VERSION 5.7 ;
BUSBITCHARS "[]" ;
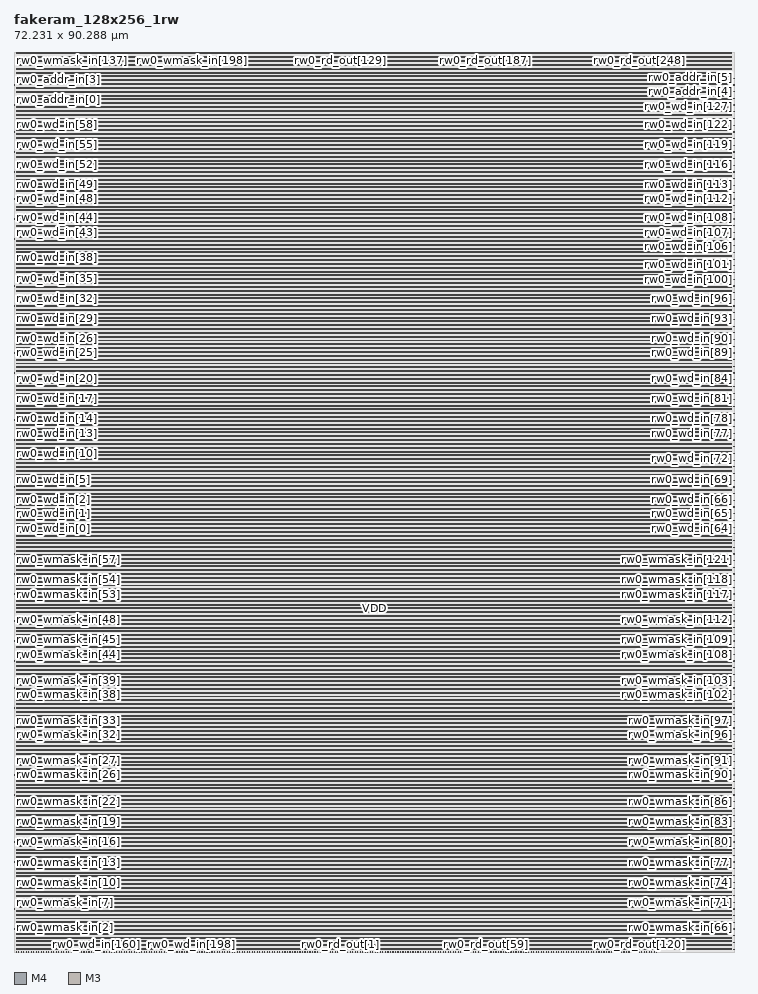
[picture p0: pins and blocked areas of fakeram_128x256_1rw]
MACRO fakeram_128x256_1rw
  FOREIGN fakeram_128x256_1rw 0 0 ;
  SYMMETRY X Y R90 ;
  SIZE 72.231 BY 90.288 ;
  CLASS BLOCK ;
  PIN rw0_wmask_in[0]
    DIRECTION INPUT ;
    USE SIGNAL ;
    SHAPE ABUTMENT ;
    PORT
      LAYER M4 ;
      RECT 0.000 0.276 0.072 0.300 ;
    END
  END rw0_wmask_in[0]
  PIN rw0_wmask_in[1]
    DIRECTION INPUT ;
    USE SIGNAL ;
    SHAPE ABUTMENT ;
    PORT
      LAYER M4 ;
      RECT 0.000 0.948 0.072 0.972 ;
    END
  END rw0_wmask_in[1]
  PIN rw0_wmask_in[2]
    DIRECTION INPUT ;
    USE SIGNAL ;
    SHAPE ABUTMENT ;
    PORT
      LAYER M4 ;
      RECT 0.000 1.620 0.072 1.644 ;
    END
  END rw0_wmask_in[2]
  PIN rw0_wmask_in[3]
    DIRECTION INPUT ;
    USE SIGNAL ;
    SHAPE ABUTMENT ;
    PORT
      LAYER M4 ;
      RECT 0.000 2.292 0.072 2.316 ;
    END
  END rw0_wmask_in[3]
  PIN rw0_wmask_in[4]
    DIRECTION INPUT ;
    USE SIGNAL ;
    SHAPE ABUTMENT ;
    PORT
      LAYER M4 ;
      RECT 0.000 2.964 0.072 2.988 ;
    END
  END rw0_wmask_in[4]
  PIN rw0_wmask_in[5]
    DIRECTION INPUT ;
    USE SIGNAL ;
    SHAPE ABUTMENT ;
    PORT
      LAYER M4 ;
      RECT 0.000 3.636 0.072 3.660 ;
    END
  END rw0_wmask_in[5]
  PIN rw0_wmask_in[6]
    DIRECTION INPUT ;
    USE SIGNAL ;
    SHAPE ABUTMENT ;
    PORT
      LAYER M4 ;
      RECT 0.000 4.308 0.072 4.332 ;
    END
  END rw0_wmask_in[6]
  PIN rw0_wmask_in[7]
    DIRECTION INPUT ;
    USE SIGNAL ;
    SHAPE ABUTMENT ;
    PORT
      LAYER M4 ;
      RECT 0.000 4.980 0.072 5.004 ;
    END
  END rw0_wmask_in[7]
  PIN rw0_wmask_in[8]
    DIRECTION INPUT ;
    USE SIGNAL ;
    SHAPE ABUTMENT ;
    PORT
      LAYER M4 ;
      RECT 0.000 5.652 0.072 5.676 ;
    END
  END rw0_wmask_in[8]
  PIN rw0_wmask_in[9]
    DIRECTION INPUT ;
    USE SIGNAL ;
    SHAPE ABUTMENT ;
    PORT
      LAYER M4 ;
      RECT 0.000 6.324 0.072 6.348 ;
    END
  END rw0_wmask_in[9]
  PIN rw0_wmask_in[10]
    DIRECTION INPUT ;
    USE SIGNAL ;
    SHAPE ABUTMENT ;
    PORT
      LAYER M4 ;
      RECT 0.000 6.996 0.072 7.020 ;
    END
  END rw0_wmask_in[10]
  PIN rw0_wmask_in[11]
    DIRECTION INPUT ;
    USE SIGNAL ;
    SHAPE ABUTMENT ;
    PORT
      LAYER M4 ;
      RECT 0.000 7.668 0.072 7.692 ;
    END
  END rw0_wmask_in[11]
  PIN rw0_wmask_in[12]
    DIRECTION INPUT ;
    USE SIGNAL ;
    SHAPE ABUTMENT ;
    PORT
      LAYER M4 ;
      RECT 0.000 8.340 0.072 8.364 ;
    END
  END rw0_wmask_in[12]
  PIN rw0_wmask_in[13]
    DIRECTION INPUT ;
    USE SIGNAL ;
    SHAPE ABUTMENT ;
    PORT
      LAYER M4 ;
      RECT 0.000 9.012 0.072 9.036 ;
    END
  END rw0_wmask_in[13]
  PIN rw0_wmask_in[14]
    DIRECTION INPUT ;
    USE SIGNAL ;
    SHAPE ABUTMENT ;
    PORT
      LAYER M4 ;
      RECT 0.000 9.684 0.072 9.708 ;
    END
  END rw0_wmask_in[14]
  PIN rw0_wmask_in[15]
    DIRECTION INPUT ;
    USE SIGNAL ;
    SHAPE ABUTMENT ;
    PORT
      LAYER M4 ;
      RECT 0.000 10.356 0.072 10.380 ;
    END
  END rw0_wmask_in[15]
  PIN rw0_wmask_in[16]
    DIRECTION INPUT ;
    USE SIGNAL ;
    SHAPE ABUTMENT ;
    PORT
      LAYER M4 ;
      RECT 0.000 11.028 0.072 11.052 ;
    END
  END rw0_wmask_in[16]
  PIN rw0_wmask_in[17]
    DIRECTION INPUT ;
    USE SIGNAL ;
    SHAPE ABUTMENT ;
    PORT
      LAYER M4 ;
      RECT 0.000 11.700 0.072 11.724 ;
    END
  END rw0_wmask_in[17]
  PIN rw0_wmask_in[18]
    DIRECTION INPUT ;
    USE SIGNAL ;
    SHAPE ABUTMENT ;
    PORT
      LAYER M4 ;
      RECT 0.000 12.372 0.072 12.396 ;
    END
  END rw0_wmask_in[18]
  PIN rw0_wmask_in[19]
    DIRECTION INPUT ;
    USE SIGNAL ;
    SHAPE ABUTMENT ;
    PORT
      LAYER M4 ;
      RECT 0.000 13.044 0.072 13.068 ;
    END
  END rw0_wmask_in[19]
  PIN rw0_wmask_in[20]
    DIRECTION INPUT ;
    USE SIGNAL ;
    SHAPE ABUTMENT ;
    PORT
      LAYER M4 ;
      RECT 0.000 13.716 0.072 13.740 ;
    END
  END rw0_wmask_in[20]
  PIN rw0_wmask_in[21]
    DIRECTION INPUT ;
    USE SIGNAL ;
    SHAPE ABUTMENT ;
    PORT
      LAYER M4 ;
      RECT 0.000 14.388 0.072 14.412 ;
    END
  END rw0_wmask_in[21]
  PIN rw0_wmask_in[22]
    DIRECTION INPUT ;
    USE SIGNAL ;
    SHAPE ABUTMENT ;
    PORT
      LAYER M4 ;
      RECT 0.000 15.060 0.072 15.084 ;
    END
  END rw0_wmask_in[22]
  PIN rw0_wmask_in[23]
    DIRECTION INPUT ;
    USE SIGNAL ;
    SHAPE ABUTMENT ;
    PORT
      LAYER M4 ;
      RECT 0.000 15.732 0.072 15.756 ;
    END
  END rw0_wmask_in[23]
  PIN rw0_wmask_in[24]
    DIRECTION INPUT ;
    USE SIGNAL ;
    SHAPE ABUTMENT ;
    PORT
      LAYER M4 ;
      RECT 0.000 16.404 0.072 16.428 ;
    END
  END rw0_wmask_in[24]
  PIN rw0_wmask_in[25]
    DIRECTION INPUT ;
    USE SIGNAL ;
    SHAPE ABUTMENT ;
    PORT
      LAYER M4 ;
      RECT 0.000 17.076 0.072 17.100 ;
    END
  END rw0_wmask_in[25]
  PIN rw0_wmask_in[26]
    DIRECTION INPUT ;
    USE SIGNAL ;
    SHAPE ABUTMENT ;
    PORT
      LAYER M4 ;
      RECT 0.000 17.748 0.072 17.772 ;
    END
  END rw0_wmask_in[26]
  PIN rw0_wmask_in[27]
    DIRECTION INPUT ;
    USE SIGNAL ;
    SHAPE ABUTMENT ;
    PORT
      LAYER M4 ;
      RECT 0.000 18.420 0.072 18.444 ;
    END
  END rw0_wmask_in[27]
  PIN rw0_wmask_in[28]
    DIRECTION INPUT ;
    USE SIGNAL ;
    SHAPE ABUTMENT ;
    PORT
      LAYER M4 ;
      RECT 0.000 19.092 0.072 19.116 ;
    END
  END rw0_wmask_in[28]
  PIN rw0_wmask_in[29]
    DIRECTION INPUT ;
    USE SIGNAL ;
    SHAPE ABUTMENT ;
    PORT
      LAYER M4 ;
      RECT 0.000 19.764 0.072 19.788 ;
    END
  END rw0_wmask_in[29]
  PIN rw0_wmask_in[30]
    DIRECTION INPUT ;
    USE SIGNAL ;
    SHAPE ABUTMENT ;
    PORT
      LAYER M4 ;
      RECT 0.000 20.436 0.072 20.460 ;
    END
  END rw0_wmask_in[30]
  PIN rw0_wmask_in[31]
    DIRECTION INPUT ;
    USE SIGNAL ;
    SHAPE ABUTMENT ;
    PORT
      LAYER M4 ;
      RECT 0.000 21.108 0.072 21.132 ;
    END
  END rw0_wmask_in[31]
  PIN rw0_wmask_in[32]
    DIRECTION INPUT ;
    USE SIGNAL ;
    SHAPE ABUTMENT ;
    PORT
      LAYER M4 ;
      RECT 0.000 21.780 0.072 21.804 ;
    END
  END rw0_wmask_in[32]
  PIN rw0_wmask_in[33]
    DIRECTION INPUT ;
    USE SIGNAL ;
    SHAPE ABUTMENT ;
    PORT
      LAYER M4 ;
      RECT 0.000 22.452 0.072 22.476 ;
    END
  END rw0_wmask_in[33]
  PIN rw0_wmask_in[34]
    DIRECTION INPUT ;
    USE SIGNAL ;
    SHAPE ABUTMENT ;
    PORT
      LAYER M4 ;
      RECT 0.000 23.124 0.072 23.148 ;
    END
  END rw0_wmask_in[34]
  PIN rw0_wmask_in[35]
    DIRECTION INPUT ;
    USE SIGNAL ;
    SHAPE ABUTMENT ;
    PORT
      LAYER M4 ;
      RECT 0.000 23.796 0.072 23.820 ;
    END
  END rw0_wmask_in[35]
  PIN rw0_wmask_in[36]
    DIRECTION INPUT ;
    USE SIGNAL ;
    SHAPE ABUTMENT ;
    PORT
      LAYER M4 ;
      RECT 0.000 24.468 0.072 24.492 ;
    END
  END rw0_wmask_in[36]
  PIN rw0_wmask_in[37]
    DIRECTION INPUT ;
    USE SIGNAL ;
    SHAPE ABUTMENT ;
    PORT
      LAYER M4 ;
      RECT 0.000 25.140 0.072 25.164 ;
    END
  END rw0_wmask_in[37]
  PIN rw0_wmask_in[38]
    DIRECTION INPUT ;
    USE SIGNAL ;
    SHAPE ABUTMENT ;
    PORT
      LAYER M4 ;
      RECT 0.000 25.812 0.072 25.836 ;
    END
  END rw0_wmask_in[38]
  PIN rw0_wmask_in[39]
    DIRECTION INPUT ;
    USE SIGNAL ;
    SHAPE ABUTMENT ;
    PORT
      LAYER M4 ;
      RECT 0.000 26.484 0.072 26.508 ;
    END
  END rw0_wmask_in[39]
  PIN rw0_wmask_in[40]
    DIRECTION INPUT ;
    USE SIGNAL ;
    SHAPE ABUTMENT ;
    PORT
      LAYER M4 ;
      RECT 0.000 27.156 0.072 27.180 ;
    END
  END rw0_wmask_in[40]
  PIN rw0_wmask_in[41]
    DIRECTION INPUT ;
    USE SIGNAL ;
    SHAPE ABUTMENT ;
    PORT
      LAYER M4 ;
      RECT 0.000 27.828 0.072 27.852 ;
    END
  END rw0_wmask_in[41]
  PIN rw0_wmask_in[42]
    DIRECTION INPUT ;
    USE SIGNAL ;
    SHAPE ABUTMENT ;
    PORT
      LAYER M4 ;
      RECT 0.000 28.500 0.072 28.524 ;
    END
  END rw0_wmask_in[42]
  PIN rw0_wmask_in[43]
    DIRECTION INPUT ;
    USE SIGNAL ;
    SHAPE ABUTMENT ;
    PORT
      LAYER M4 ;
      RECT 0.000 29.172 0.072 29.196 ;
    END
  END rw0_wmask_in[43]
  PIN rw0_wmask_in[44]
    DIRECTION INPUT ;
    USE SIGNAL ;
    SHAPE ABUTMENT ;
    PORT
      LAYER M4 ;
      RECT 0.000 29.844 0.072 29.868 ;
    END
  END rw0_wmask_in[44]
  PIN rw0_wmask_in[45]
    DIRECTION INPUT ;
    USE SIGNAL ;
    SHAPE ABUTMENT ;
    PORT
      LAYER M4 ;
      RECT 0.000 30.516 0.072 30.540 ;
    END
  END rw0_wmask_in[45]
  PIN rw0_wmask_in[46]
    DIRECTION INPUT ;
    USE SIGNAL ;
    SHAPE ABUTMENT ;
    PORT
      LAYER M4 ;
      RECT 0.000 31.188 0.072 31.212 ;
    END
  END rw0_wmask_in[46]
  PIN rw0_wmask_in[47]
    DIRECTION INPUT ;
    USE SIGNAL ;
    SHAPE ABUTMENT ;
    PORT
      LAYER M4 ;
      RECT 0.000 31.860 0.072 31.884 ;
    END
  END rw0_wmask_in[47]
  PIN rw0_wmask_in[48]
    DIRECTION INPUT ;
    USE SIGNAL ;
    SHAPE ABUTMENT ;
    PORT
      LAYER M4 ;
      RECT 0.000 32.532 0.072 32.556 ;
    END
  END rw0_wmask_in[48]
  PIN rw0_wmask_in[49]
    DIRECTION INPUT ;
    USE SIGNAL ;
    SHAPE ABUTMENT ;
    PORT
      LAYER M4 ;
      RECT 0.000 33.204 0.072 33.228 ;
    END
  END rw0_wmask_in[49]
  PIN rw0_wmask_in[50]
    DIRECTION INPUT ;
    USE SIGNAL ;
    SHAPE ABUTMENT ;
    PORT
      LAYER M4 ;
      RECT 0.000 33.876 0.072 33.900 ;
    END
  END rw0_wmask_in[50]
  PIN rw0_wmask_in[51]
    DIRECTION INPUT ;
    USE SIGNAL ;
    SHAPE ABUTMENT ;
    PORT
      LAYER M4 ;
      RECT 0.000 34.548 0.072 34.572 ;
    END
  END rw0_wmask_in[51]
  PIN rw0_wmask_in[52]
    DIRECTION INPUT ;
    USE SIGNAL ;
    SHAPE ABUTMENT ;
    PORT
      LAYER M4 ;
      RECT 0.000 35.220 0.072 35.244 ;
    END
  END rw0_wmask_in[52]
  PIN rw0_wmask_in[53]
    DIRECTION INPUT ;
    USE SIGNAL ;
    SHAPE ABUTMENT ;
    PORT
      LAYER M4 ;
      RECT 0.000 35.892 0.072 35.916 ;
    END
  END rw0_wmask_in[53]
  PIN rw0_wmask_in[54]
    DIRECTION INPUT ;
    USE SIGNAL ;
    SHAPE ABUTMENT ;
    PORT
      LAYER M4 ;
      RECT 0.000 36.564 0.072 36.588 ;
    END
  END rw0_wmask_in[54]
  PIN rw0_wmask_in[55]
    DIRECTION INPUT ;
    USE SIGNAL ;
    SHAPE ABUTMENT ;
    PORT
      LAYER M4 ;
      RECT 0.000 37.236 0.072 37.260 ;
    END
  END rw0_wmask_in[55]
  PIN rw0_wmask_in[56]
    DIRECTION INPUT ;
    USE SIGNAL ;
    SHAPE ABUTMENT ;
    PORT
      LAYER M4 ;
      RECT 0.000 37.908 0.072 37.932 ;
    END
  END rw0_wmask_in[56]
  PIN rw0_wmask_in[57]
    DIRECTION INPUT ;
    USE SIGNAL ;
    SHAPE ABUTMENT ;
    PORT
      LAYER M4 ;
      RECT 0.000 38.580 0.072 38.604 ;
    END
  END rw0_wmask_in[57]
  PIN rw0_wmask_in[58]
    DIRECTION INPUT ;
    USE SIGNAL ;
    SHAPE ABUTMENT ;
    PORT
      LAYER M4 ;
      RECT 0.000 39.252 0.072 39.276 ;
    END
  END rw0_wmask_in[58]
  PIN rw0_wmask_in[59]
    DIRECTION INPUT ;
    USE SIGNAL ;
    SHAPE ABUTMENT ;
    PORT
      LAYER M4 ;
      RECT 0.000 39.924 0.072 39.948 ;
    END
  END rw0_wmask_in[59]
  PIN rw0_wmask_in[60]
    DIRECTION INPUT ;
    USE SIGNAL ;
    SHAPE ABUTMENT ;
    PORT
      LAYER M4 ;
      RECT 0.000 40.596 0.072 40.620 ;
    END
  END rw0_wmask_in[60]
  PIN rw0_wmask_in[61]
    DIRECTION INPUT ;
    USE SIGNAL ;
    SHAPE ABUTMENT ;
    PORT
      LAYER M4 ;
      RECT 0.000 41.268 0.072 41.292 ;
    END
  END rw0_wmask_in[61]
  PIN rw0_wmask_in[62]
    DIRECTION INPUT ;
    USE SIGNAL ;
    SHAPE ABUTMENT ;
    PORT
      LAYER M4 ;
      RECT 0.000 41.940 0.072 41.964 ;
    END
  END rw0_wmask_in[62]
  PIN rw0_wmask_in[63]
    DIRECTION INPUT ;
    USE SIGNAL ;
    SHAPE ABUTMENT ;
    PORT
      LAYER M4 ;
      RECT 0.000 42.612 0.072 42.636 ;
    END
  END rw0_wmask_in[63]
  PIN rw0_wmask_in[64]
    DIRECTION INPUT ;
    USE SIGNAL ;
    SHAPE ABUTMENT ;
    PORT
      LAYER M4 ;
      RECT 72.159 0.276 72.231 0.300 ;
    END
  END rw0_wmask_in[64]
  PIN rw0_wmask_in[65]
    DIRECTION INPUT ;
    USE SIGNAL ;
    SHAPE ABUTMENT ;
    PORT
      LAYER M4 ;
      RECT 72.159 0.948 72.231 0.972 ;
    END
  END rw0_wmask_in[65]
  PIN rw0_wmask_in[66]
    DIRECTION INPUT ;
    USE SIGNAL ;
    SHAPE ABUTMENT ;
    PORT
      LAYER M4 ;
      RECT 72.159 1.620 72.231 1.644 ;
    END
  END rw0_wmask_in[66]
  PIN rw0_wmask_in[67]
    DIRECTION INPUT ;
    USE SIGNAL ;
    SHAPE ABUTMENT ;
    PORT
      LAYER M4 ;
      RECT 72.159 2.292 72.231 2.316 ;
    END
  END rw0_wmask_in[67]
  PIN rw0_wmask_in[68]
    DIRECTION INPUT ;
    USE SIGNAL ;
    SHAPE ABUTMENT ;
    PORT
      LAYER M4 ;
      RECT 72.159 2.964 72.231 2.988 ;
    END
  END rw0_wmask_in[68]
  PIN rw0_wmask_in[69]
    DIRECTION INPUT ;
    USE SIGNAL ;
    SHAPE ABUTMENT ;
    PORT
      LAYER M4 ;
      RECT 72.159 3.636 72.231 3.660 ;
    END
  END rw0_wmask_in[69]
  PIN rw0_wmask_in[70]
    DIRECTION INPUT ;
    USE SIGNAL ;
    SHAPE ABUTMENT ;
    PORT
      LAYER M4 ;
      RECT 72.159 4.308 72.231 4.332 ;
    END
  END rw0_wmask_in[70]
  PIN rw0_wmask_in[71]
    DIRECTION INPUT ;
    USE SIGNAL ;
    SHAPE ABUTMENT ;
    PORT
      LAYER M4 ;
      RECT 72.159 4.980 72.231 5.004 ;
    END
  END rw0_wmask_in[71]
  PIN rw0_wmask_in[72]
    DIRECTION INPUT ;
    USE SIGNAL ;
    SHAPE ABUTMENT ;
    PORT
      LAYER M4 ;
      RECT 72.159 5.652 72.231 5.676 ;
    END
  END rw0_wmask_in[72]
  PIN rw0_wmask_in[73]
    DIRECTION INPUT ;
    USE SIGNAL ;
    SHAPE ABUTMENT ;
    PORT
      LAYER M4 ;
      RECT 72.159 6.324 72.231 6.348 ;
    END
  END rw0_wmask_in[73]
  PIN rw0_wmask_in[74]
    DIRECTION INPUT ;
    USE SIGNAL ;
    SHAPE ABUTMENT ;
    PORT
      LAYER M4 ;
      RECT 72.159 6.996 72.231 7.020 ;
    END
  END rw0_wmask_in[74]
  PIN rw0_wmask_in[75]
    DIRECTION INPUT ;
    USE SIGNAL ;
    SHAPE ABUTMENT ;
    PORT
      LAYER M4 ;
      RECT 72.159 7.668 72.231 7.692 ;
    END
  END rw0_wmask_in[75]
  PIN rw0_wmask_in[76]
    DIRECTION INPUT ;
    USE SIGNAL ;
    SHAPE ABUTMENT ;
    PORT
      LAYER M4 ;
      RECT 72.159 8.340 72.231 8.364 ;
    END
  END rw0_wmask_in[76]
  PIN rw0_wmask_in[77]
    DIRECTION INPUT ;
    USE SIGNAL ;
    SHAPE ABUTMENT ;
    PORT
      LAYER M4 ;
      RECT 72.159 9.012 72.231 9.036 ;
    END
  END rw0_wmask_in[77]
  PIN rw0_wmask_in[78]
    DIRECTION INPUT ;
    USE SIGNAL ;
    SHAPE ABUTMENT ;
    PORT
      LAYER M4 ;
      RECT 72.159 9.684 72.231 9.708 ;
    END
  END rw0_wmask_in[78]
  PIN rw0_wmask_in[79]
    DIRECTION INPUT ;
    USE SIGNAL ;
    SHAPE ABUTMENT ;
    PORT
      LAYER M4 ;
      RECT 72.159 10.356 72.231 10.380 ;
    END
  END rw0_wmask_in[79]
  PIN rw0_wmask_in[80]
    DIRECTION INPUT ;
    USE SIGNAL ;
    SHAPE ABUTMENT ;
    PORT
      LAYER M4 ;
      RECT 72.159 11.028 72.231 11.052 ;
    END
  END rw0_wmask_in[80]
  PIN rw0_wmask_in[81]
    DIRECTION INPUT ;
    USE SIGNAL ;
    SHAPE ABUTMENT ;
    PORT
      LAYER M4 ;
      RECT 72.159 11.700 72.231 11.724 ;
    END
  END rw0_wmask_in[81]
  PIN rw0_wmask_in[82]
    DIRECTION INPUT ;
    USE SIGNAL ;
    SHAPE ABUTMENT ;
    PORT
      LAYER M4 ;
      RECT 72.159 12.372 72.231 12.396 ;
    END
  END rw0_wmask_in[82]
  PIN rw0_wmask_in[83]
    DIRECTION INPUT ;
    USE SIGNAL ;
    SHAPE ABUTMENT ;
    PORT
      LAYER M4 ;
      RECT 72.159 13.044 72.231 13.068 ;
    END
  END rw0_wmask_in[83]
  PIN rw0_wmask_in[84]
    DIRECTION INPUT ;
    USE SIGNAL ;
    SHAPE ABUTMENT ;
    PORT
      LAYER M4 ;
      RECT 72.159 13.716 72.231 13.740 ;
    END
  END rw0_wmask_in[84]
  PIN rw0_wmask_in[85]
    DIRECTION INPUT ;
    USE SIGNAL ;
    SHAPE ABUTMENT ;
    PORT
      LAYER M4 ;
      RECT 72.159 14.388 72.231 14.412 ;
    END
  END rw0_wmask_in[85]
  PIN rw0_wmask_in[86]
    DIRECTION INPUT ;
    USE SIGNAL ;
    SHAPE ABUTMENT ;
    PORT
      LAYER M4 ;
      RECT 72.159 15.060 72.231 15.084 ;
    END
  END rw0_wmask_in[86]
  PIN rw0_wmask_in[87]
    DIRECTION INPUT ;
    USE SIGNAL ;
    SHAPE ABUTMENT ;
    PORT
      LAYER M4 ;
      RECT 72.159 15.732 72.231 15.756 ;
    END
  END rw0_wmask_in[87]
  PIN rw0_wmask_in[88]
    DIRECTION INPUT ;
    USE SIGNAL ;
    SHAPE ABUTMENT ;
    PORT
      LAYER M4 ;
      RECT 72.159 16.404 72.231 16.428 ;
    END
  END rw0_wmask_in[88]
  PIN rw0_wmask_in[89]
    DIRECTION INPUT ;
    USE SIGNAL ;
    SHAPE ABUTMENT ;
    PORT
      LAYER M4 ;
      RECT 72.159 17.076 72.231 17.100 ;
    END
  END rw0_wmask_in[89]
  PIN rw0_wmask_in[90]
    DIRECTION INPUT ;
    USE SIGNAL ;
    SHAPE ABUTMENT ;
    PORT
      LAYER M4 ;
      RECT 72.159 17.748 72.231 17.772 ;
    END
  END rw0_wmask_in[90]
  PIN rw0_wmask_in[91]
    DIRECTION INPUT ;
    USE SIGNAL ;
    SHAPE ABUTMENT ;
    PORT
      LAYER M4 ;
      RECT 72.159 18.420 72.231 18.444 ;
    END
  END rw0_wmask_in[91]
  PIN rw0_wmask_in[92]
    DIRECTION INPUT ;
    USE SIGNAL ;
    SHAPE ABUTMENT ;
    PORT
      LAYER M4 ;
      RECT 72.159 19.092 72.231 19.116 ;
    END
  END rw0_wmask_in[92]
  PIN rw0_wmask_in[93]
    DIRECTION INPUT ;
    USE SIGNAL ;
    SHAPE ABUTMENT ;
    PORT
      LAYER M4 ;
      RECT 72.159 19.764 72.231 19.788 ;
    END
  END rw0_wmask_in[93]
  PIN rw0_wmask_in[94]
    DIRECTION INPUT ;
    USE SIGNAL ;
    SHAPE ABUTMENT ;
    PORT
      LAYER M4 ;
      RECT 72.159 20.436 72.231 20.460 ;
    END
  END rw0_wmask_in[94]
  PIN rw0_wmask_in[95]
    DIRECTION INPUT ;
    USE SIGNAL ;
    SHAPE ABUTMENT ;
    PORT
      LAYER M4 ;
      RECT 72.159 21.108 72.231 21.132 ;
    END
  END rw0_wmask_in[95]
  PIN rw0_wmask_in[96]
    DIRECTION INPUT ;
    USE SIGNAL ;
    SHAPE ABUTMENT ;
    PORT
      LAYER M4 ;
      RECT 72.159 21.780 72.231 21.804 ;
    END
  END rw0_wmask_in[96]
  PIN rw0_wmask_in[97]
    DIRECTION INPUT ;
    USE SIGNAL ;
    SHAPE ABUTMENT ;
    PORT
      LAYER M4 ;
      RECT 72.159 22.452 72.231 22.476 ;
    END
  END rw0_wmask_in[97]
  PIN rw0_wmask_in[98]
    DIRECTION INPUT ;
    USE SIGNAL ;
    SHAPE ABUTMENT ;
    PORT
      LAYER M4 ;
      RECT 72.159 23.124 72.231 23.148 ;
    END
  END rw0_wmask_in[98]
  PIN rw0_wmask_in[99]
    DIRECTION INPUT ;
    USE SIGNAL ;
    SHAPE ABUTMENT ;
    PORT
      LAYER M4 ;
      RECT 72.159 23.796 72.231 23.820 ;
    END
  END rw0_wmask_in[99]
  PIN rw0_wmask_in[100]
    DIRECTION INPUT ;
    USE SIGNAL ;
    SHAPE ABUTMENT ;
    PORT
      LAYER M4 ;
      RECT 72.159 24.468 72.231 24.492 ;
    END
  END rw0_wmask_in[100]
  PIN rw0_wmask_in[101]
    DIRECTION INPUT ;
    USE SIGNAL ;
    SHAPE ABUTMENT ;
    PORT
      LAYER M4 ;
      RECT 72.159 25.140 72.231 25.164 ;
    END
  END rw0_wmask_in[101]
  PIN rw0_wmask_in[102]
    DIRECTION INPUT ;
    USE SIGNAL ;
    SHAPE ABUTMENT ;
    PORT
      LAYER M4 ;
      RECT 72.159 25.812 72.231 25.836 ;
    END
  END rw0_wmask_in[102]
  PIN rw0_wmask_in[103]
    DIRECTION INPUT ;
    USE SIGNAL ;
    SHAPE ABUTMENT ;
    PORT
      LAYER M4 ;
      RECT 72.159 26.484 72.231 26.508 ;
    END
  END rw0_wmask_in[103]
  PIN rw0_wmask_in[104]
    DIRECTION INPUT ;
    USE SIGNAL ;
    SHAPE ABUTMENT ;
    PORT
      LAYER M4 ;
      RECT 72.159 27.156 72.231 27.180 ;
    END
  END rw0_wmask_in[104]
  PIN rw0_wmask_in[105]
    DIRECTION INPUT ;
    USE SIGNAL ;
    SHAPE ABUTMENT ;
    PORT
      LAYER M4 ;
      RECT 72.159 27.828 72.231 27.852 ;
    END
  END rw0_wmask_in[105]
  PIN rw0_wmask_in[106]
    DIRECTION INPUT ;
    USE SIGNAL ;
    SHAPE ABUTMENT ;
    PORT
      LAYER M4 ;
      RECT 72.159 28.500 72.231 28.524 ;
    END
  END rw0_wmask_in[106]
  PIN rw0_wmask_in[107]
    DIRECTION INPUT ;
    USE SIGNAL ;
    SHAPE ABUTMENT ;
    PORT
      LAYER M4 ;
      RECT 72.159 29.172 72.231 29.196 ;
    END
  END rw0_wmask_in[107]
  PIN rw0_wmask_in[108]
    DIRECTION INPUT ;
    USE SIGNAL ;
    SHAPE ABUTMENT ;
    PORT
      LAYER M4 ;
      RECT 72.159 29.844 72.231 29.868 ;
    END
  END rw0_wmask_in[108]
  PIN rw0_wmask_in[109]
    DIRECTION INPUT ;
    USE SIGNAL ;
    SHAPE ABUTMENT ;
    PORT
      LAYER M4 ;
      RECT 72.159 30.516 72.231 30.540 ;
    END
  END rw0_wmask_in[109]
  PIN rw0_wmask_in[110]
    DIRECTION INPUT ;
    USE SIGNAL ;
    SHAPE ABUTMENT ;
    PORT
      LAYER M4 ;
      RECT 72.159 31.188 72.231 31.212 ;
    END
  END rw0_wmask_in[110]
  PIN rw0_wmask_in[111]
    DIRECTION INPUT ;
    USE SIGNAL ;
    SHAPE ABUTMENT ;
    PORT
      LAYER M4 ;
      RECT 72.159 31.860 72.231 31.884 ;
    END
  END rw0_wmask_in[111]
  PIN rw0_wmask_in[112]
    DIRECTION INPUT ;
    USE SIGNAL ;
    SHAPE ABUTMENT ;
    PORT
      LAYER M4 ;
      RECT 72.159 32.532 72.231 32.556 ;
    END
  END rw0_wmask_in[112]
  PIN rw0_wmask_in[113]
    DIRECTION INPUT ;
    USE SIGNAL ;
    SHAPE ABUTMENT ;
    PORT
      LAYER M4 ;
      RECT 72.159 33.204 72.231 33.228 ;
    END
  END rw0_wmask_in[113]
  PIN rw0_wmask_in[114]
    DIRECTION INPUT ;
    USE SIGNAL ;
    SHAPE ABUTMENT ;
    PORT
      LAYER M4 ;
      RECT 72.159 33.876 72.231 33.900 ;
    END
  END rw0_wmask_in[114]
  PIN rw0_wmask_in[115]
    DIRECTION INPUT ;
    USE SIGNAL ;
    SHAPE ABUTMENT ;
    PORT
      LAYER M4 ;
      RECT 72.159 34.548 72.231 34.572 ;
    END
  END rw0_wmask_in[115]
  PIN rw0_wmask_in[116]
    DIRECTION INPUT ;
    USE SIGNAL ;
    SHAPE ABUTMENT ;
    PORT
      LAYER M4 ;
      RECT 72.159 35.220 72.231 35.244 ;
    END
  END rw0_wmask_in[116]
  PIN rw0_wmask_in[117]
    DIRECTION INPUT ;
    USE SIGNAL ;
    SHAPE ABUTMENT ;
    PORT
      LAYER M4 ;
      RECT 72.159 35.892 72.231 35.916 ;
    END
  END rw0_wmask_in[117]
  PIN rw0_wmask_in[118]
    DIRECTION INPUT ;
    USE SIGNAL ;
    SHAPE ABUTMENT ;
    PORT
      LAYER M4 ;
      RECT 72.159 36.564 72.231 36.588 ;
    END
  END rw0_wmask_in[118]
  PIN rw0_wmask_in[119]
    DIRECTION INPUT ;
    USE SIGNAL ;
    SHAPE ABUTMENT ;
    PORT
      LAYER M4 ;
      RECT 72.159 37.236 72.231 37.260 ;
    END
  END rw0_wmask_in[119]
  PIN rw0_wmask_in[120]
    DIRECTION INPUT ;
    USE SIGNAL ;
    SHAPE ABUTMENT ;
    PORT
      LAYER M4 ;
      RECT 72.159 37.908 72.231 37.932 ;
    END
  END rw0_wmask_in[120]
  PIN rw0_wmask_in[121]
    DIRECTION INPUT ;
    USE SIGNAL ;
    SHAPE ABUTMENT ;
    PORT
      LAYER M4 ;
      RECT 72.159 38.580 72.231 38.604 ;
    END
  END rw0_wmask_in[121]
  PIN rw0_wmask_in[122]
    DIRECTION INPUT ;
    USE SIGNAL ;
    SHAPE ABUTMENT ;
    PORT
      LAYER M4 ;
      RECT 72.159 39.252 72.231 39.276 ;
    END
  END rw0_wmask_in[122]
  PIN rw0_wmask_in[123]
    DIRECTION INPUT ;
    USE SIGNAL ;
    SHAPE ABUTMENT ;
    PORT
      LAYER M4 ;
      RECT 72.159 39.924 72.231 39.948 ;
    END
  END rw0_wmask_in[123]
  PIN rw0_wmask_in[124]
    DIRECTION INPUT ;
    USE SIGNAL ;
    SHAPE ABUTMENT ;
    PORT
      LAYER M4 ;
      RECT 72.159 40.596 72.231 40.620 ;
    END
  END rw0_wmask_in[124]
  PIN rw0_wmask_in[125]
    DIRECTION INPUT ;
    USE SIGNAL ;
    SHAPE ABUTMENT ;
    PORT
      LAYER M4 ;
      RECT 72.159 41.268 72.231 41.292 ;
    END
  END rw0_wmask_in[125]
  PIN rw0_wmask_in[126]
    DIRECTION INPUT ;
    USE SIGNAL ;
    SHAPE ABUTMENT ;
    PORT
      LAYER M4 ;
      RECT 72.159 41.940 72.231 41.964 ;
    END
  END rw0_wmask_in[126]
  PIN rw0_wmask_in[127]
    DIRECTION INPUT ;
    USE SIGNAL ;
    SHAPE ABUTMENT ;
    PORT
      LAYER M4 ;
      RECT 72.159 42.612 72.231 42.636 ;
    END
  END rw0_wmask_in[127]
  PIN rw0_wmask_in[128]
    DIRECTION INPUT ;
    USE SIGNAL ;
    SHAPE ABUTMENT ;
    PORT
      LAYER M3 ;
      RECT 0.207 90.234 0.225 90.288 ;
    END
  END rw0_wmask_in[128]
  PIN rw0_wmask_in[129]
    DIRECTION INPUT ;
    USE SIGNAL ;
    SHAPE ABUTMENT ;
    PORT
      LAYER M3 ;
      RECT 0.459 90.234 0.477 90.288 ;
    END
  END rw0_wmask_in[129]
  PIN rw0_wmask_in[130]
    DIRECTION INPUT ;
    USE SIGNAL ;
    SHAPE ABUTMENT ;
    PORT
      LAYER M3 ;
      RECT 0.711 90.234 0.729 90.288 ;
    END
  END rw0_wmask_in[130]
  PIN rw0_wmask_in[131]
    DIRECTION INPUT ;
    USE SIGNAL ;
    SHAPE ABUTMENT ;
    PORT
      LAYER M3 ;
      RECT 0.963 90.234 0.981 90.288 ;
    END
  END rw0_wmask_in[131]
  PIN rw0_wmask_in[132]
    DIRECTION INPUT ;
    USE SIGNAL ;
    SHAPE ABUTMENT ;
    PORT
      LAYER M3 ;
      RECT 1.215 90.234 1.233 90.288 ;
    END
  END rw0_wmask_in[132]
  PIN rw0_wmask_in[133]
    DIRECTION INPUT ;
    USE SIGNAL ;
    SHAPE ABUTMENT ;
    PORT
      LAYER M3 ;
      RECT 1.467 90.234 1.485 90.288 ;
    END
  END rw0_wmask_in[133]
  PIN rw0_wmask_in[134]
    DIRECTION INPUT ;
    USE SIGNAL ;
    SHAPE ABUTMENT ;
    PORT
      LAYER M3 ;
      RECT 1.719 90.234 1.737 90.288 ;
    END
  END rw0_wmask_in[134]
  PIN rw0_wmask_in[135]
    DIRECTION INPUT ;
    USE SIGNAL ;
    SHAPE ABUTMENT ;
    PORT
      LAYER M3 ;
      RECT 1.971 90.234 1.989 90.288 ;
    END
  END rw0_wmask_in[135]
  PIN rw0_wmask_in[136]
    DIRECTION INPUT ;
    USE SIGNAL ;
    SHAPE ABUTMENT ;
    PORT
      LAYER M3 ;
      RECT 2.223 90.234 2.241 90.288 ;
    END
  END rw0_wmask_in[136]
  PIN rw0_wmask_in[137]
    DIRECTION INPUT ;
    USE SIGNAL ;
    SHAPE ABUTMENT ;
    PORT
      LAYER M3 ;
      RECT 2.475 90.234 2.493 90.288 ;
    END
  END rw0_wmask_in[137]
  PIN rw0_wmask_in[138]
    DIRECTION INPUT ;
    USE SIGNAL ;
    SHAPE ABUTMENT ;
    PORT
      LAYER M3 ;
      RECT 2.727 90.234 2.745 90.288 ;
    END
  END rw0_wmask_in[138]
  PIN rw0_wmask_in[139]
    DIRECTION INPUT ;
    USE SIGNAL ;
    SHAPE ABUTMENT ;
    PORT
      LAYER M3 ;
      RECT 2.979 90.234 2.997 90.288 ;
    END
  END rw0_wmask_in[139]
  PIN rw0_wmask_in[140]
    DIRECTION INPUT ;
    USE SIGNAL ;
    SHAPE ABUTMENT ;
    PORT
      LAYER M3 ;
      RECT 3.231 90.234 3.249 90.288 ;
    END
  END rw0_wmask_in[140]
  PIN rw0_wmask_in[141]
    DIRECTION INPUT ;
    USE SIGNAL ;
    SHAPE ABUTMENT ;
    PORT
      LAYER M3 ;
      RECT 3.483 90.234 3.501 90.288 ;
    END
  END rw0_wmask_in[141]
  PIN rw0_wmask_in[142]
    DIRECTION INPUT ;
    USE SIGNAL ;
    SHAPE ABUTMENT ;
    PORT
      LAYER M3 ;
      RECT 3.735 90.234 3.753 90.288 ;
    END
  END rw0_wmask_in[142]
  PIN rw0_wmask_in[143]
    DIRECTION INPUT ;
    USE SIGNAL ;
    SHAPE ABUTMENT ;
    PORT
      LAYER M3 ;
      RECT 3.987 90.234 4.005 90.288 ;
    END
  END rw0_wmask_in[143]
  PIN rw0_wmask_in[144]
    DIRECTION INPUT ;
    USE SIGNAL ;
    SHAPE ABUTMENT ;
    PORT
      LAYER M3 ;
      RECT 4.239 90.234 4.257 90.288 ;
    END
  END rw0_wmask_in[144]
  PIN rw0_wmask_in[145]
    DIRECTION INPUT ;
    USE SIGNAL ;
    SHAPE ABUTMENT ;
    PORT
      LAYER M3 ;
      RECT 4.491 90.234 4.509 90.288 ;
    END
  END rw0_wmask_in[145]
  PIN rw0_wmask_in[146]
    DIRECTION INPUT ;
    USE SIGNAL ;
    SHAPE ABUTMENT ;
    PORT
      LAYER M3 ;
      RECT 4.743 90.234 4.761 90.288 ;
    END
  END rw0_wmask_in[146]
  PIN rw0_wmask_in[147]
    DIRECTION INPUT ;
    USE SIGNAL ;
    SHAPE ABUTMENT ;
    PORT
      LAYER M3 ;
      RECT 4.995 90.234 5.013 90.288 ;
    END
  END rw0_wmask_in[147]
  PIN rw0_wmask_in[148]
    DIRECTION INPUT ;
    USE SIGNAL ;
    SHAPE ABUTMENT ;
    PORT
      LAYER M3 ;
      RECT 5.247 90.234 5.265 90.288 ;
    END
  END rw0_wmask_in[148]
  PIN rw0_wmask_in[149]
    DIRECTION INPUT ;
    USE SIGNAL ;
    SHAPE ABUTMENT ;
    PORT
      LAYER M3 ;
      RECT 5.499 90.234 5.517 90.288 ;
    END
  END rw0_wmask_in[149]
  PIN rw0_wmask_in[150]
    DIRECTION INPUT ;
    USE SIGNAL ;
    SHAPE ABUTMENT ;
    PORT
      LAYER M3 ;
      RECT 5.751 90.234 5.769 90.288 ;
    END
  END rw0_wmask_in[150]
  PIN rw0_wmask_in[151]
    DIRECTION INPUT ;
    USE SIGNAL ;
    SHAPE ABUTMENT ;
    PORT
      LAYER M3 ;
      RECT 6.003 90.234 6.021 90.288 ;
    END
  END rw0_wmask_in[151]
  PIN rw0_wmask_in[152]
    DIRECTION INPUT ;
    USE SIGNAL ;
    SHAPE ABUTMENT ;
    PORT
      LAYER M3 ;
      RECT 6.255 90.234 6.273 90.288 ;
    END
  END rw0_wmask_in[152]
  PIN rw0_wmask_in[153]
    DIRECTION INPUT ;
    USE SIGNAL ;
    SHAPE ABUTMENT ;
    PORT
      LAYER M3 ;
      RECT 6.507 90.234 6.525 90.288 ;
    END
  END rw0_wmask_in[153]
  PIN rw0_wmask_in[154]
    DIRECTION INPUT ;
    USE SIGNAL ;
    SHAPE ABUTMENT ;
    PORT
      LAYER M3 ;
      RECT 6.759 90.234 6.777 90.288 ;
    END
  END rw0_wmask_in[154]
  PIN rw0_wmask_in[155]
    DIRECTION INPUT ;
    USE SIGNAL ;
    SHAPE ABUTMENT ;
    PORT
      LAYER M3 ;
      RECT 7.011 90.234 7.029 90.288 ;
    END
  END rw0_wmask_in[155]
  PIN rw0_wmask_in[156]
    DIRECTION INPUT ;
    USE SIGNAL ;
    SHAPE ABUTMENT ;
    PORT
      LAYER M3 ;
      RECT 7.263 90.234 7.281 90.288 ;
    END
  END rw0_wmask_in[156]
  PIN rw0_wmask_in[157]
    DIRECTION INPUT ;
    USE SIGNAL ;
    SHAPE ABUTMENT ;
    PORT
      LAYER M3 ;
      RECT 7.515 90.234 7.533 90.288 ;
    END
  END rw0_wmask_in[157]
  PIN rw0_wmask_in[158]
    DIRECTION INPUT ;
    USE SIGNAL ;
    SHAPE ABUTMENT ;
    PORT
      LAYER M3 ;
      RECT 7.767 90.234 7.785 90.288 ;
    END
  END rw0_wmask_in[158]
  PIN rw0_wmask_in[159]
    DIRECTION INPUT ;
    USE SIGNAL ;
    SHAPE ABUTMENT ;
    PORT
      LAYER M3 ;
      RECT 8.019 90.234 8.037 90.288 ;
    END
  END rw0_wmask_in[159]
  PIN rw0_wmask_in[160]
    DIRECTION INPUT ;
    USE SIGNAL ;
    SHAPE ABUTMENT ;
    PORT
      LAYER M3 ;
      RECT 8.271 90.234 8.289 90.288 ;
    END
  END rw0_wmask_in[160]
  PIN rw0_wmask_in[161]
    DIRECTION INPUT ;
    USE SIGNAL ;
    SHAPE ABUTMENT ;
    PORT
      LAYER M3 ;
      RECT 8.523 90.234 8.541 90.288 ;
    END
  END rw0_wmask_in[161]
  PIN rw0_wmask_in[162]
    DIRECTION INPUT ;
    USE SIGNAL ;
    SHAPE ABUTMENT ;
    PORT
      LAYER M3 ;
      RECT 8.775 90.234 8.793 90.288 ;
    END
  END rw0_wmask_in[162]
  PIN rw0_wmask_in[163]
    DIRECTION INPUT ;
    USE SIGNAL ;
    SHAPE ABUTMENT ;
    PORT
      LAYER M3 ;
      RECT 9.027 90.234 9.045 90.288 ;
    END
  END rw0_wmask_in[163]
  PIN rw0_wmask_in[164]
    DIRECTION INPUT ;
    USE SIGNAL ;
    SHAPE ABUTMENT ;
    PORT
      LAYER M3 ;
      RECT 9.279 90.234 9.297 90.288 ;
    END
  END rw0_wmask_in[164]
  PIN rw0_wmask_in[165]
    DIRECTION INPUT ;
    USE SIGNAL ;
    SHAPE ABUTMENT ;
    PORT
      LAYER M3 ;
      RECT 9.531 90.234 9.549 90.288 ;
    END
  END rw0_wmask_in[165]
  PIN rw0_wmask_in[166]
    DIRECTION INPUT ;
    USE SIGNAL ;
    SHAPE ABUTMENT ;
    PORT
      LAYER M3 ;
      RECT 9.783 90.234 9.801 90.288 ;
    END
  END rw0_wmask_in[166]
  PIN rw0_wmask_in[167]
    DIRECTION INPUT ;
    USE SIGNAL ;
    SHAPE ABUTMENT ;
    PORT
      LAYER M3 ;
      RECT 10.035 90.234 10.053 90.288 ;
    END
  END rw0_wmask_in[167]
  PIN rw0_wmask_in[168]
    DIRECTION INPUT ;
    USE SIGNAL ;
    SHAPE ABUTMENT ;
    PORT
      LAYER M3 ;
      RECT 10.287 90.234 10.305 90.288 ;
    END
  END rw0_wmask_in[168]
  PIN rw0_wmask_in[169]
    DIRECTION INPUT ;
    USE SIGNAL ;
    SHAPE ABUTMENT ;
    PORT
      LAYER M3 ;
      RECT 10.539 90.234 10.557 90.288 ;
    END
  END rw0_wmask_in[169]
  PIN rw0_wmask_in[170]
    DIRECTION INPUT ;
    USE SIGNAL ;
    SHAPE ABUTMENT ;
    PORT
      LAYER M3 ;
      RECT 10.791 90.234 10.809 90.288 ;
    END
  END rw0_wmask_in[170]
  PIN rw0_wmask_in[171]
    DIRECTION INPUT ;
    USE SIGNAL ;
    SHAPE ABUTMENT ;
    PORT
      LAYER M3 ;
      RECT 11.043 90.234 11.061 90.288 ;
    END
  END rw0_wmask_in[171]
  PIN rw0_wmask_in[172]
    DIRECTION INPUT ;
    USE SIGNAL ;
    SHAPE ABUTMENT ;
    PORT
      LAYER M3 ;
      RECT 11.295 90.234 11.313 90.288 ;
    END
  END rw0_wmask_in[172]
  PIN rw0_wmask_in[173]
    DIRECTION INPUT ;
    USE SIGNAL ;
    SHAPE ABUTMENT ;
    PORT
      LAYER M3 ;
      RECT 11.547 90.234 11.565 90.288 ;
    END
  END rw0_wmask_in[173]
  PIN rw0_wmask_in[174]
    DIRECTION INPUT ;
    USE SIGNAL ;
    SHAPE ABUTMENT ;
    PORT
      LAYER M3 ;
      RECT 11.799 90.234 11.817 90.288 ;
    END
  END rw0_wmask_in[174]
  PIN rw0_wmask_in[175]
    DIRECTION INPUT ;
    USE SIGNAL ;
    SHAPE ABUTMENT ;
    PORT
      LAYER M3 ;
      RECT 12.051 90.234 12.069 90.288 ;
    END
  END rw0_wmask_in[175]
  PIN rw0_wmask_in[176]
    DIRECTION INPUT ;
    USE SIGNAL ;
    SHAPE ABUTMENT ;
    PORT
      LAYER M3 ;
      RECT 12.303 90.234 12.321 90.288 ;
    END
  END rw0_wmask_in[176]
  PIN rw0_wmask_in[177]
    DIRECTION INPUT ;
    USE SIGNAL ;
    SHAPE ABUTMENT ;
    PORT
      LAYER M3 ;
      RECT 12.555 90.234 12.573 90.288 ;
    END
  END rw0_wmask_in[177]
  PIN rw0_wmask_in[178]
    DIRECTION INPUT ;
    USE SIGNAL ;
    SHAPE ABUTMENT ;
    PORT
      LAYER M3 ;
      RECT 12.807 90.234 12.825 90.288 ;
    END
  END rw0_wmask_in[178]
  PIN rw0_wmask_in[179]
    DIRECTION INPUT ;
    USE SIGNAL ;
    SHAPE ABUTMENT ;
    PORT
      LAYER M3 ;
      RECT 13.059 90.234 13.077 90.288 ;
    END
  END rw0_wmask_in[179]
  PIN rw0_wmask_in[180]
    DIRECTION INPUT ;
    USE SIGNAL ;
    SHAPE ABUTMENT ;
    PORT
      LAYER M3 ;
      RECT 13.311 90.234 13.329 90.288 ;
    END
  END rw0_wmask_in[180]
  PIN rw0_wmask_in[181]
    DIRECTION INPUT ;
    USE SIGNAL ;
    SHAPE ABUTMENT ;
    PORT
      LAYER M3 ;
      RECT 13.563 90.234 13.581 90.288 ;
    END
  END rw0_wmask_in[181]
  PIN rw0_wmask_in[182]
    DIRECTION INPUT ;
    USE SIGNAL ;
    SHAPE ABUTMENT ;
    PORT
      LAYER M3 ;
      RECT 13.815 90.234 13.833 90.288 ;
    END
  END rw0_wmask_in[182]
  PIN rw0_wmask_in[183]
    DIRECTION INPUT ;
    USE SIGNAL ;
    SHAPE ABUTMENT ;
    PORT
      LAYER M3 ;
      RECT 14.067 90.234 14.085 90.288 ;
    END
  END rw0_wmask_in[183]
  PIN rw0_wmask_in[184]
    DIRECTION INPUT ;
    USE SIGNAL ;
    SHAPE ABUTMENT ;
    PORT
      LAYER M3 ;
      RECT 14.319 90.234 14.337 90.288 ;
    END
  END rw0_wmask_in[184]
  PIN rw0_wmask_in[185]
    DIRECTION INPUT ;
    USE SIGNAL ;
    SHAPE ABUTMENT ;
    PORT
      LAYER M3 ;
      RECT 14.571 90.234 14.589 90.288 ;
    END
  END rw0_wmask_in[185]
  PIN rw0_wmask_in[186]
    DIRECTION INPUT ;
    USE SIGNAL ;
    SHAPE ABUTMENT ;
    PORT
      LAYER M3 ;
      RECT 14.823 90.234 14.841 90.288 ;
    END
  END rw0_wmask_in[186]
  PIN rw0_wmask_in[187]
    DIRECTION INPUT ;
    USE SIGNAL ;
    SHAPE ABUTMENT ;
    PORT
      LAYER M3 ;
      RECT 15.075 90.234 15.093 90.288 ;
    END
  END rw0_wmask_in[187]
  PIN rw0_wmask_in[188]
    DIRECTION INPUT ;
    USE SIGNAL ;
    SHAPE ABUTMENT ;
    PORT
      LAYER M3 ;
      RECT 15.327 90.234 15.345 90.288 ;
    END
  END rw0_wmask_in[188]
  PIN rw0_wmask_in[189]
    DIRECTION INPUT ;
    USE SIGNAL ;
    SHAPE ABUTMENT ;
    PORT
      LAYER M3 ;
      RECT 15.579 90.234 15.597 90.288 ;
    END
  END rw0_wmask_in[189]
  PIN rw0_wmask_in[190]
    DIRECTION INPUT ;
    USE SIGNAL ;
    SHAPE ABUTMENT ;
    PORT
      LAYER M3 ;
      RECT 15.831 90.234 15.849 90.288 ;
    END
  END rw0_wmask_in[190]
  PIN rw0_wmask_in[191]
    DIRECTION INPUT ;
    USE SIGNAL ;
    SHAPE ABUTMENT ;
    PORT
      LAYER M3 ;
      RECT 16.083 90.234 16.101 90.288 ;
    END
  END rw0_wmask_in[191]
  PIN rw0_wmask_in[192]
    DIRECTION INPUT ;
    USE SIGNAL ;
    SHAPE ABUTMENT ;
    PORT
      LAYER M3 ;
      RECT 16.335 90.234 16.353 90.288 ;
    END
  END rw0_wmask_in[192]
  PIN rw0_wmask_in[193]
    DIRECTION INPUT ;
    USE SIGNAL ;
    SHAPE ABUTMENT ;
    PORT
      LAYER M3 ;
      RECT 16.587 90.234 16.605 90.288 ;
    END
  END rw0_wmask_in[193]
  PIN rw0_wmask_in[194]
    DIRECTION INPUT ;
    USE SIGNAL ;
    SHAPE ABUTMENT ;
    PORT
      LAYER M3 ;
      RECT 16.839 90.234 16.857 90.288 ;
    END
  END rw0_wmask_in[194]
  PIN rw0_wmask_in[195]
    DIRECTION INPUT ;
    USE SIGNAL ;
    SHAPE ABUTMENT ;
    PORT
      LAYER M3 ;
      RECT 17.091 90.234 17.109 90.288 ;
    END
  END rw0_wmask_in[195]
  PIN rw0_wmask_in[196]
    DIRECTION INPUT ;
    USE SIGNAL ;
    SHAPE ABUTMENT ;
    PORT
      LAYER M3 ;
      RECT 17.343 90.234 17.361 90.288 ;
    END
  END rw0_wmask_in[196]
  PIN rw0_wmask_in[197]
    DIRECTION INPUT ;
    USE SIGNAL ;
    SHAPE ABUTMENT ;
    PORT
      LAYER M3 ;
      RECT 17.595 90.234 17.613 90.288 ;
    END
  END rw0_wmask_in[197]
  PIN rw0_wmask_in[198]
    DIRECTION INPUT ;
    USE SIGNAL ;
    SHAPE ABUTMENT ;
    PORT
      LAYER M3 ;
      RECT 17.847 90.234 17.865 90.288 ;
    END
  END rw0_wmask_in[198]
  PIN rw0_wmask_in[199]
    DIRECTION INPUT ;
    USE SIGNAL ;
    SHAPE ABUTMENT ;
    PORT
      LAYER M3 ;
      RECT 18.099 90.234 18.117 90.288 ;
    END
  END rw0_wmask_in[199]
  PIN rw0_wmask_in[200]
    DIRECTION INPUT ;
    USE SIGNAL ;
    SHAPE ABUTMENT ;
    PORT
      LAYER M3 ;
      RECT 18.351 90.234 18.369 90.288 ;
    END
  END rw0_wmask_in[200]
  PIN rw0_wmask_in[201]
    DIRECTION INPUT ;
    USE SIGNAL ;
    SHAPE ABUTMENT ;
    PORT
      LAYER M3 ;
      RECT 18.603 90.234 18.621 90.288 ;
    END
  END rw0_wmask_in[201]
  PIN rw0_wmask_in[202]
    DIRECTION INPUT ;
    USE SIGNAL ;
    SHAPE ABUTMENT ;
    PORT
      LAYER M3 ;
      RECT 18.855 90.234 18.873 90.288 ;
    END
  END rw0_wmask_in[202]
  PIN rw0_wmask_in[203]
    DIRECTION INPUT ;
    USE SIGNAL ;
    SHAPE ABUTMENT ;
    PORT
      LAYER M3 ;
      RECT 19.107 90.234 19.125 90.288 ;
    END
  END rw0_wmask_in[203]
  PIN rw0_wmask_in[204]
    DIRECTION INPUT ;
    USE SIGNAL ;
    SHAPE ABUTMENT ;
    PORT
      LAYER M3 ;
      RECT 19.359 90.234 19.377 90.288 ;
    END
  END rw0_wmask_in[204]
  PIN rw0_wmask_in[205]
    DIRECTION INPUT ;
    USE SIGNAL ;
    SHAPE ABUTMENT ;
    PORT
      LAYER M3 ;
      RECT 19.611 90.234 19.629 90.288 ;
    END
  END rw0_wmask_in[205]
  PIN rw0_wmask_in[206]
    DIRECTION INPUT ;
    USE SIGNAL ;
    SHAPE ABUTMENT ;
    PORT
      LAYER M3 ;
      RECT 19.863 90.234 19.881 90.288 ;
    END
  END rw0_wmask_in[206]
  PIN rw0_wmask_in[207]
    DIRECTION INPUT ;
    USE SIGNAL ;
    SHAPE ABUTMENT ;
    PORT
      LAYER M3 ;
      RECT 20.115 90.234 20.133 90.288 ;
    END
  END rw0_wmask_in[207]
  PIN rw0_wmask_in[208]
    DIRECTION INPUT ;
    USE SIGNAL ;
    SHAPE ABUTMENT ;
    PORT
      LAYER M3 ;
      RECT 20.367 90.234 20.385 90.288 ;
    END
  END rw0_wmask_in[208]
  PIN rw0_wmask_in[209]
    DIRECTION INPUT ;
    USE SIGNAL ;
    SHAPE ABUTMENT ;
    PORT
      LAYER M3 ;
      RECT 20.619 90.234 20.637 90.288 ;
    END
  END rw0_wmask_in[209]
  PIN rw0_wmask_in[210]
    DIRECTION INPUT ;
    USE SIGNAL ;
    SHAPE ABUTMENT ;
    PORT
      LAYER M3 ;
      RECT 20.871 90.234 20.889 90.288 ;
    END
  END rw0_wmask_in[210]
  PIN rw0_wmask_in[211]
    DIRECTION INPUT ;
    USE SIGNAL ;
    SHAPE ABUTMENT ;
    PORT
      LAYER M3 ;
      RECT 21.123 90.234 21.141 90.288 ;
    END
  END rw0_wmask_in[211]
  PIN rw0_wmask_in[212]
    DIRECTION INPUT ;
    USE SIGNAL ;
    SHAPE ABUTMENT ;
    PORT
      LAYER M3 ;
      RECT 21.375 90.234 21.393 90.288 ;
    END
  END rw0_wmask_in[212]
  PIN rw0_wmask_in[213]
    DIRECTION INPUT ;
    USE SIGNAL ;
    SHAPE ABUTMENT ;
    PORT
      LAYER M3 ;
      RECT 21.627 90.234 21.645 90.288 ;
    END
  END rw0_wmask_in[213]
  PIN rw0_wmask_in[214]
    DIRECTION INPUT ;
    USE SIGNAL ;
    SHAPE ABUTMENT ;
    PORT
      LAYER M3 ;
      RECT 21.879 90.234 21.897 90.288 ;
    END
  END rw0_wmask_in[214]
  PIN rw0_wmask_in[215]
    DIRECTION INPUT ;
    USE SIGNAL ;
    SHAPE ABUTMENT ;
    PORT
      LAYER M3 ;
      RECT 22.131 90.234 22.149 90.288 ;
    END
  END rw0_wmask_in[215]
  PIN rw0_wmask_in[216]
    DIRECTION INPUT ;
    USE SIGNAL ;
    SHAPE ABUTMENT ;
    PORT
      LAYER M3 ;
      RECT 22.383 90.234 22.401 90.288 ;
    END
  END rw0_wmask_in[216]
  PIN rw0_wmask_in[217]
    DIRECTION INPUT ;
    USE SIGNAL ;
    SHAPE ABUTMENT ;
    PORT
      LAYER M3 ;
      RECT 22.635 90.234 22.653 90.288 ;
    END
  END rw0_wmask_in[217]
  PIN rw0_wmask_in[218]
    DIRECTION INPUT ;
    USE SIGNAL ;
    SHAPE ABUTMENT ;
    PORT
      LAYER M3 ;
      RECT 22.887 90.234 22.905 90.288 ;
    END
  END rw0_wmask_in[218]
  PIN rw0_wmask_in[219]
    DIRECTION INPUT ;
    USE SIGNAL ;
    SHAPE ABUTMENT ;
    PORT
      LAYER M3 ;
      RECT 23.139 90.234 23.157 90.288 ;
    END
  END rw0_wmask_in[219]
  PIN rw0_wmask_in[220]
    DIRECTION INPUT ;
    USE SIGNAL ;
    SHAPE ABUTMENT ;
    PORT
      LAYER M3 ;
      RECT 23.391 90.234 23.409 90.288 ;
    END
  END rw0_wmask_in[220]
  PIN rw0_wmask_in[221]
    DIRECTION INPUT ;
    USE SIGNAL ;
    SHAPE ABUTMENT ;
    PORT
      LAYER M3 ;
      RECT 23.643 90.234 23.661 90.288 ;
    END
  END rw0_wmask_in[221]
  PIN rw0_wmask_in[222]
    DIRECTION INPUT ;
    USE SIGNAL ;
    SHAPE ABUTMENT ;
    PORT
      LAYER M3 ;
      RECT 23.895 90.234 23.913 90.288 ;
    END
  END rw0_wmask_in[222]
  PIN rw0_wmask_in[223]
    DIRECTION INPUT ;
    USE SIGNAL ;
    SHAPE ABUTMENT ;
    PORT
      LAYER M3 ;
      RECT 24.147 90.234 24.165 90.288 ;
    END
  END rw0_wmask_in[223]
  PIN rw0_wmask_in[224]
    DIRECTION INPUT ;
    USE SIGNAL ;
    SHAPE ABUTMENT ;
    PORT
      LAYER M3 ;
      RECT 24.399 90.234 24.417 90.288 ;
    END
  END rw0_wmask_in[224]
  PIN rw0_wmask_in[225]
    DIRECTION INPUT ;
    USE SIGNAL ;
    SHAPE ABUTMENT ;
    PORT
      LAYER M3 ;
      RECT 24.651 90.234 24.669 90.288 ;
    END
  END rw0_wmask_in[225]
  PIN rw0_wmask_in[226]
    DIRECTION INPUT ;
    USE SIGNAL ;
    SHAPE ABUTMENT ;
    PORT
      LAYER M3 ;
      RECT 24.903 90.234 24.921 90.288 ;
    END
  END rw0_wmask_in[226]
  PIN rw0_wmask_in[227]
    DIRECTION INPUT ;
    USE SIGNAL ;
    SHAPE ABUTMENT ;
    PORT
      LAYER M3 ;
      RECT 25.155 90.234 25.173 90.288 ;
    END
  END rw0_wmask_in[227]
  PIN rw0_wmask_in[228]
    DIRECTION INPUT ;
    USE SIGNAL ;
    SHAPE ABUTMENT ;
    PORT
      LAYER M3 ;
      RECT 25.407 90.234 25.425 90.288 ;
    END
  END rw0_wmask_in[228]
  PIN rw0_wmask_in[229]
    DIRECTION INPUT ;
    USE SIGNAL ;
    SHAPE ABUTMENT ;
    PORT
      LAYER M3 ;
      RECT 25.659 90.234 25.677 90.288 ;
    END
  END rw0_wmask_in[229]
  PIN rw0_wmask_in[230]
    DIRECTION INPUT ;
    USE SIGNAL ;
    SHAPE ABUTMENT ;
    PORT
      LAYER M3 ;
      RECT 25.911 90.234 25.929 90.288 ;
    END
  END rw0_wmask_in[230]
  PIN rw0_wmask_in[231]
    DIRECTION INPUT ;
    USE SIGNAL ;
    SHAPE ABUTMENT ;
    PORT
      LAYER M3 ;
      RECT 26.163 90.234 26.181 90.288 ;
    END
  END rw0_wmask_in[231]
  PIN rw0_wmask_in[232]
    DIRECTION INPUT ;
    USE SIGNAL ;
    SHAPE ABUTMENT ;
    PORT
      LAYER M3 ;
      RECT 26.415 90.234 26.433 90.288 ;
    END
  END rw0_wmask_in[232]
  PIN rw0_wmask_in[233]
    DIRECTION INPUT ;
    USE SIGNAL ;
    SHAPE ABUTMENT ;
    PORT
      LAYER M3 ;
      RECT 26.667 90.234 26.685 90.288 ;
    END
  END rw0_wmask_in[233]
  PIN rw0_wmask_in[234]
    DIRECTION INPUT ;
    USE SIGNAL ;
    SHAPE ABUTMENT ;
    PORT
      LAYER M3 ;
      RECT 26.919 90.234 26.937 90.288 ;
    END
  END rw0_wmask_in[234]
  PIN rw0_wmask_in[235]
    DIRECTION INPUT ;
    USE SIGNAL ;
    SHAPE ABUTMENT ;
    PORT
      LAYER M3 ;
      RECT 27.171 90.234 27.189 90.288 ;
    END
  END rw0_wmask_in[235]
  PIN rw0_wmask_in[236]
    DIRECTION INPUT ;
    USE SIGNAL ;
    SHAPE ABUTMENT ;
    PORT
      LAYER M3 ;
      RECT 27.423 90.234 27.441 90.288 ;
    END
  END rw0_wmask_in[236]
  PIN rw0_wmask_in[237]
    DIRECTION INPUT ;
    USE SIGNAL ;
    SHAPE ABUTMENT ;
    PORT
      LAYER M3 ;
      RECT 27.675 90.234 27.693 90.288 ;
    END
  END rw0_wmask_in[237]
  PIN rw0_wmask_in[238]
    DIRECTION INPUT ;
    USE SIGNAL ;
    SHAPE ABUTMENT ;
    PORT
      LAYER M3 ;
      RECT 27.927 90.234 27.945 90.288 ;
    END
  END rw0_wmask_in[238]
  PIN rw0_wmask_in[239]
    DIRECTION INPUT ;
    USE SIGNAL ;
    SHAPE ABUTMENT ;
    PORT
      LAYER M3 ;
      RECT 28.179 90.234 28.197 90.288 ;
    END
  END rw0_wmask_in[239]
  PIN rw0_wmask_in[240]
    DIRECTION INPUT ;
    USE SIGNAL ;
    SHAPE ABUTMENT ;
    PORT
      LAYER M3 ;
      RECT 28.431 90.234 28.449 90.288 ;
    END
  END rw0_wmask_in[240]
  PIN rw0_wmask_in[241]
    DIRECTION INPUT ;
    USE SIGNAL ;
    SHAPE ABUTMENT ;
    PORT
      LAYER M3 ;
      RECT 28.683 90.234 28.701 90.288 ;
    END
  END rw0_wmask_in[241]
  PIN rw0_wmask_in[242]
    DIRECTION INPUT ;
    USE SIGNAL ;
    SHAPE ABUTMENT ;
    PORT
      LAYER M3 ;
      RECT 28.935 90.234 28.953 90.288 ;
    END
  END rw0_wmask_in[242]
  PIN rw0_wmask_in[243]
    DIRECTION INPUT ;
    USE SIGNAL ;
    SHAPE ABUTMENT ;
    PORT
      LAYER M3 ;
      RECT 29.187 90.234 29.205 90.288 ;
    END
  END rw0_wmask_in[243]
  PIN rw0_wmask_in[244]
    DIRECTION INPUT ;
    USE SIGNAL ;
    SHAPE ABUTMENT ;
    PORT
      LAYER M3 ;
      RECT 29.439 90.234 29.457 90.288 ;
    END
  END rw0_wmask_in[244]
  PIN rw0_wmask_in[245]
    DIRECTION INPUT ;
    USE SIGNAL ;
    SHAPE ABUTMENT ;
    PORT
      LAYER M3 ;
      RECT 29.691 90.234 29.709 90.288 ;
    END
  END rw0_wmask_in[245]
  PIN rw0_wmask_in[246]
    DIRECTION INPUT ;
    USE SIGNAL ;
    SHAPE ABUTMENT ;
    PORT
      LAYER M3 ;
      RECT 29.943 90.234 29.961 90.288 ;
    END
  END rw0_wmask_in[246]
  PIN rw0_wmask_in[247]
    DIRECTION INPUT ;
    USE SIGNAL ;
    SHAPE ABUTMENT ;
    PORT
      LAYER M3 ;
      RECT 30.195 90.234 30.213 90.288 ;
    END
  END rw0_wmask_in[247]
  PIN rw0_wmask_in[248]
    DIRECTION INPUT ;
    USE SIGNAL ;
    SHAPE ABUTMENT ;
    PORT
      LAYER M3 ;
      RECT 30.447 90.234 30.465 90.288 ;
    END
  END rw0_wmask_in[248]
  PIN rw0_wmask_in[249]
    DIRECTION INPUT ;
    USE SIGNAL ;
    SHAPE ABUTMENT ;
    PORT
      LAYER M3 ;
      RECT 30.699 90.234 30.717 90.288 ;
    END
  END rw0_wmask_in[249]
  PIN rw0_wmask_in[250]
    DIRECTION INPUT ;
    USE SIGNAL ;
    SHAPE ABUTMENT ;
    PORT
      LAYER M3 ;
      RECT 30.951 90.234 30.969 90.288 ;
    END
  END rw0_wmask_in[250]
  PIN rw0_wmask_in[251]
    DIRECTION INPUT ;
    USE SIGNAL ;
    SHAPE ABUTMENT ;
    PORT
      LAYER M3 ;
      RECT 31.203 90.234 31.221 90.288 ;
    END
  END rw0_wmask_in[251]
  PIN rw0_wmask_in[252]
    DIRECTION INPUT ;
    USE SIGNAL ;
    SHAPE ABUTMENT ;
    PORT
      LAYER M3 ;
      RECT 31.455 90.234 31.473 90.288 ;
    END
  END rw0_wmask_in[252]
  PIN rw0_wmask_in[253]
    DIRECTION INPUT ;
    USE SIGNAL ;
    SHAPE ABUTMENT ;
    PORT
      LAYER M3 ;
      RECT 31.707 90.234 31.725 90.288 ;
    END
  END rw0_wmask_in[253]
  PIN rw0_wmask_in[254]
    DIRECTION INPUT ;
    USE SIGNAL ;
    SHAPE ABUTMENT ;
    PORT
      LAYER M3 ;
      RECT 31.959 90.234 31.977 90.288 ;
    END
  END rw0_wmask_in[254]
  PIN rw0_wmask_in[255]
    DIRECTION INPUT ;
    USE SIGNAL ;
    SHAPE ABUTMENT ;
    PORT
      LAYER M3 ;
      RECT 32.211 90.234 32.229 90.288 ;
    END
  END rw0_wmask_in[255]
  PIN rw0_wd_in[0]
    DIRECTION INPUT ;
    USE SIGNAL ;
    SHAPE ABUTMENT ;
    PORT
      LAYER M4 ;
      RECT 0.000 43.284 0.072 43.308 ;
    END
  END rw0_wd_in[0]
  PIN rw0_wd_in[1]
    DIRECTION INPUT ;
    USE SIGNAL ;
    SHAPE ABUTMENT ;
    PORT
      LAYER M4 ;
      RECT 0.000 43.956 0.072 43.980 ;
    END
  END rw0_wd_in[1]
  PIN rw0_wd_in[2]
    DIRECTION INPUT ;
    USE SIGNAL ;
    SHAPE ABUTMENT ;
    PORT
      LAYER M4 ;
      RECT 0.000 44.628 0.072 44.652 ;
    END
  END rw0_wd_in[2]
  PIN rw0_wd_in[3]
    DIRECTION INPUT ;
    USE SIGNAL ;
    SHAPE ABUTMENT ;
    PORT
      LAYER M4 ;
      RECT 0.000 45.300 0.072 45.324 ;
    END
  END rw0_wd_in[3]
  PIN rw0_wd_in[4]
    DIRECTION INPUT ;
    USE SIGNAL ;
    SHAPE ABUTMENT ;
    PORT
      LAYER M4 ;
      RECT 0.000 45.972 0.072 45.996 ;
    END
  END rw0_wd_in[4]
  PIN rw0_wd_in[5]
    DIRECTION INPUT ;
    USE SIGNAL ;
    SHAPE ABUTMENT ;
    PORT
      LAYER M4 ;
      RECT 0.000 46.644 0.072 46.668 ;
    END
  END rw0_wd_in[5]
  PIN rw0_wd_in[6]
    DIRECTION INPUT ;
    USE SIGNAL ;
    SHAPE ABUTMENT ;
    PORT
      LAYER M4 ;
      RECT 0.000 47.316 0.072 47.340 ;
    END
  END rw0_wd_in[6]
  PIN rw0_wd_in[7]
    DIRECTION INPUT ;
    USE SIGNAL ;
    SHAPE ABUTMENT ;
    PORT
      LAYER M4 ;
      RECT 0.000 47.988 0.072 48.012 ;
    END
  END rw0_wd_in[7]
  PIN rw0_wd_in[8]
    DIRECTION INPUT ;
    USE SIGNAL ;
    SHAPE ABUTMENT ;
    PORT
      LAYER M4 ;
      RECT 0.000 48.660 0.072 48.684 ;
    END
  END rw0_wd_in[8]
  PIN rw0_wd_in[9]
    DIRECTION INPUT ;
    USE SIGNAL ;
    SHAPE ABUTMENT ;
    PORT
      LAYER M4 ;
      RECT 0.000 49.332 0.072 49.356 ;
    END
  END rw0_wd_in[9]
  PIN rw0_wd_in[10]
    DIRECTION INPUT ;
    USE SIGNAL ;
    SHAPE ABUTMENT ;
    PORT
      LAYER M4 ;
      RECT 0.000 50.004 0.072 50.028 ;
    END
  END rw0_wd_in[10]
  PIN rw0_wd_in[11]
    DIRECTION INPUT ;
    USE SIGNAL ;
    SHAPE ABUTMENT ;
    PORT
      LAYER M4 ;
      RECT 0.000 50.676 0.072 50.700 ;
    END
  END rw0_wd_in[11]
  PIN rw0_wd_in[12]
    DIRECTION INPUT ;
    USE SIGNAL ;
    SHAPE ABUTMENT ;
    PORT
      LAYER M4 ;
      RECT 0.000 51.348 0.072 51.372 ;
    END
  END rw0_wd_in[12]
  PIN rw0_wd_in[13]
    DIRECTION INPUT ;
    USE SIGNAL ;
    SHAPE ABUTMENT ;
    PORT
      LAYER M4 ;
      RECT 0.000 52.020 0.072 52.044 ;
    END
  END rw0_wd_in[13]
  PIN rw0_wd_in[14]
    DIRECTION INPUT ;
    USE SIGNAL ;
    SHAPE ABUTMENT ;
    PORT
      LAYER M4 ;
      RECT 0.000 52.692 0.072 52.716 ;
    END
  END rw0_wd_in[14]
  PIN rw0_wd_in[15]
    DIRECTION INPUT ;
    USE SIGNAL ;
    SHAPE ABUTMENT ;
    PORT
      LAYER M4 ;
      RECT 0.000 53.364 0.072 53.388 ;
    END
  END rw0_wd_in[15]
  PIN rw0_wd_in[16]
    DIRECTION INPUT ;
    USE SIGNAL ;
    SHAPE ABUTMENT ;
    PORT
      LAYER M4 ;
      RECT 0.000 54.036 0.072 54.060 ;
    END
  END rw0_wd_in[16]
  PIN rw0_wd_in[17]
    DIRECTION INPUT ;
    USE SIGNAL ;
    SHAPE ABUTMENT ;
    PORT
      LAYER M4 ;
      RECT 0.000 54.708 0.072 54.732 ;
    END
  END rw0_wd_in[17]
  PIN rw0_wd_in[18]
    DIRECTION INPUT ;
    USE SIGNAL ;
    SHAPE ABUTMENT ;
    PORT
      LAYER M4 ;
      RECT 0.000 55.380 0.072 55.404 ;
    END
  END rw0_wd_in[18]
  PIN rw0_wd_in[19]
    DIRECTION INPUT ;
    USE SIGNAL ;
    SHAPE ABUTMENT ;
    PORT
      LAYER M4 ;
      RECT 0.000 56.052 0.072 56.076 ;
    END
  END rw0_wd_in[19]
  PIN rw0_wd_in[20]
    DIRECTION INPUT ;
    USE SIGNAL ;
    SHAPE ABUTMENT ;
    PORT
      LAYER M4 ;
      RECT 0.000 56.724 0.072 56.748 ;
    END
  END rw0_wd_in[20]
  PIN rw0_wd_in[21]
    DIRECTION INPUT ;
    USE SIGNAL ;
    SHAPE ABUTMENT ;
    PORT
      LAYER M4 ;
      RECT 0.000 57.396 0.072 57.420 ;
    END
  END rw0_wd_in[21]
  PIN rw0_wd_in[22]
    DIRECTION INPUT ;
    USE SIGNAL ;
    SHAPE ABUTMENT ;
    PORT
      LAYER M4 ;
      RECT 0.000 58.068 0.072 58.092 ;
    END
  END rw0_wd_in[22]
  PIN rw0_wd_in[23]
    DIRECTION INPUT ;
    USE SIGNAL ;
    SHAPE ABUTMENT ;
    PORT
      LAYER M4 ;
      RECT 0.000 58.740 0.072 58.764 ;
    END
  END rw0_wd_in[23]
  PIN rw0_wd_in[24]
    DIRECTION INPUT ;
    USE SIGNAL ;
    SHAPE ABUTMENT ;
    PORT
      LAYER M4 ;
      RECT 0.000 59.412 0.072 59.436 ;
    END
  END rw0_wd_in[24]
  PIN rw0_wd_in[25]
    DIRECTION INPUT ;
    USE SIGNAL ;
    SHAPE ABUTMENT ;
    PORT
      LAYER M4 ;
      RECT 0.000 60.084 0.072 60.108 ;
    END
  END rw0_wd_in[25]
  PIN rw0_wd_in[26]
    DIRECTION INPUT ;
    USE SIGNAL ;
    SHAPE ABUTMENT ;
    PORT
      LAYER M4 ;
      RECT 0.000 60.756 0.072 60.780 ;
    END
  END rw0_wd_in[26]
  PIN rw0_wd_in[27]
    DIRECTION INPUT ;
    USE SIGNAL ;
    SHAPE ABUTMENT ;
    PORT
      LAYER M4 ;
      RECT 0.000 61.428 0.072 61.452 ;
    END
  END rw0_wd_in[27]
  PIN rw0_wd_in[28]
    DIRECTION INPUT ;
    USE SIGNAL ;
    SHAPE ABUTMENT ;
    PORT
      LAYER M4 ;
      RECT 0.000 62.100 0.072 62.124 ;
    END
  END rw0_wd_in[28]
  PIN rw0_wd_in[29]
    DIRECTION INPUT ;
    USE SIGNAL ;
    SHAPE ABUTMENT ;
    PORT
      LAYER M4 ;
      RECT 0.000 62.772 0.072 62.796 ;
    END
  END rw0_wd_in[29]
  PIN rw0_wd_in[30]
    DIRECTION INPUT ;
    USE SIGNAL ;
    SHAPE ABUTMENT ;
    PORT
      LAYER M4 ;
      RECT 0.000 63.444 0.072 63.468 ;
    END
  END rw0_wd_in[30]
  PIN rw0_wd_in[31]
    DIRECTION INPUT ;
    USE SIGNAL ;
    SHAPE ABUTMENT ;
    PORT
      LAYER M4 ;
      RECT 0.000 64.116 0.072 64.140 ;
    END
  END rw0_wd_in[31]
  PIN rw0_wd_in[32]
    DIRECTION INPUT ;
    USE SIGNAL ;
    SHAPE ABUTMENT ;
    PORT
      LAYER M4 ;
      RECT 0.000 64.788 0.072 64.812 ;
    END
  END rw0_wd_in[32]
  PIN rw0_wd_in[33]
    DIRECTION INPUT ;
    USE SIGNAL ;
    SHAPE ABUTMENT ;
    PORT
      LAYER M4 ;
      RECT 0.000 65.460 0.072 65.484 ;
    END
  END rw0_wd_in[33]
  PIN rw0_wd_in[34]
    DIRECTION INPUT ;
    USE SIGNAL ;
    SHAPE ABUTMENT ;
    PORT
      LAYER M4 ;
      RECT 0.000 66.132 0.072 66.156 ;
    END
  END rw0_wd_in[34]
  PIN rw0_wd_in[35]
    DIRECTION INPUT ;
    USE SIGNAL ;
    SHAPE ABUTMENT ;
    PORT
      LAYER M4 ;
      RECT 0.000 66.804 0.072 66.828 ;
    END
  END rw0_wd_in[35]
  PIN rw0_wd_in[36]
    DIRECTION INPUT ;
    USE SIGNAL ;
    SHAPE ABUTMENT ;
    PORT
      LAYER M4 ;
      RECT 0.000 67.476 0.072 67.500 ;
    END
  END rw0_wd_in[36]
  PIN rw0_wd_in[37]
    DIRECTION INPUT ;
    USE SIGNAL ;
    SHAPE ABUTMENT ;
    PORT
      LAYER M4 ;
      RECT 0.000 68.148 0.072 68.172 ;
    END
  END rw0_wd_in[37]
  PIN rw0_wd_in[38]
    DIRECTION INPUT ;
    USE SIGNAL ;
    SHAPE ABUTMENT ;
    PORT
      LAYER M4 ;
      RECT 0.000 68.820 0.072 68.844 ;
    END
  END rw0_wd_in[38]
  PIN rw0_wd_in[39]
    DIRECTION INPUT ;
    USE SIGNAL ;
    SHAPE ABUTMENT ;
    PORT
      LAYER M4 ;
      RECT 0.000 69.492 0.072 69.516 ;
    END
  END rw0_wd_in[39]
  PIN rw0_wd_in[40]
    DIRECTION INPUT ;
    USE SIGNAL ;
    SHAPE ABUTMENT ;
    PORT
      LAYER M4 ;
      RECT 0.000 70.164 0.072 70.188 ;
    END
  END rw0_wd_in[40]
  PIN rw0_wd_in[41]
    DIRECTION INPUT ;
    USE SIGNAL ;
    SHAPE ABUTMENT ;
    PORT
      LAYER M4 ;
      RECT 0.000 70.836 0.072 70.860 ;
    END
  END rw0_wd_in[41]
  PIN rw0_wd_in[42]
    DIRECTION INPUT ;
    USE SIGNAL ;
    SHAPE ABUTMENT ;
    PORT
      LAYER M4 ;
      RECT 0.000 71.508 0.072 71.532 ;
    END
  END rw0_wd_in[42]
  PIN rw0_wd_in[43]
    DIRECTION INPUT ;
    USE SIGNAL ;
    SHAPE ABUTMENT ;
    PORT
      LAYER M4 ;
      RECT 0.000 72.180 0.072 72.204 ;
    END
  END rw0_wd_in[43]
  PIN rw0_wd_in[44]
    DIRECTION INPUT ;
    USE SIGNAL ;
    SHAPE ABUTMENT ;
    PORT
      LAYER M4 ;
      RECT 0.000 72.852 0.072 72.876 ;
    END
  END rw0_wd_in[44]
  PIN rw0_wd_in[45]
    DIRECTION INPUT ;
    USE SIGNAL ;
    SHAPE ABUTMENT ;
    PORT
      LAYER M4 ;
      RECT 0.000 73.524 0.072 73.548 ;
    END
  END rw0_wd_in[45]
  PIN rw0_wd_in[46]
    DIRECTION INPUT ;
    USE SIGNAL ;
    SHAPE ABUTMENT ;
    PORT
      LAYER M4 ;
      RECT 0.000 74.196 0.072 74.220 ;
    END
  END rw0_wd_in[46]
  PIN rw0_wd_in[47]
    DIRECTION INPUT ;
    USE SIGNAL ;
    SHAPE ABUTMENT ;
    PORT
      LAYER M4 ;
      RECT 0.000 74.868 0.072 74.892 ;
    END
  END rw0_wd_in[47]
  PIN rw0_wd_in[48]
    DIRECTION INPUT ;
    USE SIGNAL ;
    SHAPE ABUTMENT ;
    PORT
      LAYER M4 ;
      RECT 0.000 75.540 0.072 75.564 ;
    END
  END rw0_wd_in[48]
  PIN rw0_wd_in[49]
    DIRECTION INPUT ;
    USE SIGNAL ;
    SHAPE ABUTMENT ;
    PORT
      LAYER M4 ;
      RECT 0.000 76.212 0.072 76.236 ;
    END
  END rw0_wd_in[49]
  PIN rw0_wd_in[50]
    DIRECTION INPUT ;
    USE SIGNAL ;
    SHAPE ABUTMENT ;
    PORT
      LAYER M4 ;
      RECT 0.000 76.884 0.072 76.908 ;
    END
  END rw0_wd_in[50]
  PIN rw0_wd_in[51]
    DIRECTION INPUT ;
    USE SIGNAL ;
    SHAPE ABUTMENT ;
    PORT
      LAYER M4 ;
      RECT 0.000 77.556 0.072 77.580 ;
    END
  END rw0_wd_in[51]
  PIN rw0_wd_in[52]
    DIRECTION INPUT ;
    USE SIGNAL ;
    SHAPE ABUTMENT ;
    PORT
      LAYER M4 ;
      RECT 0.000 78.228 0.072 78.252 ;
    END
  END rw0_wd_in[52]
  PIN rw0_wd_in[53]
    DIRECTION INPUT ;
    USE SIGNAL ;
    SHAPE ABUTMENT ;
    PORT
      LAYER M4 ;
      RECT 0.000 78.900 0.072 78.924 ;
    END
  END rw0_wd_in[53]
  PIN rw0_wd_in[54]
    DIRECTION INPUT ;
    USE SIGNAL ;
    SHAPE ABUTMENT ;
    PORT
      LAYER M4 ;
      RECT 0.000 79.572 0.072 79.596 ;
    END
  END rw0_wd_in[54]
  PIN rw0_wd_in[55]
    DIRECTION INPUT ;
    USE SIGNAL ;
    SHAPE ABUTMENT ;
    PORT
      LAYER M4 ;
      RECT 0.000 80.244 0.072 80.268 ;
    END
  END rw0_wd_in[55]
  PIN rw0_wd_in[56]
    DIRECTION INPUT ;
    USE SIGNAL ;
    SHAPE ABUTMENT ;
    PORT
      LAYER M4 ;
      RECT 0.000 80.916 0.072 80.940 ;
    END
  END rw0_wd_in[56]
  PIN rw0_wd_in[57]
    DIRECTION INPUT ;
    USE SIGNAL ;
    SHAPE ABUTMENT ;
    PORT
      LAYER M4 ;
      RECT 0.000 81.588 0.072 81.612 ;
    END
  END rw0_wd_in[57]
  PIN rw0_wd_in[58]
    DIRECTION INPUT ;
    USE SIGNAL ;
    SHAPE ABUTMENT ;
    PORT
      LAYER M4 ;
      RECT 0.000 82.260 0.072 82.284 ;
    END
  END rw0_wd_in[58]
  PIN rw0_wd_in[59]
    DIRECTION INPUT ;
    USE SIGNAL ;
    SHAPE ABUTMENT ;
    PORT
      LAYER M4 ;
      RECT 0.000 82.932 0.072 82.956 ;
    END
  END rw0_wd_in[59]
  PIN rw0_wd_in[60]
    DIRECTION INPUT ;
    USE SIGNAL ;
    SHAPE ABUTMENT ;
    PORT
      LAYER M4 ;
      RECT 0.000 83.604 0.072 83.628 ;
    END
  END rw0_wd_in[60]
  PIN rw0_wd_in[61]
    DIRECTION INPUT ;
    USE SIGNAL ;
    SHAPE ABUTMENT ;
    PORT
      LAYER M4 ;
      RECT 0.000 84.276 0.072 84.300 ;
    END
  END rw0_wd_in[61]
  PIN rw0_wd_in[62]
    DIRECTION INPUT ;
    USE SIGNAL ;
    SHAPE ABUTMENT ;
    PORT
      LAYER M4 ;
      RECT 0.000 84.948 0.072 84.972 ;
    END
  END rw0_wd_in[62]
  PIN rw0_wd_in[63]
    DIRECTION INPUT ;
    USE SIGNAL ;
    SHAPE ABUTMENT ;
    PORT
      LAYER M4 ;
      RECT 0.000 85.620 0.072 85.644 ;
    END
  END rw0_wd_in[63]
  PIN rw0_wd_in[64]
    DIRECTION INPUT ;
    USE SIGNAL ;
    SHAPE ABUTMENT ;
    PORT
      LAYER M4 ;
      RECT 72.159 43.284 72.231 43.308 ;
    END
  END rw0_wd_in[64]
  PIN rw0_wd_in[65]
    DIRECTION INPUT ;
    USE SIGNAL ;
    SHAPE ABUTMENT ;
    PORT
      LAYER M4 ;
      RECT 72.159 43.956 72.231 43.980 ;
    END
  END rw0_wd_in[65]
  PIN rw0_wd_in[66]
    DIRECTION INPUT ;
    USE SIGNAL ;
    SHAPE ABUTMENT ;
    PORT
      LAYER M4 ;
      RECT 72.159 44.628 72.231 44.652 ;
    END
  END rw0_wd_in[66]
  PIN rw0_wd_in[67]
    DIRECTION INPUT ;
    USE SIGNAL ;
    SHAPE ABUTMENT ;
    PORT
      LAYER M4 ;
      RECT 72.159 45.300 72.231 45.324 ;
    END
  END rw0_wd_in[67]
  PIN rw0_wd_in[68]
    DIRECTION INPUT ;
    USE SIGNAL ;
    SHAPE ABUTMENT ;
    PORT
      LAYER M4 ;
      RECT 72.159 45.972 72.231 45.996 ;
    END
  END rw0_wd_in[68]
  PIN rw0_wd_in[69]
    DIRECTION INPUT ;
    USE SIGNAL ;
    SHAPE ABUTMENT ;
    PORT
      LAYER M4 ;
      RECT 72.159 46.644 72.231 46.668 ;
    END
  END rw0_wd_in[69]
  PIN rw0_wd_in[70]
    DIRECTION INPUT ;
    USE SIGNAL ;
    SHAPE ABUTMENT ;
    PORT
      LAYER M4 ;
      RECT 72.159 47.316 72.231 47.340 ;
    END
  END rw0_wd_in[70]
  PIN rw0_wd_in[71]
    DIRECTION INPUT ;
    USE SIGNAL ;
    SHAPE ABUTMENT ;
    PORT
      LAYER M4 ;
      RECT 72.159 47.988 72.231 48.012 ;
    END
  END rw0_wd_in[71]
  PIN rw0_wd_in[72]
    DIRECTION INPUT ;
    USE SIGNAL ;
    SHAPE ABUTMENT ;
    PORT
      LAYER M4 ;
      RECT 72.159 48.660 72.231 48.684 ;
    END
  END rw0_wd_in[72]
  PIN rw0_wd_in[73]
    DIRECTION INPUT ;
    USE SIGNAL ;
    SHAPE ABUTMENT ;
    PORT
      LAYER M4 ;
      RECT 72.159 49.332 72.231 49.356 ;
    END
  END rw0_wd_in[73]
  PIN rw0_wd_in[74]
    DIRECTION INPUT ;
    USE SIGNAL ;
    SHAPE ABUTMENT ;
    PORT
      LAYER M4 ;
      RECT 72.159 50.004 72.231 50.028 ;
    END
  END rw0_wd_in[74]
  PIN rw0_wd_in[75]
    DIRECTION INPUT ;
    USE SIGNAL ;
    SHAPE ABUTMENT ;
    PORT
      LAYER M4 ;
      RECT 72.159 50.676 72.231 50.700 ;
    END
  END rw0_wd_in[75]
  PIN rw0_wd_in[76]
    DIRECTION INPUT ;
    USE SIGNAL ;
    SHAPE ABUTMENT ;
    PORT
      LAYER M4 ;
      RECT 72.159 51.348 72.231 51.372 ;
    END
  END rw0_wd_in[76]
  PIN rw0_wd_in[77]
    DIRECTION INPUT ;
    USE SIGNAL ;
    SHAPE ABUTMENT ;
    PORT
      LAYER M4 ;
      RECT 72.159 52.020 72.231 52.044 ;
    END
  END rw0_wd_in[77]
  PIN rw0_wd_in[78]
    DIRECTION INPUT ;
    USE SIGNAL ;
    SHAPE ABUTMENT ;
    PORT
      LAYER M4 ;
      RECT 72.159 52.692 72.231 52.716 ;
    END
  END rw0_wd_in[78]
  PIN rw0_wd_in[79]
    DIRECTION INPUT ;
    USE SIGNAL ;
    SHAPE ABUTMENT ;
    PORT
      LAYER M4 ;
      RECT 72.159 53.364 72.231 53.388 ;
    END
  END rw0_wd_in[79]
  PIN rw0_wd_in[80]
    DIRECTION INPUT ;
    USE SIGNAL ;
    SHAPE ABUTMENT ;
    PORT
      LAYER M4 ;
      RECT 72.159 54.036 72.231 54.060 ;
    END
  END rw0_wd_in[80]
  PIN rw0_wd_in[81]
    DIRECTION INPUT ;
    USE SIGNAL ;
    SHAPE ABUTMENT ;
    PORT
      LAYER M4 ;
      RECT 72.159 54.708 72.231 54.732 ;
    END
  END rw0_wd_in[81]
  PIN rw0_wd_in[82]
    DIRECTION INPUT ;
    USE SIGNAL ;
    SHAPE ABUTMENT ;
    PORT
      LAYER M4 ;
      RECT 72.159 55.380 72.231 55.404 ;
    END
  END rw0_wd_in[82]
  PIN rw0_wd_in[83]
    DIRECTION INPUT ;
    USE SIGNAL ;
    SHAPE ABUTMENT ;
    PORT
      LAYER M4 ;
      RECT 72.159 56.052 72.231 56.076 ;
    END
  END rw0_wd_in[83]
  PIN rw0_wd_in[84]
    DIRECTION INPUT ;
    USE SIGNAL ;
    SHAPE ABUTMENT ;
    PORT
      LAYER M4 ;
      RECT 72.159 56.724 72.231 56.748 ;
    END
  END rw0_wd_in[84]
  PIN rw0_wd_in[85]
    DIRECTION INPUT ;
    USE SIGNAL ;
    SHAPE ABUTMENT ;
    PORT
      LAYER M4 ;
      RECT 72.159 57.396 72.231 57.420 ;
    END
  END rw0_wd_in[85]
  PIN rw0_wd_in[86]
    DIRECTION INPUT ;
    USE SIGNAL ;
    SHAPE ABUTMENT ;
    PORT
      LAYER M4 ;
      RECT 72.159 58.068 72.231 58.092 ;
    END
  END rw0_wd_in[86]
  PIN rw0_wd_in[87]
    DIRECTION INPUT ;
    USE SIGNAL ;
    SHAPE ABUTMENT ;
    PORT
      LAYER M4 ;
      RECT 72.159 58.740 72.231 58.764 ;
    END
  END rw0_wd_in[87]
  PIN rw0_wd_in[88]
    DIRECTION INPUT ;
    USE SIGNAL ;
    SHAPE ABUTMENT ;
    PORT
      LAYER M4 ;
      RECT 72.159 59.412 72.231 59.436 ;
    END
  END rw0_wd_in[88]
  PIN rw0_wd_in[89]
    DIRECTION INPUT ;
    USE SIGNAL ;
    SHAPE ABUTMENT ;
    PORT
      LAYER M4 ;
      RECT 72.159 60.084 72.231 60.108 ;
    END
  END rw0_wd_in[89]
  PIN rw0_wd_in[90]
    DIRECTION INPUT ;
    USE SIGNAL ;
    SHAPE ABUTMENT ;
    PORT
      LAYER M4 ;
      RECT 72.159 60.756 72.231 60.780 ;
    END
  END rw0_wd_in[90]
  PIN rw0_wd_in[91]
    DIRECTION INPUT ;
    USE SIGNAL ;
    SHAPE ABUTMENT ;
    PORT
      LAYER M4 ;
      RECT 72.159 61.428 72.231 61.452 ;
    END
  END rw0_wd_in[91]
  PIN rw0_wd_in[92]
    DIRECTION INPUT ;
    USE SIGNAL ;
    SHAPE ABUTMENT ;
    PORT
      LAYER M4 ;
      RECT 72.159 62.100 72.231 62.124 ;
    END
  END rw0_wd_in[92]
  PIN rw0_wd_in[93]
    DIRECTION INPUT ;
    USE SIGNAL ;
    SHAPE ABUTMENT ;
    PORT
      LAYER M4 ;
      RECT 72.159 62.772 72.231 62.796 ;
    END
  END rw0_wd_in[93]
  PIN rw0_wd_in[94]
    DIRECTION INPUT ;
    USE SIGNAL ;
    SHAPE ABUTMENT ;
    PORT
      LAYER M4 ;
      RECT 72.159 63.444 72.231 63.468 ;
    END
  END rw0_wd_in[94]
  PIN rw0_wd_in[95]
    DIRECTION INPUT ;
    USE SIGNAL ;
    SHAPE ABUTMENT ;
    PORT
      LAYER M4 ;
      RECT 72.159 64.116 72.231 64.140 ;
    END
  END rw0_wd_in[95]
  PIN rw0_wd_in[96]
    DIRECTION INPUT ;
    USE SIGNAL ;
    SHAPE ABUTMENT ;
    PORT
      LAYER M4 ;
      RECT 72.159 64.788 72.231 64.812 ;
    END
  END rw0_wd_in[96]
  PIN rw0_wd_in[97]
    DIRECTION INPUT ;
    USE SIGNAL ;
    SHAPE ABUTMENT ;
    PORT
      LAYER M4 ;
      RECT 72.159 65.460 72.231 65.484 ;
    END
  END rw0_wd_in[97]
  PIN rw0_wd_in[98]
    DIRECTION INPUT ;
    USE SIGNAL ;
    SHAPE ABUTMENT ;
    PORT
      LAYER M4 ;
      RECT 72.159 66.132 72.231 66.156 ;
    END
  END rw0_wd_in[98]
  PIN rw0_wd_in[99]
    DIRECTION INPUT ;
    USE SIGNAL ;
    SHAPE ABUTMENT ;
    PORT
      LAYER M4 ;
      RECT 72.159 66.804 72.231 66.828 ;
    END
  END rw0_wd_in[99]
  PIN rw0_wd_in[100]
    DIRECTION INPUT ;
    USE SIGNAL ;
    SHAPE ABUTMENT ;
    PORT
      LAYER M4 ;
      RECT 72.159 67.476 72.231 67.500 ;
    END
  END rw0_wd_in[100]
  PIN rw0_wd_in[101]
    DIRECTION INPUT ;
    USE SIGNAL ;
    SHAPE ABUTMENT ;
    PORT
      LAYER M4 ;
      RECT 72.159 68.148 72.231 68.172 ;
    END
  END rw0_wd_in[101]
  PIN rw0_wd_in[102]
    DIRECTION INPUT ;
    USE SIGNAL ;
    SHAPE ABUTMENT ;
    PORT
      LAYER M4 ;
      RECT 72.159 68.820 72.231 68.844 ;
    END
  END rw0_wd_in[102]
  PIN rw0_wd_in[103]
    DIRECTION INPUT ;
    USE SIGNAL ;
    SHAPE ABUTMENT ;
    PORT
      LAYER M4 ;
      RECT 72.159 69.492 72.231 69.516 ;
    END
  END rw0_wd_in[103]
  PIN rw0_wd_in[104]
    DIRECTION INPUT ;
    USE SIGNAL ;
    SHAPE ABUTMENT ;
    PORT
      LAYER M4 ;
      RECT 72.159 70.164 72.231 70.188 ;
    END
  END rw0_wd_in[104]
  PIN rw0_wd_in[105]
    DIRECTION INPUT ;
    USE SIGNAL ;
    SHAPE ABUTMENT ;
    PORT
      LAYER M4 ;
      RECT 72.159 70.836 72.231 70.860 ;
    END
  END rw0_wd_in[105]
  PIN rw0_wd_in[106]
    DIRECTION INPUT ;
    USE SIGNAL ;
    SHAPE ABUTMENT ;
    PORT
      LAYER M4 ;
      RECT 72.159 71.508 72.231 71.532 ;
    END
  END rw0_wd_in[106]
  PIN rw0_wd_in[107]
    DIRECTION INPUT ;
    USE SIGNAL ;
    SHAPE ABUTMENT ;
    PORT
      LAYER M4 ;
      RECT 72.159 72.180 72.231 72.204 ;
    END
  END rw0_wd_in[107]
  PIN rw0_wd_in[108]
    DIRECTION INPUT ;
    USE SIGNAL ;
    SHAPE ABUTMENT ;
    PORT
      LAYER M4 ;
      RECT 72.159 72.852 72.231 72.876 ;
    END
  END rw0_wd_in[108]
  PIN rw0_wd_in[109]
    DIRECTION INPUT ;
    USE SIGNAL ;
    SHAPE ABUTMENT ;
    PORT
      LAYER M4 ;
      RECT 72.159 73.524 72.231 73.548 ;
    END
  END rw0_wd_in[109]
  PIN rw0_wd_in[110]
    DIRECTION INPUT ;
    USE SIGNAL ;
    SHAPE ABUTMENT ;
    PORT
      LAYER M4 ;
      RECT 72.159 74.196 72.231 74.220 ;
    END
  END rw0_wd_in[110]
  PIN rw0_wd_in[111]
    DIRECTION INPUT ;
    USE SIGNAL ;
    SHAPE ABUTMENT ;
    PORT
      LAYER M4 ;
      RECT 72.159 74.868 72.231 74.892 ;
    END
  END rw0_wd_in[111]
  PIN rw0_wd_in[112]
    DIRECTION INPUT ;
    USE SIGNAL ;
    SHAPE ABUTMENT ;
    PORT
      LAYER M4 ;
      RECT 72.159 75.540 72.231 75.564 ;
    END
  END rw0_wd_in[112]
  PIN rw0_wd_in[113]
    DIRECTION INPUT ;
    USE SIGNAL ;
    SHAPE ABUTMENT ;
    PORT
      LAYER M4 ;
      RECT 72.159 76.212 72.231 76.236 ;
    END
  END rw0_wd_in[113]
  PIN rw0_wd_in[114]
    DIRECTION INPUT ;
    USE SIGNAL ;
    SHAPE ABUTMENT ;
    PORT
      LAYER M4 ;
      RECT 72.159 76.884 72.231 76.908 ;
    END
  END rw0_wd_in[114]
  PIN rw0_wd_in[115]
    DIRECTION INPUT ;
    USE SIGNAL ;
    SHAPE ABUTMENT ;
    PORT
      LAYER M4 ;
      RECT 72.159 77.556 72.231 77.580 ;
    END
  END rw0_wd_in[115]
  PIN rw0_wd_in[116]
    DIRECTION INPUT ;
    USE SIGNAL ;
    SHAPE ABUTMENT ;
    PORT
      LAYER M4 ;
      RECT 72.159 78.228 72.231 78.252 ;
    END
  END rw0_wd_in[116]
  PIN rw0_wd_in[117]
    DIRECTION INPUT ;
    USE SIGNAL ;
    SHAPE ABUTMENT ;
    PORT
      LAYER M4 ;
      RECT 72.159 78.900 72.231 78.924 ;
    END
  END rw0_wd_in[117]
  PIN rw0_wd_in[118]
    DIRECTION INPUT ;
    USE SIGNAL ;
    SHAPE ABUTMENT ;
    PORT
      LAYER M4 ;
      RECT 72.159 79.572 72.231 79.596 ;
    END
  END rw0_wd_in[118]
  PIN rw0_wd_in[119]
    DIRECTION INPUT ;
    USE SIGNAL ;
    SHAPE ABUTMENT ;
    PORT
      LAYER M4 ;
      RECT 72.159 80.244 72.231 80.268 ;
    END
  END rw0_wd_in[119]
  PIN rw0_wd_in[120]
    DIRECTION INPUT ;
    USE SIGNAL ;
    SHAPE ABUTMENT ;
    PORT
      LAYER M4 ;
      RECT 72.159 80.916 72.231 80.940 ;
    END
  END rw0_wd_in[120]
  PIN rw0_wd_in[121]
    DIRECTION INPUT ;
    USE SIGNAL ;
    SHAPE ABUTMENT ;
    PORT
      LAYER M4 ;
      RECT 72.159 81.588 72.231 81.612 ;
    END
  END rw0_wd_in[121]
  PIN rw0_wd_in[122]
    DIRECTION INPUT ;
    USE SIGNAL ;
    SHAPE ABUTMENT ;
    PORT
      LAYER M4 ;
      RECT 72.159 82.260 72.231 82.284 ;
    END
  END rw0_wd_in[122]
  PIN rw0_wd_in[123]
    DIRECTION INPUT ;
    USE SIGNAL ;
    SHAPE ABUTMENT ;
    PORT
      LAYER M4 ;
      RECT 72.159 82.932 72.231 82.956 ;
    END
  END rw0_wd_in[123]
  PIN rw0_wd_in[124]
    DIRECTION INPUT ;
    USE SIGNAL ;
    SHAPE ABUTMENT ;
    PORT
      LAYER M4 ;
      RECT 72.159 83.604 72.231 83.628 ;
    END
  END rw0_wd_in[124]
  PIN rw0_wd_in[125]
    DIRECTION INPUT ;
    USE SIGNAL ;
    SHAPE ABUTMENT ;
    PORT
      LAYER M4 ;
      RECT 72.159 84.276 72.231 84.300 ;
    END
  END rw0_wd_in[125]
  PIN rw0_wd_in[126]
    DIRECTION INPUT ;
    USE SIGNAL ;
    SHAPE ABUTMENT ;
    PORT
      LAYER M4 ;
      RECT 72.159 84.948 72.231 84.972 ;
    END
  END rw0_wd_in[126]
  PIN rw0_wd_in[127]
    DIRECTION INPUT ;
    USE SIGNAL ;
    SHAPE ABUTMENT ;
    PORT
      LAYER M4 ;
      RECT 72.159 85.620 72.231 85.644 ;
    END
  END rw0_wd_in[127]
  PIN rw0_wd_in[128]
    DIRECTION INPUT ;
    USE SIGNAL ;
    SHAPE ABUTMENT ;
    PORT
      LAYER M3 ;
      RECT 0.207 0.000 0.225 0.054 ;
    END
  END rw0_wd_in[128]
  PIN rw0_wd_in[129]
    DIRECTION INPUT ;
    USE SIGNAL ;
    SHAPE ABUTMENT ;
    PORT
      LAYER M3 ;
      RECT 0.459 0.000 0.477 0.054 ;
    END
  END rw0_wd_in[129]
  PIN rw0_wd_in[130]
    DIRECTION INPUT ;
    USE SIGNAL ;
    SHAPE ABUTMENT ;
    PORT
      LAYER M3 ;
      RECT 0.711 0.000 0.729 0.054 ;
    END
  END rw0_wd_in[130]
  PIN rw0_wd_in[131]
    DIRECTION INPUT ;
    USE SIGNAL ;
    SHAPE ABUTMENT ;
    PORT
      LAYER M3 ;
      RECT 0.963 0.000 0.981 0.054 ;
    END
  END rw0_wd_in[131]
  PIN rw0_wd_in[132]
    DIRECTION INPUT ;
    USE SIGNAL ;
    SHAPE ABUTMENT ;
    PORT
      LAYER M3 ;
      RECT 1.215 0.000 1.233 0.054 ;
    END
  END rw0_wd_in[132]
  PIN rw0_wd_in[133]
    DIRECTION INPUT ;
    USE SIGNAL ;
    SHAPE ABUTMENT ;
    PORT
      LAYER M3 ;
      RECT 1.467 0.000 1.485 0.054 ;
    END
  END rw0_wd_in[133]
  PIN rw0_wd_in[134]
    DIRECTION INPUT ;
    USE SIGNAL ;
    SHAPE ABUTMENT ;
    PORT
      LAYER M3 ;
      RECT 1.719 0.000 1.737 0.054 ;
    END
  END rw0_wd_in[134]
  PIN rw0_wd_in[135]
    DIRECTION INPUT ;
    USE SIGNAL ;
    SHAPE ABUTMENT ;
    PORT
      LAYER M3 ;
      RECT 1.971 0.000 1.989 0.054 ;
    END
  END rw0_wd_in[135]
  PIN rw0_wd_in[136]
    DIRECTION INPUT ;
    USE SIGNAL ;
    SHAPE ABUTMENT ;
    PORT
      LAYER M3 ;
      RECT 2.223 0.000 2.241 0.054 ;
    END
  END rw0_wd_in[136]
  PIN rw0_wd_in[137]
    DIRECTION INPUT ;
    USE SIGNAL ;
    SHAPE ABUTMENT ;
    PORT
      LAYER M3 ;
      RECT 2.475 0.000 2.493 0.054 ;
    END
  END rw0_wd_in[137]
  PIN rw0_wd_in[138]
    DIRECTION INPUT ;
    USE SIGNAL ;
    SHAPE ABUTMENT ;
    PORT
      LAYER M3 ;
      RECT 2.727 0.000 2.745 0.054 ;
    END
  END rw0_wd_in[138]
  PIN rw0_wd_in[139]
    DIRECTION INPUT ;
    USE SIGNAL ;
    SHAPE ABUTMENT ;
    PORT
      LAYER M3 ;
      RECT 2.979 0.000 2.997 0.054 ;
    END
  END rw0_wd_in[139]
  PIN rw0_wd_in[140]
    DIRECTION INPUT ;
    USE SIGNAL ;
    SHAPE ABUTMENT ;
    PORT
      LAYER M3 ;
      RECT 3.231 0.000 3.249 0.054 ;
    END
  END rw0_wd_in[140]
  PIN rw0_wd_in[141]
    DIRECTION INPUT ;
    USE SIGNAL ;
    SHAPE ABUTMENT ;
    PORT
      LAYER M3 ;
      RECT 3.483 0.000 3.501 0.054 ;
    END
  END rw0_wd_in[141]
  PIN rw0_wd_in[142]
    DIRECTION INPUT ;
    USE SIGNAL ;
    SHAPE ABUTMENT ;
    PORT
      LAYER M3 ;
      RECT 3.735 0.000 3.753 0.054 ;
    END
  END rw0_wd_in[142]
  PIN rw0_wd_in[143]
    DIRECTION INPUT ;
    USE SIGNAL ;
    SHAPE ABUTMENT ;
    PORT
      LAYER M3 ;
      RECT 3.987 0.000 4.005 0.054 ;
    END
  END rw0_wd_in[143]
  PIN rw0_wd_in[144]
    DIRECTION INPUT ;
    USE SIGNAL ;
    SHAPE ABUTMENT ;
    PORT
      LAYER M3 ;
      RECT 4.239 0.000 4.257 0.054 ;
    END
  END rw0_wd_in[144]
  PIN rw0_wd_in[145]
    DIRECTION INPUT ;
    USE SIGNAL ;
    SHAPE ABUTMENT ;
    PORT
      LAYER M3 ;
      RECT 4.491 0.000 4.509 0.054 ;
    END
  END rw0_wd_in[145]
  PIN rw0_wd_in[146]
    DIRECTION INPUT ;
    USE SIGNAL ;
    SHAPE ABUTMENT ;
    PORT
      LAYER M3 ;
      RECT 4.743 0.000 4.761 0.054 ;
    END
  END rw0_wd_in[146]
  PIN rw0_wd_in[147]
    DIRECTION INPUT ;
    USE SIGNAL ;
    SHAPE ABUTMENT ;
    PORT
      LAYER M3 ;
      RECT 4.995 0.000 5.013 0.054 ;
    END
  END rw0_wd_in[147]
  PIN rw0_wd_in[148]
    DIRECTION INPUT ;
    USE SIGNAL ;
    SHAPE ABUTMENT ;
    PORT
      LAYER M3 ;
      RECT 5.247 0.000 5.265 0.054 ;
    END
  END rw0_wd_in[148]
  PIN rw0_wd_in[149]
    DIRECTION INPUT ;
    USE SIGNAL ;
    SHAPE ABUTMENT ;
    PORT
      LAYER M3 ;
      RECT 5.499 0.000 5.517 0.054 ;
    END
  END rw0_wd_in[149]
  PIN rw0_wd_in[150]
    DIRECTION INPUT ;
    USE SIGNAL ;
    SHAPE ABUTMENT ;
    PORT
      LAYER M3 ;
      RECT 5.751 0.000 5.769 0.054 ;
    END
  END rw0_wd_in[150]
  PIN rw0_wd_in[151]
    DIRECTION INPUT ;
    USE SIGNAL ;
    SHAPE ABUTMENT ;
    PORT
      LAYER M3 ;
      RECT 6.003 0.000 6.021 0.054 ;
    END
  END rw0_wd_in[151]
  PIN rw0_wd_in[152]
    DIRECTION INPUT ;
    USE SIGNAL ;
    SHAPE ABUTMENT ;
    PORT
      LAYER M3 ;
      RECT 6.255 0.000 6.273 0.054 ;
    END
  END rw0_wd_in[152]
  PIN rw0_wd_in[153]
    DIRECTION INPUT ;
    USE SIGNAL ;
    SHAPE ABUTMENT ;
    PORT
      LAYER M3 ;
      RECT 6.507 0.000 6.525 0.054 ;
    END
  END rw0_wd_in[153]
  PIN rw0_wd_in[154]
    DIRECTION INPUT ;
    USE SIGNAL ;
    SHAPE ABUTMENT ;
    PORT
      LAYER M3 ;
      RECT 6.759 0.000 6.777 0.054 ;
    END
  END rw0_wd_in[154]
  PIN rw0_wd_in[155]
    DIRECTION INPUT ;
    USE SIGNAL ;
    SHAPE ABUTMENT ;
    PORT
      LAYER M3 ;
      RECT 7.011 0.000 7.029 0.054 ;
    END
  END rw0_wd_in[155]
  PIN rw0_wd_in[156]
    DIRECTION INPUT ;
    USE SIGNAL ;
    SHAPE ABUTMENT ;
    PORT
      LAYER M3 ;
      RECT 7.263 0.000 7.281 0.054 ;
    END
  END rw0_wd_in[156]
  PIN rw0_wd_in[157]
    DIRECTION INPUT ;
    USE SIGNAL ;
    SHAPE ABUTMENT ;
    PORT
      LAYER M3 ;
      RECT 7.515 0.000 7.533 0.054 ;
    END
  END rw0_wd_in[157]
  PIN rw0_wd_in[158]
    DIRECTION INPUT ;
    USE SIGNAL ;
    SHAPE ABUTMENT ;
    PORT
      LAYER M3 ;
      RECT 7.767 0.000 7.785 0.054 ;
    END
  END rw0_wd_in[158]
  PIN rw0_wd_in[159]
    DIRECTION INPUT ;
    USE SIGNAL ;
    SHAPE ABUTMENT ;
    PORT
      LAYER M3 ;
      RECT 8.019 0.000 8.037 0.054 ;
    END
  END rw0_wd_in[159]
  PIN rw0_wd_in[160]
    DIRECTION INPUT ;
    USE SIGNAL ;
    SHAPE ABUTMENT ;
    PORT
      LAYER M3 ;
      RECT 8.271 0.000 8.289 0.054 ;
    END
  END rw0_wd_in[160]
  PIN rw0_wd_in[161]
    DIRECTION INPUT ;
    USE SIGNAL ;
    SHAPE ABUTMENT ;
    PORT
      LAYER M3 ;
      RECT 8.523 0.000 8.541 0.054 ;
    END
  END rw0_wd_in[161]
  PIN rw0_wd_in[162]
    DIRECTION INPUT ;
    USE SIGNAL ;
    SHAPE ABUTMENT ;
    PORT
      LAYER M3 ;
      RECT 8.775 0.000 8.793 0.054 ;
    END
  END rw0_wd_in[162]
  PIN rw0_wd_in[163]
    DIRECTION INPUT ;
    USE SIGNAL ;
    SHAPE ABUTMENT ;
    PORT
      LAYER M3 ;
      RECT 9.027 0.000 9.045 0.054 ;
    END
  END rw0_wd_in[163]
  PIN rw0_wd_in[164]
    DIRECTION INPUT ;
    USE SIGNAL ;
    SHAPE ABUTMENT ;
    PORT
      LAYER M3 ;
      RECT 9.279 0.000 9.297 0.054 ;
    END
  END rw0_wd_in[164]
  PIN rw0_wd_in[165]
    DIRECTION INPUT ;
    USE SIGNAL ;
    SHAPE ABUTMENT ;
    PORT
      LAYER M3 ;
      RECT 9.531 0.000 9.549 0.054 ;
    END
  END rw0_wd_in[165]
  PIN rw0_wd_in[166]
    DIRECTION INPUT ;
    USE SIGNAL ;
    SHAPE ABUTMENT ;
    PORT
      LAYER M3 ;
      RECT 9.783 0.000 9.801 0.054 ;
    END
  END rw0_wd_in[166]
  PIN rw0_wd_in[167]
    DIRECTION INPUT ;
    USE SIGNAL ;
    SHAPE ABUTMENT ;
    PORT
      LAYER M3 ;
      RECT 10.035 0.000 10.053 0.054 ;
    END
  END rw0_wd_in[167]
  PIN rw0_wd_in[168]
    DIRECTION INPUT ;
    USE SIGNAL ;
    SHAPE ABUTMENT ;
    PORT
      LAYER M3 ;
      RECT 10.287 0.000 10.305 0.054 ;
    END
  END rw0_wd_in[168]
  PIN rw0_wd_in[169]
    DIRECTION INPUT ;
    USE SIGNAL ;
    SHAPE ABUTMENT ;
    PORT
      LAYER M3 ;
      RECT 10.539 0.000 10.557 0.054 ;
    END
  END rw0_wd_in[169]
  PIN rw0_wd_in[170]
    DIRECTION INPUT ;
    USE SIGNAL ;
    SHAPE ABUTMENT ;
    PORT
      LAYER M3 ;
      RECT 10.791 0.000 10.809 0.054 ;
    END
  END rw0_wd_in[170]
  PIN rw0_wd_in[171]
    DIRECTION INPUT ;
    USE SIGNAL ;
    SHAPE ABUTMENT ;
    PORT
      LAYER M3 ;
      RECT 11.043 0.000 11.061 0.054 ;
    END
  END rw0_wd_in[171]
  PIN rw0_wd_in[172]
    DIRECTION INPUT ;
    USE SIGNAL ;
    SHAPE ABUTMENT ;
    PORT
      LAYER M3 ;
      RECT 11.295 0.000 11.313 0.054 ;
    END
  END rw0_wd_in[172]
  PIN rw0_wd_in[173]
    DIRECTION INPUT ;
    USE SIGNAL ;
    SHAPE ABUTMENT ;
    PORT
      LAYER M3 ;
      RECT 11.547 0.000 11.565 0.054 ;
    END
  END rw0_wd_in[173]
  PIN rw0_wd_in[174]
    DIRECTION INPUT ;
    USE SIGNAL ;
    SHAPE ABUTMENT ;
    PORT
      LAYER M3 ;
      RECT 11.799 0.000 11.817 0.054 ;
    END
  END rw0_wd_in[174]
  PIN rw0_wd_in[175]
    DIRECTION INPUT ;
    USE SIGNAL ;
    SHAPE ABUTMENT ;
    PORT
      LAYER M3 ;
      RECT 12.051 0.000 12.069 0.054 ;
    END
  END rw0_wd_in[175]
  PIN rw0_wd_in[176]
    DIRECTION INPUT ;
    USE SIGNAL ;
    SHAPE ABUTMENT ;
    PORT
      LAYER M3 ;
      RECT 12.303 0.000 12.321 0.054 ;
    END
  END rw0_wd_in[176]
  PIN rw0_wd_in[177]
    DIRECTION INPUT ;
    USE SIGNAL ;
    SHAPE ABUTMENT ;
    PORT
      LAYER M3 ;
      RECT 12.555 0.000 12.573 0.054 ;
    END
  END rw0_wd_in[177]
  PIN rw0_wd_in[178]
    DIRECTION INPUT ;
    USE SIGNAL ;
    SHAPE ABUTMENT ;
    PORT
      LAYER M3 ;
      RECT 12.807 0.000 12.825 0.054 ;
    END
  END rw0_wd_in[178]
  PIN rw0_wd_in[179]
    DIRECTION INPUT ;
    USE SIGNAL ;
    SHAPE ABUTMENT ;
    PORT
      LAYER M3 ;
      RECT 13.059 0.000 13.077 0.054 ;
    END
  END rw0_wd_in[179]
  PIN rw0_wd_in[180]
    DIRECTION INPUT ;
    USE SIGNAL ;
    SHAPE ABUTMENT ;
    PORT
      LAYER M3 ;
      RECT 13.311 0.000 13.329 0.054 ;
    END
  END rw0_wd_in[180]
  PIN rw0_wd_in[181]
    DIRECTION INPUT ;
    USE SIGNAL ;
    SHAPE ABUTMENT ;
    PORT
      LAYER M3 ;
      RECT 13.563 0.000 13.581 0.054 ;
    END
  END rw0_wd_in[181]
  PIN rw0_wd_in[182]
    DIRECTION INPUT ;
    USE SIGNAL ;
    SHAPE ABUTMENT ;
    PORT
      LAYER M3 ;
      RECT 13.815 0.000 13.833 0.054 ;
    END
  END rw0_wd_in[182]
  PIN rw0_wd_in[183]
    DIRECTION INPUT ;
    USE SIGNAL ;
    SHAPE ABUTMENT ;
    PORT
      LAYER M3 ;
      RECT 14.067 0.000 14.085 0.054 ;
    END
  END rw0_wd_in[183]
  PIN rw0_wd_in[184]
    DIRECTION INPUT ;
    USE SIGNAL ;
    SHAPE ABUTMENT ;
    PORT
      LAYER M3 ;
      RECT 14.319 0.000 14.337 0.054 ;
    END
  END rw0_wd_in[184]
  PIN rw0_wd_in[185]
    DIRECTION INPUT ;
    USE SIGNAL ;
    SHAPE ABUTMENT ;
    PORT
      LAYER M3 ;
      RECT 14.571 0.000 14.589 0.054 ;
    END
  END rw0_wd_in[185]
  PIN rw0_wd_in[186]
    DIRECTION INPUT ;
    USE SIGNAL ;
    SHAPE ABUTMENT ;
    PORT
      LAYER M3 ;
      RECT 14.823 0.000 14.841 0.054 ;
    END
  END rw0_wd_in[186]
  PIN rw0_wd_in[187]
    DIRECTION INPUT ;
    USE SIGNAL ;
    SHAPE ABUTMENT ;
    PORT
      LAYER M3 ;
      RECT 15.075 0.000 15.093 0.054 ;
    END
  END rw0_wd_in[187]
  PIN rw0_wd_in[188]
    DIRECTION INPUT ;
    USE SIGNAL ;
    SHAPE ABUTMENT ;
    PORT
      LAYER M3 ;
      RECT 15.327 0.000 15.345 0.054 ;
    END
  END rw0_wd_in[188]
  PIN rw0_wd_in[189]
    DIRECTION INPUT ;
    USE SIGNAL ;
    SHAPE ABUTMENT ;
    PORT
      LAYER M3 ;
      RECT 15.579 0.000 15.597 0.054 ;
    END
  END rw0_wd_in[189]
  PIN rw0_wd_in[190]
    DIRECTION INPUT ;
    USE SIGNAL ;
    SHAPE ABUTMENT ;
    PORT
      LAYER M3 ;
      RECT 15.831 0.000 15.849 0.054 ;
    END
  END rw0_wd_in[190]
  PIN rw0_wd_in[191]
    DIRECTION INPUT ;
    USE SIGNAL ;
    SHAPE ABUTMENT ;
    PORT
      LAYER M3 ;
      RECT 16.083 0.000 16.101 0.054 ;
    END
  END rw0_wd_in[191]
  PIN rw0_wd_in[192]
    DIRECTION INPUT ;
    USE SIGNAL ;
    SHAPE ABUTMENT ;
    PORT
      LAYER M3 ;
      RECT 16.335 0.000 16.353 0.054 ;
    END
  END rw0_wd_in[192]
  PIN rw0_wd_in[193]
    DIRECTION INPUT ;
    USE SIGNAL ;
    SHAPE ABUTMENT ;
    PORT
      LAYER M3 ;
      RECT 16.587 0.000 16.605 0.054 ;
    END
  END rw0_wd_in[193]
  PIN rw0_wd_in[194]
    DIRECTION INPUT ;
    USE SIGNAL ;
    SHAPE ABUTMENT ;
    PORT
      LAYER M3 ;
      RECT 16.839 0.000 16.857 0.054 ;
    END
  END rw0_wd_in[194]
  PIN rw0_wd_in[195]
    DIRECTION INPUT ;
    USE SIGNAL ;
    SHAPE ABUTMENT ;
    PORT
      LAYER M3 ;
      RECT 17.091 0.000 17.109 0.054 ;
    END
  END rw0_wd_in[195]
  PIN rw0_wd_in[196]
    DIRECTION INPUT ;
    USE SIGNAL ;
    SHAPE ABUTMENT ;
    PORT
      LAYER M3 ;
      RECT 17.343 0.000 17.361 0.054 ;
    END
  END rw0_wd_in[196]
  PIN rw0_wd_in[197]
    DIRECTION INPUT ;
    USE SIGNAL ;
    SHAPE ABUTMENT ;
    PORT
      LAYER M3 ;
      RECT 17.595 0.000 17.613 0.054 ;
    END
  END rw0_wd_in[197]
  PIN rw0_wd_in[198]
    DIRECTION INPUT ;
    USE SIGNAL ;
    SHAPE ABUTMENT ;
    PORT
      LAYER M3 ;
      RECT 17.847 0.000 17.865 0.054 ;
    END
  END rw0_wd_in[198]
  PIN rw0_wd_in[199]
    DIRECTION INPUT ;
    USE SIGNAL ;
    SHAPE ABUTMENT ;
    PORT
      LAYER M3 ;
      RECT 18.099 0.000 18.117 0.054 ;
    END
  END rw0_wd_in[199]
  PIN rw0_wd_in[200]
    DIRECTION INPUT ;
    USE SIGNAL ;
    SHAPE ABUTMENT ;
    PORT
      LAYER M3 ;
      RECT 18.351 0.000 18.369 0.054 ;
    END
  END rw0_wd_in[200]
  PIN rw0_wd_in[201]
    DIRECTION INPUT ;
    USE SIGNAL ;
    SHAPE ABUTMENT ;
    PORT
      LAYER M3 ;
      RECT 18.603 0.000 18.621 0.054 ;
    END
  END rw0_wd_in[201]
  PIN rw0_wd_in[202]
    DIRECTION INPUT ;
    USE SIGNAL ;
    SHAPE ABUTMENT ;
    PORT
      LAYER M3 ;
      RECT 18.855 0.000 18.873 0.054 ;
    END
  END rw0_wd_in[202]
  PIN rw0_wd_in[203]
    DIRECTION INPUT ;
    USE SIGNAL ;
    SHAPE ABUTMENT ;
    PORT
      LAYER M3 ;
      RECT 19.107 0.000 19.125 0.054 ;
    END
  END rw0_wd_in[203]
  PIN rw0_wd_in[204]
    DIRECTION INPUT ;
    USE SIGNAL ;
    SHAPE ABUTMENT ;
    PORT
      LAYER M3 ;
      RECT 19.359 0.000 19.377 0.054 ;
    END
  END rw0_wd_in[204]
  PIN rw0_wd_in[205]
    DIRECTION INPUT ;
    USE SIGNAL ;
    SHAPE ABUTMENT ;
    PORT
      LAYER M3 ;
      RECT 19.611 0.000 19.629 0.054 ;
    END
  END rw0_wd_in[205]
  PIN rw0_wd_in[206]
    DIRECTION INPUT ;
    USE SIGNAL ;
    SHAPE ABUTMENT ;
    PORT
      LAYER M3 ;
      RECT 19.863 0.000 19.881 0.054 ;
    END
  END rw0_wd_in[206]
  PIN rw0_wd_in[207]
    DIRECTION INPUT ;
    USE SIGNAL ;
    SHAPE ABUTMENT ;
    PORT
      LAYER M3 ;
      RECT 20.115 0.000 20.133 0.054 ;
    END
  END rw0_wd_in[207]
  PIN rw0_wd_in[208]
    DIRECTION INPUT ;
    USE SIGNAL ;
    SHAPE ABUTMENT ;
    PORT
      LAYER M3 ;
      RECT 20.367 0.000 20.385 0.054 ;
    END
  END rw0_wd_in[208]
  PIN rw0_wd_in[209]
    DIRECTION INPUT ;
    USE SIGNAL ;
    SHAPE ABUTMENT ;
    PORT
      LAYER M3 ;
      RECT 20.619 0.000 20.637 0.054 ;
    END
  END rw0_wd_in[209]
  PIN rw0_wd_in[210]
    DIRECTION INPUT ;
    USE SIGNAL ;
    SHAPE ABUTMENT ;
    PORT
      LAYER M3 ;
      RECT 20.871 0.000 20.889 0.054 ;
    END
  END rw0_wd_in[210]
  PIN rw0_wd_in[211]
    DIRECTION INPUT ;
    USE SIGNAL ;
    SHAPE ABUTMENT ;
    PORT
      LAYER M3 ;
      RECT 21.123 0.000 21.141 0.054 ;
    END
  END rw0_wd_in[211]
  PIN rw0_wd_in[212]
    DIRECTION INPUT ;
    USE SIGNAL ;
    SHAPE ABUTMENT ;
    PORT
      LAYER M3 ;
      RECT 21.375 0.000 21.393 0.054 ;
    END
  END rw0_wd_in[212]
  PIN rw0_wd_in[213]
    DIRECTION INPUT ;
    USE SIGNAL ;
    SHAPE ABUTMENT ;
    PORT
      LAYER M3 ;
      RECT 21.627 0.000 21.645 0.054 ;
    END
  END rw0_wd_in[213]
  PIN rw0_wd_in[214]
    DIRECTION INPUT ;
    USE SIGNAL ;
    SHAPE ABUTMENT ;
    PORT
      LAYER M3 ;
      RECT 21.879 0.000 21.897 0.054 ;
    END
  END rw0_wd_in[214]
  PIN rw0_wd_in[215]
    DIRECTION INPUT ;
    USE SIGNAL ;
    SHAPE ABUTMENT ;
    PORT
      LAYER M3 ;
      RECT 22.131 0.000 22.149 0.054 ;
    END
  END rw0_wd_in[215]
  PIN rw0_wd_in[216]
    DIRECTION INPUT ;
    USE SIGNAL ;
    SHAPE ABUTMENT ;
    PORT
      LAYER M3 ;
      RECT 22.383 0.000 22.401 0.054 ;
    END
  END rw0_wd_in[216]
  PIN rw0_wd_in[217]
    DIRECTION INPUT ;
    USE SIGNAL ;
    SHAPE ABUTMENT ;
    PORT
      LAYER M3 ;
      RECT 22.635 0.000 22.653 0.054 ;
    END
  END rw0_wd_in[217]
  PIN rw0_wd_in[218]
    DIRECTION INPUT ;
    USE SIGNAL ;
    SHAPE ABUTMENT ;
    PORT
      LAYER M3 ;
      RECT 22.887 0.000 22.905 0.054 ;
    END
  END rw0_wd_in[218]
  PIN rw0_wd_in[219]
    DIRECTION INPUT ;
    USE SIGNAL ;
    SHAPE ABUTMENT ;
    PORT
      LAYER M3 ;
      RECT 23.139 0.000 23.157 0.054 ;
    END
  END rw0_wd_in[219]
  PIN rw0_wd_in[220]
    DIRECTION INPUT ;
    USE SIGNAL ;
    SHAPE ABUTMENT ;
    PORT
      LAYER M3 ;
      RECT 23.391 0.000 23.409 0.054 ;
    END
  END rw0_wd_in[220]
  PIN rw0_wd_in[221]
    DIRECTION INPUT ;
    USE SIGNAL ;
    SHAPE ABUTMENT ;
    PORT
      LAYER M3 ;
      RECT 23.643 0.000 23.661 0.054 ;
    END
  END rw0_wd_in[221]
  PIN rw0_wd_in[222]
    DIRECTION INPUT ;
    USE SIGNAL ;
    SHAPE ABUTMENT ;
    PORT
      LAYER M3 ;
      RECT 23.895 0.000 23.913 0.054 ;
    END
  END rw0_wd_in[222]
  PIN rw0_wd_in[223]
    DIRECTION INPUT ;
    USE SIGNAL ;
    SHAPE ABUTMENT ;
    PORT
      LAYER M3 ;
      RECT 24.147 0.000 24.165 0.054 ;
    END
  END rw0_wd_in[223]
  PIN rw0_wd_in[224]
    DIRECTION INPUT ;
    USE SIGNAL ;
    SHAPE ABUTMENT ;
    PORT
      LAYER M3 ;
      RECT 24.399 0.000 24.417 0.054 ;
    END
  END rw0_wd_in[224]
  PIN rw0_wd_in[225]
    DIRECTION INPUT ;
    USE SIGNAL ;
    SHAPE ABUTMENT ;
    PORT
      LAYER M3 ;
      RECT 24.651 0.000 24.669 0.054 ;
    END
  END rw0_wd_in[225]
  PIN rw0_wd_in[226]
    DIRECTION INPUT ;
    USE SIGNAL ;
    SHAPE ABUTMENT ;
    PORT
      LAYER M3 ;
      RECT 24.903 0.000 24.921 0.054 ;
    END
  END rw0_wd_in[226]
  PIN rw0_wd_in[227]
    DIRECTION INPUT ;
    USE SIGNAL ;
    SHAPE ABUTMENT ;
    PORT
      LAYER M3 ;
      RECT 25.155 0.000 25.173 0.054 ;
    END
  END rw0_wd_in[227]
  PIN rw0_wd_in[228]
    DIRECTION INPUT ;
    USE SIGNAL ;
    SHAPE ABUTMENT ;
    PORT
      LAYER M3 ;
      RECT 25.407 0.000 25.425 0.054 ;
    END
  END rw0_wd_in[228]
  PIN rw0_wd_in[229]
    DIRECTION INPUT ;
    USE SIGNAL ;
    SHAPE ABUTMENT ;
    PORT
      LAYER M3 ;
      RECT 25.659 0.000 25.677 0.054 ;
    END
  END rw0_wd_in[229]
  PIN rw0_wd_in[230]
    DIRECTION INPUT ;
    USE SIGNAL ;
    SHAPE ABUTMENT ;
    PORT
      LAYER M3 ;
      RECT 25.911 0.000 25.929 0.054 ;
    END
  END rw0_wd_in[230]
  PIN rw0_wd_in[231]
    DIRECTION INPUT ;
    USE SIGNAL ;
    SHAPE ABUTMENT ;
    PORT
      LAYER M3 ;
      RECT 26.163 0.000 26.181 0.054 ;
    END
  END rw0_wd_in[231]
  PIN rw0_wd_in[232]
    DIRECTION INPUT ;
    USE SIGNAL ;
    SHAPE ABUTMENT ;
    PORT
      LAYER M3 ;
      RECT 26.415 0.000 26.433 0.054 ;
    END
  END rw0_wd_in[232]
  PIN rw0_wd_in[233]
    DIRECTION INPUT ;
    USE SIGNAL ;
    SHAPE ABUTMENT ;
    PORT
      LAYER M3 ;
      RECT 26.667 0.000 26.685 0.054 ;
    END
  END rw0_wd_in[233]
  PIN rw0_wd_in[234]
    DIRECTION INPUT ;
    USE SIGNAL ;
    SHAPE ABUTMENT ;
    PORT
      LAYER M3 ;
      RECT 26.919 0.000 26.937 0.054 ;
    END
  END rw0_wd_in[234]
  PIN rw0_wd_in[235]
    DIRECTION INPUT ;
    USE SIGNAL ;
    SHAPE ABUTMENT ;
    PORT
      LAYER M3 ;
      RECT 27.171 0.000 27.189 0.054 ;
    END
  END rw0_wd_in[235]
  PIN rw0_wd_in[236]
    DIRECTION INPUT ;
    USE SIGNAL ;
    SHAPE ABUTMENT ;
    PORT
      LAYER M3 ;
      RECT 27.423 0.000 27.441 0.054 ;
    END
  END rw0_wd_in[236]
  PIN rw0_wd_in[237]
    DIRECTION INPUT ;
    USE SIGNAL ;
    SHAPE ABUTMENT ;
    PORT
      LAYER M3 ;
      RECT 27.675 0.000 27.693 0.054 ;
    END
  END rw0_wd_in[237]
  PIN rw0_wd_in[238]
    DIRECTION INPUT ;
    USE SIGNAL ;
    SHAPE ABUTMENT ;
    PORT
      LAYER M3 ;
      RECT 27.927 0.000 27.945 0.054 ;
    END
  END rw0_wd_in[238]
  PIN rw0_wd_in[239]
    DIRECTION INPUT ;
    USE SIGNAL ;
    SHAPE ABUTMENT ;
    PORT
      LAYER M3 ;
      RECT 28.179 0.000 28.197 0.054 ;
    END
  END rw0_wd_in[239]
  PIN rw0_wd_in[240]
    DIRECTION INPUT ;
    USE SIGNAL ;
    SHAPE ABUTMENT ;
    PORT
      LAYER M3 ;
      RECT 28.431 0.000 28.449 0.054 ;
    END
  END rw0_wd_in[240]
  PIN rw0_wd_in[241]
    DIRECTION INPUT ;
    USE SIGNAL ;
    SHAPE ABUTMENT ;
    PORT
      LAYER M3 ;
      RECT 28.683 0.000 28.701 0.054 ;
    END
  END rw0_wd_in[241]
  PIN rw0_wd_in[242]
    DIRECTION INPUT ;
    USE SIGNAL ;
    SHAPE ABUTMENT ;
    PORT
      LAYER M3 ;
      RECT 28.935 0.000 28.953 0.054 ;
    END
  END rw0_wd_in[242]
  PIN rw0_wd_in[243]
    DIRECTION INPUT ;
    USE SIGNAL ;
    SHAPE ABUTMENT ;
    PORT
      LAYER M3 ;
      RECT 29.187 0.000 29.205 0.054 ;
    END
  END rw0_wd_in[243]
  PIN rw0_wd_in[244]
    DIRECTION INPUT ;
    USE SIGNAL ;
    SHAPE ABUTMENT ;
    PORT
      LAYER M3 ;
      RECT 29.439 0.000 29.457 0.054 ;
    END
  END rw0_wd_in[244]
  PIN rw0_wd_in[245]
    DIRECTION INPUT ;
    USE SIGNAL ;
    SHAPE ABUTMENT ;
    PORT
      LAYER M3 ;
      RECT 29.691 0.000 29.709 0.054 ;
    END
  END rw0_wd_in[245]
  PIN rw0_wd_in[246]
    DIRECTION INPUT ;
    USE SIGNAL ;
    SHAPE ABUTMENT ;
    PORT
      LAYER M3 ;
      RECT 29.943 0.000 29.961 0.054 ;
    END
  END rw0_wd_in[246]
  PIN rw0_wd_in[247]
    DIRECTION INPUT ;
    USE SIGNAL ;
    SHAPE ABUTMENT ;
    PORT
      LAYER M3 ;
      RECT 30.195 0.000 30.213 0.054 ;
    END
  END rw0_wd_in[247]
  PIN rw0_wd_in[248]
    DIRECTION INPUT ;
    USE SIGNAL ;
    SHAPE ABUTMENT ;
    PORT
      LAYER M3 ;
      RECT 30.447 0.000 30.465 0.054 ;
    END
  END rw0_wd_in[248]
  PIN rw0_wd_in[249]
    DIRECTION INPUT ;
    USE SIGNAL ;
    SHAPE ABUTMENT ;
    PORT
      LAYER M3 ;
      RECT 30.699 0.000 30.717 0.054 ;
    END
  END rw0_wd_in[249]
  PIN rw0_wd_in[250]
    DIRECTION INPUT ;
    USE SIGNAL ;
    SHAPE ABUTMENT ;
    PORT
      LAYER M3 ;
      RECT 30.951 0.000 30.969 0.054 ;
    END
  END rw0_wd_in[250]
  PIN rw0_wd_in[251]
    DIRECTION INPUT ;
    USE SIGNAL ;
    SHAPE ABUTMENT ;
    PORT
      LAYER M3 ;
      RECT 31.203 0.000 31.221 0.054 ;
    END
  END rw0_wd_in[251]
  PIN rw0_wd_in[252]
    DIRECTION INPUT ;
    USE SIGNAL ;
    SHAPE ABUTMENT ;
    PORT
      LAYER M3 ;
      RECT 31.455 0.000 31.473 0.054 ;
    END
  END rw0_wd_in[252]
  PIN rw0_wd_in[253]
    DIRECTION INPUT ;
    USE SIGNAL ;
    SHAPE ABUTMENT ;
    PORT
      LAYER M3 ;
      RECT 31.707 0.000 31.725 0.054 ;
    END
  END rw0_wd_in[253]
  PIN rw0_wd_in[254]
    DIRECTION INPUT ;
    USE SIGNAL ;
    SHAPE ABUTMENT ;
    PORT
      LAYER M3 ;
      RECT 31.959 0.000 31.977 0.054 ;
    END
  END rw0_wd_in[254]
  PIN rw0_wd_in[255]
    DIRECTION INPUT ;
    USE SIGNAL ;
    SHAPE ABUTMENT ;
    PORT
      LAYER M3 ;
      RECT 32.211 0.000 32.229 0.054 ;
    END
  END rw0_wd_in[255]
  PIN rw0_rd_out[0]
    DIRECTION OUTPUT ;
    USE SIGNAL ;
    SHAPE ABUTMENT ;
    PORT
      LAYER M3 ;
      RECT 32.463 0.000 32.481 0.054 ;
    END
  END rw0_rd_out[0]
  PIN rw0_rd_out[1]
    DIRECTION OUTPUT ;
    USE SIGNAL ;
    SHAPE ABUTMENT ;
    PORT
      LAYER M3 ;
      RECT 32.715 0.000 32.733 0.054 ;
    END
  END rw0_rd_out[1]
  PIN rw0_rd_out[2]
    DIRECTION OUTPUT ;
    USE SIGNAL ;
    SHAPE ABUTMENT ;
    PORT
      LAYER M3 ;
      RECT 32.967 0.000 32.985 0.054 ;
    END
  END rw0_rd_out[2]
  PIN rw0_rd_out[3]
    DIRECTION OUTPUT ;
    USE SIGNAL ;
    SHAPE ABUTMENT ;
    PORT
      LAYER M3 ;
      RECT 33.219 0.000 33.237 0.054 ;
    END
  END rw0_rd_out[3]
  PIN rw0_rd_out[4]
    DIRECTION OUTPUT ;
    USE SIGNAL ;
    SHAPE ABUTMENT ;
    PORT
      LAYER M3 ;
      RECT 33.471 0.000 33.489 0.054 ;
    END
  END rw0_rd_out[4]
  PIN rw0_rd_out[5]
    DIRECTION OUTPUT ;
    USE SIGNAL ;
    SHAPE ABUTMENT ;
    PORT
      LAYER M3 ;
      RECT 33.723 0.000 33.741 0.054 ;
    END
  END rw0_rd_out[5]
  PIN rw0_rd_out[6]
    DIRECTION OUTPUT ;
    USE SIGNAL ;
    SHAPE ABUTMENT ;
    PORT
      LAYER M3 ;
      RECT 33.975 0.000 33.993 0.054 ;
    END
  END rw0_rd_out[6]
  PIN rw0_rd_out[7]
    DIRECTION OUTPUT ;
    USE SIGNAL ;
    SHAPE ABUTMENT ;
    PORT
      LAYER M3 ;
      RECT 34.227 0.000 34.245 0.054 ;
    END
  END rw0_rd_out[7]
  PIN rw0_rd_out[8]
    DIRECTION OUTPUT ;
    USE SIGNAL ;
    SHAPE ABUTMENT ;
    PORT
      LAYER M3 ;
      RECT 34.479 0.000 34.497 0.054 ;
    END
  END rw0_rd_out[8]
  PIN rw0_rd_out[9]
    DIRECTION OUTPUT ;
    USE SIGNAL ;
    SHAPE ABUTMENT ;
    PORT
      LAYER M3 ;
      RECT 34.731 0.000 34.749 0.054 ;
    END
  END rw0_rd_out[9]
  PIN rw0_rd_out[10]
    DIRECTION OUTPUT ;
    USE SIGNAL ;
    SHAPE ABUTMENT ;
    PORT
      LAYER M3 ;
      RECT 34.983 0.000 35.001 0.054 ;
    END
  END rw0_rd_out[10]
  PIN rw0_rd_out[11]
    DIRECTION OUTPUT ;
    USE SIGNAL ;
    SHAPE ABUTMENT ;
    PORT
      LAYER M3 ;
      RECT 35.235 0.000 35.253 0.054 ;
    END
  END rw0_rd_out[11]
  PIN rw0_rd_out[12]
    DIRECTION OUTPUT ;
    USE SIGNAL ;
    SHAPE ABUTMENT ;
    PORT
      LAYER M3 ;
      RECT 35.487 0.000 35.505 0.054 ;
    END
  END rw0_rd_out[12]
  PIN rw0_rd_out[13]
    DIRECTION OUTPUT ;
    USE SIGNAL ;
    SHAPE ABUTMENT ;
    PORT
      LAYER M3 ;
      RECT 35.739 0.000 35.757 0.054 ;
    END
  END rw0_rd_out[13]
  PIN rw0_rd_out[14]
    DIRECTION OUTPUT ;
    USE SIGNAL ;
    SHAPE ABUTMENT ;
    PORT
      LAYER M3 ;
      RECT 35.991 0.000 36.009 0.054 ;
    END
  END rw0_rd_out[14]
  PIN rw0_rd_out[15]
    DIRECTION OUTPUT ;
    USE SIGNAL ;
    SHAPE ABUTMENT ;
    PORT
      LAYER M3 ;
      RECT 36.243 0.000 36.261 0.054 ;
    END
  END rw0_rd_out[15]
  PIN rw0_rd_out[16]
    DIRECTION OUTPUT ;
    USE SIGNAL ;
    SHAPE ABUTMENT ;
    PORT
      LAYER M3 ;
      RECT 36.495 0.000 36.513 0.054 ;
    END
  END rw0_rd_out[16]
  PIN rw0_rd_out[17]
    DIRECTION OUTPUT ;
    USE SIGNAL ;
    SHAPE ABUTMENT ;
    PORT
      LAYER M3 ;
      RECT 36.747 0.000 36.765 0.054 ;
    END
  END rw0_rd_out[17]
  PIN rw0_rd_out[18]
    DIRECTION OUTPUT ;
    USE SIGNAL ;
    SHAPE ABUTMENT ;
    PORT
      LAYER M3 ;
      RECT 36.999 0.000 37.017 0.054 ;
    END
  END rw0_rd_out[18]
  PIN rw0_rd_out[19]
    DIRECTION OUTPUT ;
    USE SIGNAL ;
    SHAPE ABUTMENT ;
    PORT
      LAYER M3 ;
      RECT 37.251 0.000 37.269 0.054 ;
    END
  END rw0_rd_out[19]
  PIN rw0_rd_out[20]
    DIRECTION OUTPUT ;
    USE SIGNAL ;
    SHAPE ABUTMENT ;
    PORT
      LAYER M3 ;
      RECT 37.503 0.000 37.521 0.054 ;
    END
  END rw0_rd_out[20]
  PIN rw0_rd_out[21]
    DIRECTION OUTPUT ;
    USE SIGNAL ;
    SHAPE ABUTMENT ;
    PORT
      LAYER M3 ;
      RECT 37.755 0.000 37.773 0.054 ;
    END
  END rw0_rd_out[21]
  PIN rw0_rd_out[22]
    DIRECTION OUTPUT ;
    USE SIGNAL ;
    SHAPE ABUTMENT ;
    PORT
      LAYER M3 ;
      RECT 38.007 0.000 38.025 0.054 ;
    END
  END rw0_rd_out[22]
  PIN rw0_rd_out[23]
    DIRECTION OUTPUT ;
    USE SIGNAL ;
    SHAPE ABUTMENT ;
    PORT
      LAYER M3 ;
      RECT 38.259 0.000 38.277 0.054 ;
    END
  END rw0_rd_out[23]
  PIN rw0_rd_out[24]
    DIRECTION OUTPUT ;
    USE SIGNAL ;
    SHAPE ABUTMENT ;
    PORT
      LAYER M3 ;
      RECT 38.511 0.000 38.529 0.054 ;
    END
  END rw0_rd_out[24]
  PIN rw0_rd_out[25]
    DIRECTION OUTPUT ;
    USE SIGNAL ;
    SHAPE ABUTMENT ;
    PORT
      LAYER M3 ;
      RECT 38.763 0.000 38.781 0.054 ;
    END
  END rw0_rd_out[25]
  PIN rw0_rd_out[26]
    DIRECTION OUTPUT ;
    USE SIGNAL ;
    SHAPE ABUTMENT ;
    PORT
      LAYER M3 ;
      RECT 39.015 0.000 39.033 0.054 ;
    END
  END rw0_rd_out[26]
  PIN rw0_rd_out[27]
    DIRECTION OUTPUT ;
    USE SIGNAL ;
    SHAPE ABUTMENT ;
    PORT
      LAYER M3 ;
      RECT 39.267 0.000 39.285 0.054 ;
    END
  END rw0_rd_out[27]
  PIN rw0_rd_out[28]
    DIRECTION OUTPUT ;
    USE SIGNAL ;
    SHAPE ABUTMENT ;
    PORT
      LAYER M3 ;
      RECT 39.519 0.000 39.537 0.054 ;
    END
  END rw0_rd_out[28]
  PIN rw0_rd_out[29]
    DIRECTION OUTPUT ;
    USE SIGNAL ;
    SHAPE ABUTMENT ;
    PORT
      LAYER M3 ;
      RECT 39.771 0.000 39.789 0.054 ;
    END
  END rw0_rd_out[29]
  PIN rw0_rd_out[30]
    DIRECTION OUTPUT ;
    USE SIGNAL ;
    SHAPE ABUTMENT ;
    PORT
      LAYER M3 ;
      RECT 40.023 0.000 40.041 0.054 ;
    END
  END rw0_rd_out[30]
  PIN rw0_rd_out[31]
    DIRECTION OUTPUT ;
    USE SIGNAL ;
    SHAPE ABUTMENT ;
    PORT
      LAYER M3 ;
      RECT 40.275 0.000 40.293 0.054 ;
    END
  END rw0_rd_out[31]
  PIN rw0_rd_out[32]
    DIRECTION OUTPUT ;
    USE SIGNAL ;
    SHAPE ABUTMENT ;
    PORT
      LAYER M3 ;
      RECT 40.527 0.000 40.545 0.054 ;
    END
  END rw0_rd_out[32]
  PIN rw0_rd_out[33]
    DIRECTION OUTPUT ;
    USE SIGNAL ;
    SHAPE ABUTMENT ;
    PORT
      LAYER M3 ;
      RECT 40.779 0.000 40.797 0.054 ;
    END
  END rw0_rd_out[33]
  PIN rw0_rd_out[34]
    DIRECTION OUTPUT ;
    USE SIGNAL ;
    SHAPE ABUTMENT ;
    PORT
      LAYER M3 ;
      RECT 41.031 0.000 41.049 0.054 ;
    END
  END rw0_rd_out[34]
  PIN rw0_rd_out[35]
    DIRECTION OUTPUT ;
    USE SIGNAL ;
    SHAPE ABUTMENT ;
    PORT
      LAYER M3 ;
      RECT 41.283 0.000 41.301 0.054 ;
    END
  END rw0_rd_out[35]
  PIN rw0_rd_out[36]
    DIRECTION OUTPUT ;
    USE SIGNAL ;
    SHAPE ABUTMENT ;
    PORT
      LAYER M3 ;
      RECT 41.535 0.000 41.553 0.054 ;
    END
  END rw0_rd_out[36]
  PIN rw0_rd_out[37]
    DIRECTION OUTPUT ;
    USE SIGNAL ;
    SHAPE ABUTMENT ;
    PORT
      LAYER M3 ;
      RECT 41.787 0.000 41.805 0.054 ;
    END
  END rw0_rd_out[37]
  PIN rw0_rd_out[38]
    DIRECTION OUTPUT ;
    USE SIGNAL ;
    SHAPE ABUTMENT ;
    PORT
      LAYER M3 ;
      RECT 42.039 0.000 42.057 0.054 ;
    END
  END rw0_rd_out[38]
  PIN rw0_rd_out[39]
    DIRECTION OUTPUT ;
    USE SIGNAL ;
    SHAPE ABUTMENT ;
    PORT
      LAYER M3 ;
      RECT 42.291 0.000 42.309 0.054 ;
    END
  END rw0_rd_out[39]
  PIN rw0_rd_out[40]
    DIRECTION OUTPUT ;
    USE SIGNAL ;
    SHAPE ABUTMENT ;
    PORT
      LAYER M3 ;
      RECT 42.543 0.000 42.561 0.054 ;
    END
  END rw0_rd_out[40]
  PIN rw0_rd_out[41]
    DIRECTION OUTPUT ;
    USE SIGNAL ;
    SHAPE ABUTMENT ;
    PORT
      LAYER M3 ;
      RECT 42.795 0.000 42.813 0.054 ;
    END
  END rw0_rd_out[41]
  PIN rw0_rd_out[42]
    DIRECTION OUTPUT ;
    USE SIGNAL ;
    SHAPE ABUTMENT ;
    PORT
      LAYER M3 ;
      RECT 43.047 0.000 43.065 0.054 ;
    END
  END rw0_rd_out[42]
  PIN rw0_rd_out[43]
    DIRECTION OUTPUT ;
    USE SIGNAL ;
    SHAPE ABUTMENT ;
    PORT
      LAYER M3 ;
      RECT 43.299 0.000 43.317 0.054 ;
    END
  END rw0_rd_out[43]
  PIN rw0_rd_out[44]
    DIRECTION OUTPUT ;
    USE SIGNAL ;
    SHAPE ABUTMENT ;
    PORT
      LAYER M3 ;
      RECT 43.551 0.000 43.569 0.054 ;
    END
  END rw0_rd_out[44]
  PIN rw0_rd_out[45]
    DIRECTION OUTPUT ;
    USE SIGNAL ;
    SHAPE ABUTMENT ;
    PORT
      LAYER M3 ;
      RECT 43.803 0.000 43.821 0.054 ;
    END
  END rw0_rd_out[45]
  PIN rw0_rd_out[46]
    DIRECTION OUTPUT ;
    USE SIGNAL ;
    SHAPE ABUTMENT ;
    PORT
      LAYER M3 ;
      RECT 44.055 0.000 44.073 0.054 ;
    END
  END rw0_rd_out[46]
  PIN rw0_rd_out[47]
    DIRECTION OUTPUT ;
    USE SIGNAL ;
    SHAPE ABUTMENT ;
    PORT
      LAYER M3 ;
      RECT 44.307 0.000 44.325 0.054 ;
    END
  END rw0_rd_out[47]
  PIN rw0_rd_out[48]
    DIRECTION OUTPUT ;
    USE SIGNAL ;
    SHAPE ABUTMENT ;
    PORT
      LAYER M3 ;
      RECT 44.559 0.000 44.577 0.054 ;
    END
  END rw0_rd_out[48]
  PIN rw0_rd_out[49]
    DIRECTION OUTPUT ;
    USE SIGNAL ;
    SHAPE ABUTMENT ;
    PORT
      LAYER M3 ;
      RECT 44.811 0.000 44.829 0.054 ;
    END
  END rw0_rd_out[49]
  PIN rw0_rd_out[50]
    DIRECTION OUTPUT ;
    USE SIGNAL ;
    SHAPE ABUTMENT ;
    PORT
      LAYER M3 ;
      RECT 45.063 0.000 45.081 0.054 ;
    END
  END rw0_rd_out[50]
  PIN rw0_rd_out[51]
    DIRECTION OUTPUT ;
    USE SIGNAL ;
    SHAPE ABUTMENT ;
    PORT
      LAYER M3 ;
      RECT 45.315 0.000 45.333 0.054 ;
    END
  END rw0_rd_out[51]
  PIN rw0_rd_out[52]
    DIRECTION OUTPUT ;
    USE SIGNAL ;
    SHAPE ABUTMENT ;
    PORT
      LAYER M3 ;
      RECT 45.567 0.000 45.585 0.054 ;
    END
  END rw0_rd_out[52]
  PIN rw0_rd_out[53]
    DIRECTION OUTPUT ;
    USE SIGNAL ;
    SHAPE ABUTMENT ;
    PORT
      LAYER M3 ;
      RECT 45.819 0.000 45.837 0.054 ;
    END
  END rw0_rd_out[53]
  PIN rw0_rd_out[54]
    DIRECTION OUTPUT ;
    USE SIGNAL ;
    SHAPE ABUTMENT ;
    PORT
      LAYER M3 ;
      RECT 46.071 0.000 46.089 0.054 ;
    END
  END rw0_rd_out[54]
  PIN rw0_rd_out[55]
    DIRECTION OUTPUT ;
    USE SIGNAL ;
    SHAPE ABUTMENT ;
    PORT
      LAYER M3 ;
      RECT 46.323 0.000 46.341 0.054 ;
    END
  END rw0_rd_out[55]
  PIN rw0_rd_out[56]
    DIRECTION OUTPUT ;
    USE SIGNAL ;
    SHAPE ABUTMENT ;
    PORT
      LAYER M3 ;
      RECT 46.575 0.000 46.593 0.054 ;
    END
  END rw0_rd_out[56]
  PIN rw0_rd_out[57]
    DIRECTION OUTPUT ;
    USE SIGNAL ;
    SHAPE ABUTMENT ;
    PORT
      LAYER M3 ;
      RECT 46.827 0.000 46.845 0.054 ;
    END
  END rw0_rd_out[57]
  PIN rw0_rd_out[58]
    DIRECTION OUTPUT ;
    USE SIGNAL ;
    SHAPE ABUTMENT ;
    PORT
      LAYER M3 ;
      RECT 47.079 0.000 47.097 0.054 ;
    END
  END rw0_rd_out[58]
  PIN rw0_rd_out[59]
    DIRECTION OUTPUT ;
    USE SIGNAL ;
    SHAPE ABUTMENT ;
    PORT
      LAYER M3 ;
      RECT 47.331 0.000 47.349 0.054 ;
    END
  END rw0_rd_out[59]
  PIN rw0_rd_out[60]
    DIRECTION OUTPUT ;
    USE SIGNAL ;
    SHAPE ABUTMENT ;
    PORT
      LAYER M3 ;
      RECT 47.583 0.000 47.601 0.054 ;
    END
  END rw0_rd_out[60]
  PIN rw0_rd_out[61]
    DIRECTION OUTPUT ;
    USE SIGNAL ;
    SHAPE ABUTMENT ;
    PORT
      LAYER M3 ;
      RECT 47.835 0.000 47.853 0.054 ;
    END
  END rw0_rd_out[61]
  PIN rw0_rd_out[62]
    DIRECTION OUTPUT ;
    USE SIGNAL ;
    SHAPE ABUTMENT ;
    PORT
      LAYER M3 ;
      RECT 48.087 0.000 48.105 0.054 ;
    END
  END rw0_rd_out[62]
  PIN rw0_rd_out[63]
    DIRECTION OUTPUT ;
    USE SIGNAL ;
    SHAPE ABUTMENT ;
    PORT
      LAYER M3 ;
      RECT 48.339 0.000 48.357 0.054 ;
    END
  END rw0_rd_out[63]
  PIN rw0_rd_out[64]
    DIRECTION OUTPUT ;
    USE SIGNAL ;
    SHAPE ABUTMENT ;
    PORT
      LAYER M3 ;
      RECT 48.591 0.000 48.609 0.054 ;
    END
  END rw0_rd_out[64]
  PIN rw0_rd_out[65]
    DIRECTION OUTPUT ;
    USE SIGNAL ;
    SHAPE ABUTMENT ;
    PORT
      LAYER M3 ;
      RECT 48.843 0.000 48.861 0.054 ;
    END
  END rw0_rd_out[65]
  PIN rw0_rd_out[66]
    DIRECTION OUTPUT ;
    USE SIGNAL ;
    SHAPE ABUTMENT ;
    PORT
      LAYER M3 ;
      RECT 49.095 0.000 49.113 0.054 ;
    END
  END rw0_rd_out[66]
  PIN rw0_rd_out[67]
    DIRECTION OUTPUT ;
    USE SIGNAL ;
    SHAPE ABUTMENT ;
    PORT
      LAYER M3 ;
      RECT 49.347 0.000 49.365 0.054 ;
    END
  END rw0_rd_out[67]
  PIN rw0_rd_out[68]
    DIRECTION OUTPUT ;
    USE SIGNAL ;
    SHAPE ABUTMENT ;
    PORT
      LAYER M3 ;
      RECT 49.599 0.000 49.617 0.054 ;
    END
  END rw0_rd_out[68]
  PIN rw0_rd_out[69]
    DIRECTION OUTPUT ;
    USE SIGNAL ;
    SHAPE ABUTMENT ;
    PORT
      LAYER M3 ;
      RECT 49.851 0.000 49.869 0.054 ;
    END
  END rw0_rd_out[69]
  PIN rw0_rd_out[70]
    DIRECTION OUTPUT ;
    USE SIGNAL ;
    SHAPE ABUTMENT ;
    PORT
      LAYER M3 ;
      RECT 50.103 0.000 50.121 0.054 ;
    END
  END rw0_rd_out[70]
  PIN rw0_rd_out[71]
    DIRECTION OUTPUT ;
    USE SIGNAL ;
    SHAPE ABUTMENT ;
    PORT
      LAYER M3 ;
      RECT 50.355 0.000 50.373 0.054 ;
    END
  END rw0_rd_out[71]
  PIN rw0_rd_out[72]
    DIRECTION OUTPUT ;
    USE SIGNAL ;
    SHAPE ABUTMENT ;
    PORT
      LAYER M3 ;
      RECT 50.607 0.000 50.625 0.054 ;
    END
  END rw0_rd_out[72]
  PIN rw0_rd_out[73]
    DIRECTION OUTPUT ;
    USE SIGNAL ;
    SHAPE ABUTMENT ;
    PORT
      LAYER M3 ;
      RECT 50.859 0.000 50.877 0.054 ;
    END
  END rw0_rd_out[73]
  PIN rw0_rd_out[74]
    DIRECTION OUTPUT ;
    USE SIGNAL ;
    SHAPE ABUTMENT ;
    PORT
      LAYER M3 ;
      RECT 51.111 0.000 51.129 0.054 ;
    END
  END rw0_rd_out[74]
  PIN rw0_rd_out[75]
    DIRECTION OUTPUT ;
    USE SIGNAL ;
    SHAPE ABUTMENT ;
    PORT
      LAYER M3 ;
      RECT 51.363 0.000 51.381 0.054 ;
    END
  END rw0_rd_out[75]
  PIN rw0_rd_out[76]
    DIRECTION OUTPUT ;
    USE SIGNAL ;
    SHAPE ABUTMENT ;
    PORT
      LAYER M3 ;
      RECT 51.615 0.000 51.633 0.054 ;
    END
  END rw0_rd_out[76]
  PIN rw0_rd_out[77]
    DIRECTION OUTPUT ;
    USE SIGNAL ;
    SHAPE ABUTMENT ;
    PORT
      LAYER M3 ;
      RECT 51.867 0.000 51.885 0.054 ;
    END
  END rw0_rd_out[77]
  PIN rw0_rd_out[78]
    DIRECTION OUTPUT ;
    USE SIGNAL ;
    SHAPE ABUTMENT ;
    PORT
      LAYER M3 ;
      RECT 52.119 0.000 52.137 0.054 ;
    END
  END rw0_rd_out[78]
  PIN rw0_rd_out[79]
    DIRECTION OUTPUT ;
    USE SIGNAL ;
    SHAPE ABUTMENT ;
    PORT
      LAYER M3 ;
      RECT 52.371 0.000 52.389 0.054 ;
    END
  END rw0_rd_out[79]
  PIN rw0_rd_out[80]
    DIRECTION OUTPUT ;
    USE SIGNAL ;
    SHAPE ABUTMENT ;
    PORT
      LAYER M3 ;
      RECT 52.623 0.000 52.641 0.054 ;
    END
  END rw0_rd_out[80]
  PIN rw0_rd_out[81]
    DIRECTION OUTPUT ;
    USE SIGNAL ;
    SHAPE ABUTMENT ;
    PORT
      LAYER M3 ;
      RECT 52.875 0.000 52.893 0.054 ;
    END
  END rw0_rd_out[81]
  PIN rw0_rd_out[82]
    DIRECTION OUTPUT ;
    USE SIGNAL ;
    SHAPE ABUTMENT ;
    PORT
      LAYER M3 ;
      RECT 53.127 0.000 53.145 0.054 ;
    END
  END rw0_rd_out[82]
  PIN rw0_rd_out[83]
    DIRECTION OUTPUT ;
    USE SIGNAL ;
    SHAPE ABUTMENT ;
    PORT
      LAYER M3 ;
      RECT 53.379 0.000 53.397 0.054 ;
    END
  END rw0_rd_out[83]
  PIN rw0_rd_out[84]
    DIRECTION OUTPUT ;
    USE SIGNAL ;
    SHAPE ABUTMENT ;
    PORT
      LAYER M3 ;
      RECT 53.631 0.000 53.649 0.054 ;
    END
  END rw0_rd_out[84]
  PIN rw0_rd_out[85]
    DIRECTION OUTPUT ;
    USE SIGNAL ;
    SHAPE ABUTMENT ;
    PORT
      LAYER M3 ;
      RECT 53.883 0.000 53.901 0.054 ;
    END
  END rw0_rd_out[85]
  PIN rw0_rd_out[86]
    DIRECTION OUTPUT ;
    USE SIGNAL ;
    SHAPE ABUTMENT ;
    PORT
      LAYER M3 ;
      RECT 54.135 0.000 54.153 0.054 ;
    END
  END rw0_rd_out[86]
  PIN rw0_rd_out[87]
    DIRECTION OUTPUT ;
    USE SIGNAL ;
    SHAPE ABUTMENT ;
    PORT
      LAYER M3 ;
      RECT 54.387 0.000 54.405 0.054 ;
    END
  END rw0_rd_out[87]
  PIN rw0_rd_out[88]
    DIRECTION OUTPUT ;
    USE SIGNAL ;
    SHAPE ABUTMENT ;
    PORT
      LAYER M3 ;
      RECT 54.639 0.000 54.657 0.054 ;
    END
  END rw0_rd_out[88]
  PIN rw0_rd_out[89]
    DIRECTION OUTPUT ;
    USE SIGNAL ;
    SHAPE ABUTMENT ;
    PORT
      LAYER M3 ;
      RECT 54.891 0.000 54.909 0.054 ;
    END
  END rw0_rd_out[89]
  PIN rw0_rd_out[90]
    DIRECTION OUTPUT ;
    USE SIGNAL ;
    SHAPE ABUTMENT ;
    PORT
      LAYER M3 ;
      RECT 55.143 0.000 55.161 0.054 ;
    END
  END rw0_rd_out[90]
  PIN rw0_rd_out[91]
    DIRECTION OUTPUT ;
    USE SIGNAL ;
    SHAPE ABUTMENT ;
    PORT
      LAYER M3 ;
      RECT 55.395 0.000 55.413 0.054 ;
    END
  END rw0_rd_out[91]
  PIN rw0_rd_out[92]
    DIRECTION OUTPUT ;
    USE SIGNAL ;
    SHAPE ABUTMENT ;
    PORT
      LAYER M3 ;
      RECT 55.647 0.000 55.665 0.054 ;
    END
  END rw0_rd_out[92]
  PIN rw0_rd_out[93]
    DIRECTION OUTPUT ;
    USE SIGNAL ;
    SHAPE ABUTMENT ;
    PORT
      LAYER M3 ;
      RECT 55.899 0.000 55.917 0.054 ;
    END
  END rw0_rd_out[93]
  PIN rw0_rd_out[94]
    DIRECTION OUTPUT ;
    USE SIGNAL ;
    SHAPE ABUTMENT ;
    PORT
      LAYER M3 ;
      RECT 56.151 0.000 56.169 0.054 ;
    END
  END rw0_rd_out[94]
  PIN rw0_rd_out[95]
    DIRECTION OUTPUT ;
    USE SIGNAL ;
    SHAPE ABUTMENT ;
    PORT
      LAYER M3 ;
      RECT 56.403 0.000 56.421 0.054 ;
    END
  END rw0_rd_out[95]
  PIN rw0_rd_out[96]
    DIRECTION OUTPUT ;
    USE SIGNAL ;
    SHAPE ABUTMENT ;
    PORT
      LAYER M3 ;
      RECT 56.655 0.000 56.673 0.054 ;
    END
  END rw0_rd_out[96]
  PIN rw0_rd_out[97]
    DIRECTION OUTPUT ;
    USE SIGNAL ;
    SHAPE ABUTMENT ;
    PORT
      LAYER M3 ;
      RECT 56.907 0.000 56.925 0.054 ;
    END
  END rw0_rd_out[97]
  PIN rw0_rd_out[98]
    DIRECTION OUTPUT ;
    USE SIGNAL ;
    SHAPE ABUTMENT ;
    PORT
      LAYER M3 ;
      RECT 57.159 0.000 57.177 0.054 ;
    END
  END rw0_rd_out[98]
  PIN rw0_rd_out[99]
    DIRECTION OUTPUT ;
    USE SIGNAL ;
    SHAPE ABUTMENT ;
    PORT
      LAYER M3 ;
      RECT 57.411 0.000 57.429 0.054 ;
    END
  END rw0_rd_out[99]
  PIN rw0_rd_out[100]
    DIRECTION OUTPUT ;
    USE SIGNAL ;
    SHAPE ABUTMENT ;
    PORT
      LAYER M3 ;
      RECT 57.663 0.000 57.681 0.054 ;
    END
  END rw0_rd_out[100]
  PIN rw0_rd_out[101]
    DIRECTION OUTPUT ;
    USE SIGNAL ;
    SHAPE ABUTMENT ;
    PORT
      LAYER M3 ;
      RECT 57.915 0.000 57.933 0.054 ;
    END
  END rw0_rd_out[101]
  PIN rw0_rd_out[102]
    DIRECTION OUTPUT ;
    USE SIGNAL ;
    SHAPE ABUTMENT ;
    PORT
      LAYER M3 ;
      RECT 58.167 0.000 58.185 0.054 ;
    END
  END rw0_rd_out[102]
  PIN rw0_rd_out[103]
    DIRECTION OUTPUT ;
    USE SIGNAL ;
    SHAPE ABUTMENT ;
    PORT
      LAYER M3 ;
      RECT 58.419 0.000 58.437 0.054 ;
    END
  END rw0_rd_out[103]
  PIN rw0_rd_out[104]
    DIRECTION OUTPUT ;
    USE SIGNAL ;
    SHAPE ABUTMENT ;
    PORT
      LAYER M3 ;
      RECT 58.671 0.000 58.689 0.054 ;
    END
  END rw0_rd_out[104]
  PIN rw0_rd_out[105]
    DIRECTION OUTPUT ;
    USE SIGNAL ;
    SHAPE ABUTMENT ;
    PORT
      LAYER M3 ;
      RECT 58.923 0.000 58.941 0.054 ;
    END
  END rw0_rd_out[105]
  PIN rw0_rd_out[106]
    DIRECTION OUTPUT ;
    USE SIGNAL ;
    SHAPE ABUTMENT ;
    PORT
      LAYER M3 ;
      RECT 59.175 0.000 59.193 0.054 ;
    END
  END rw0_rd_out[106]
  PIN rw0_rd_out[107]
    DIRECTION OUTPUT ;
    USE SIGNAL ;
    SHAPE ABUTMENT ;
    PORT
      LAYER M3 ;
      RECT 59.427 0.000 59.445 0.054 ;
    END
  END rw0_rd_out[107]
  PIN rw0_rd_out[108]
    DIRECTION OUTPUT ;
    USE SIGNAL ;
    SHAPE ABUTMENT ;
    PORT
      LAYER M3 ;
      RECT 59.679 0.000 59.697 0.054 ;
    END
  END rw0_rd_out[108]
  PIN rw0_rd_out[109]
    DIRECTION OUTPUT ;
    USE SIGNAL ;
    SHAPE ABUTMENT ;
    PORT
      LAYER M3 ;
      RECT 59.931 0.000 59.949 0.054 ;
    END
  END rw0_rd_out[109]
  PIN rw0_rd_out[110]
    DIRECTION OUTPUT ;
    USE SIGNAL ;
    SHAPE ABUTMENT ;
    PORT
      LAYER M3 ;
      RECT 60.183 0.000 60.201 0.054 ;
    END
  END rw0_rd_out[110]
  PIN rw0_rd_out[111]
    DIRECTION OUTPUT ;
    USE SIGNAL ;
    SHAPE ABUTMENT ;
    PORT
      LAYER M3 ;
      RECT 60.435 0.000 60.453 0.054 ;
    END
  END rw0_rd_out[111]
  PIN rw0_rd_out[112]
    DIRECTION OUTPUT ;
    USE SIGNAL ;
    SHAPE ABUTMENT ;
    PORT
      LAYER M3 ;
      RECT 60.687 0.000 60.705 0.054 ;
    END
  END rw0_rd_out[112]
  PIN rw0_rd_out[113]
    DIRECTION OUTPUT ;
    USE SIGNAL ;
    SHAPE ABUTMENT ;
    PORT
      LAYER M3 ;
      RECT 60.939 0.000 60.957 0.054 ;
    END
  END rw0_rd_out[113]
  PIN rw0_rd_out[114]
    DIRECTION OUTPUT ;
    USE SIGNAL ;
    SHAPE ABUTMENT ;
    PORT
      LAYER M3 ;
      RECT 61.191 0.000 61.209 0.054 ;
    END
  END rw0_rd_out[114]
  PIN rw0_rd_out[115]
    DIRECTION OUTPUT ;
    USE SIGNAL ;
    SHAPE ABUTMENT ;
    PORT
      LAYER M3 ;
      RECT 61.443 0.000 61.461 0.054 ;
    END
  END rw0_rd_out[115]
  PIN rw0_rd_out[116]
    DIRECTION OUTPUT ;
    USE SIGNAL ;
    SHAPE ABUTMENT ;
    PORT
      LAYER M3 ;
      RECT 61.695 0.000 61.713 0.054 ;
    END
  END rw0_rd_out[116]
  PIN rw0_rd_out[117]
    DIRECTION OUTPUT ;
    USE SIGNAL ;
    SHAPE ABUTMENT ;
    PORT
      LAYER M3 ;
      RECT 61.947 0.000 61.965 0.054 ;
    END
  END rw0_rd_out[117]
  PIN rw0_rd_out[118]
    DIRECTION OUTPUT ;
    USE SIGNAL ;
    SHAPE ABUTMENT ;
    PORT
      LAYER M3 ;
      RECT 62.199 0.000 62.217 0.054 ;
    END
  END rw0_rd_out[118]
  PIN rw0_rd_out[119]
    DIRECTION OUTPUT ;
    USE SIGNAL ;
    SHAPE ABUTMENT ;
    PORT
      LAYER M3 ;
      RECT 62.451 0.000 62.469 0.054 ;
    END
  END rw0_rd_out[119]
  PIN rw0_rd_out[120]
    DIRECTION OUTPUT ;
    USE SIGNAL ;
    SHAPE ABUTMENT ;
    PORT
      LAYER M3 ;
      RECT 62.703 0.000 62.721 0.054 ;
    END
  END rw0_rd_out[120]
  PIN rw0_rd_out[121]
    DIRECTION OUTPUT ;
    USE SIGNAL ;
    SHAPE ABUTMENT ;
    PORT
      LAYER M3 ;
      RECT 62.955 0.000 62.973 0.054 ;
    END
  END rw0_rd_out[121]
  PIN rw0_rd_out[122]
    DIRECTION OUTPUT ;
    USE SIGNAL ;
    SHAPE ABUTMENT ;
    PORT
      LAYER M3 ;
      RECT 63.207 0.000 63.225 0.054 ;
    END
  END rw0_rd_out[122]
  PIN rw0_rd_out[123]
    DIRECTION OUTPUT ;
    USE SIGNAL ;
    SHAPE ABUTMENT ;
    PORT
      LAYER M3 ;
      RECT 63.459 0.000 63.477 0.054 ;
    END
  END rw0_rd_out[123]
  PIN rw0_rd_out[124]
    DIRECTION OUTPUT ;
    USE SIGNAL ;
    SHAPE ABUTMENT ;
    PORT
      LAYER M3 ;
      RECT 63.711 0.000 63.729 0.054 ;
    END
  END rw0_rd_out[124]
  PIN rw0_rd_out[125]
    DIRECTION OUTPUT ;
    USE SIGNAL ;
    SHAPE ABUTMENT ;
    PORT
      LAYER M3 ;
      RECT 63.963 0.000 63.981 0.054 ;
    END
  END rw0_rd_out[125]
  PIN rw0_rd_out[126]
    DIRECTION OUTPUT ;
    USE SIGNAL ;
    SHAPE ABUTMENT ;
    PORT
      LAYER M3 ;
      RECT 64.215 0.000 64.233 0.054 ;
    END
  END rw0_rd_out[126]
  PIN rw0_rd_out[127]
    DIRECTION OUTPUT ;
    USE SIGNAL ;
    SHAPE ABUTMENT ;
    PORT
      LAYER M3 ;
      RECT 64.467 0.000 64.485 0.054 ;
    END
  END rw0_rd_out[127]
  PIN rw0_rd_out[128]
    DIRECTION OUTPUT ;
    USE SIGNAL ;
    SHAPE ABUTMENT ;
    PORT
      LAYER M3 ;
      RECT 32.463 90.234 32.481 90.288 ;
    END
  END rw0_rd_out[128]
  PIN rw0_rd_out[129]
    DIRECTION OUTPUT ;
    USE SIGNAL ;
    SHAPE ABUTMENT ;
    PORT
      LAYER M3 ;
      RECT 32.715 90.234 32.733 90.288 ;
    END
  END rw0_rd_out[129]
  PIN rw0_rd_out[130]
    DIRECTION OUTPUT ;
    USE SIGNAL ;
    SHAPE ABUTMENT ;
    PORT
      LAYER M3 ;
      RECT 32.967 90.234 32.985 90.288 ;
    END
  END rw0_rd_out[130]
  PIN rw0_rd_out[131]
    DIRECTION OUTPUT ;
    USE SIGNAL ;
    SHAPE ABUTMENT ;
    PORT
      LAYER M3 ;
      RECT 33.219 90.234 33.237 90.288 ;
    END
  END rw0_rd_out[131]
  PIN rw0_rd_out[132]
    DIRECTION OUTPUT ;
    USE SIGNAL ;
    SHAPE ABUTMENT ;
    PORT
      LAYER M3 ;
      RECT 33.471 90.234 33.489 90.288 ;
    END
  END rw0_rd_out[132]
  PIN rw0_rd_out[133]
    DIRECTION OUTPUT ;
    USE SIGNAL ;
    SHAPE ABUTMENT ;
    PORT
      LAYER M3 ;
      RECT 33.723 90.234 33.741 90.288 ;
    END
  END rw0_rd_out[133]
  PIN rw0_rd_out[134]
    DIRECTION OUTPUT ;
    USE SIGNAL ;
    SHAPE ABUTMENT ;
    PORT
      LAYER M3 ;
      RECT 33.975 90.234 33.993 90.288 ;
    END
  END rw0_rd_out[134]
  PIN rw0_rd_out[135]
    DIRECTION OUTPUT ;
    USE SIGNAL ;
    SHAPE ABUTMENT ;
    PORT
      LAYER M3 ;
      RECT 34.227 90.234 34.245 90.288 ;
    END
  END rw0_rd_out[135]
  PIN rw0_rd_out[136]
    DIRECTION OUTPUT ;
    USE SIGNAL ;
    SHAPE ABUTMENT ;
    PORT
      LAYER M3 ;
      RECT 34.479 90.234 34.497 90.288 ;
    END
  END rw0_rd_out[136]
  PIN rw0_rd_out[137]
    DIRECTION OUTPUT ;
    USE SIGNAL ;
    SHAPE ABUTMENT ;
    PORT
      LAYER M3 ;
      RECT 34.731 90.234 34.749 90.288 ;
    END
  END rw0_rd_out[137]
  PIN rw0_rd_out[138]
    DIRECTION OUTPUT ;
    USE SIGNAL ;
    SHAPE ABUTMENT ;
    PORT
      LAYER M3 ;
      RECT 34.983 90.234 35.001 90.288 ;
    END
  END rw0_rd_out[138]
  PIN rw0_rd_out[139]
    DIRECTION OUTPUT ;
    USE SIGNAL ;
    SHAPE ABUTMENT ;
    PORT
      LAYER M3 ;
      RECT 35.235 90.234 35.253 90.288 ;
    END
  END rw0_rd_out[139]
  PIN rw0_rd_out[140]
    DIRECTION OUTPUT ;
    USE SIGNAL ;
    SHAPE ABUTMENT ;
    PORT
      LAYER M3 ;
      RECT 35.487 90.234 35.505 90.288 ;
    END
  END rw0_rd_out[140]
  PIN rw0_rd_out[141]
    DIRECTION OUTPUT ;
    USE SIGNAL ;
    SHAPE ABUTMENT ;
    PORT
      LAYER M3 ;
      RECT 35.739 90.234 35.757 90.288 ;
    END
  END rw0_rd_out[141]
  PIN rw0_rd_out[142]
    DIRECTION OUTPUT ;
    USE SIGNAL ;
    SHAPE ABUTMENT ;
    PORT
      LAYER M3 ;
      RECT 35.991 90.234 36.009 90.288 ;
    END
  END rw0_rd_out[142]
  PIN rw0_rd_out[143]
    DIRECTION OUTPUT ;
    USE SIGNAL ;
    SHAPE ABUTMENT ;
    PORT
      LAYER M3 ;
      RECT 36.243 90.234 36.261 90.288 ;
    END
  END rw0_rd_out[143]
  PIN rw0_rd_out[144]
    DIRECTION OUTPUT ;
    USE SIGNAL ;
    SHAPE ABUTMENT ;
    PORT
      LAYER M3 ;
      RECT 36.495 90.234 36.513 90.288 ;
    END
  END rw0_rd_out[144]
  PIN rw0_rd_out[145]
    DIRECTION OUTPUT ;
    USE SIGNAL ;
    SHAPE ABUTMENT ;
    PORT
      LAYER M3 ;
      RECT 36.747 90.234 36.765 90.288 ;
    END
  END rw0_rd_out[145]
  PIN rw0_rd_out[146]
    DIRECTION OUTPUT ;
    USE SIGNAL ;
    SHAPE ABUTMENT ;
    PORT
      LAYER M3 ;
      RECT 36.999 90.234 37.017 90.288 ;
    END
  END rw0_rd_out[146]
  PIN rw0_rd_out[147]
    DIRECTION OUTPUT ;
    USE SIGNAL ;
    SHAPE ABUTMENT ;
    PORT
      LAYER M3 ;
      RECT 37.251 90.234 37.269 90.288 ;
    END
  END rw0_rd_out[147]
  PIN rw0_rd_out[148]
    DIRECTION OUTPUT ;
    USE SIGNAL ;
    SHAPE ABUTMENT ;
    PORT
      LAYER M3 ;
      RECT 37.503 90.234 37.521 90.288 ;
    END
  END rw0_rd_out[148]
  PIN rw0_rd_out[149]
    DIRECTION OUTPUT ;
    USE SIGNAL ;
    SHAPE ABUTMENT ;
    PORT
      LAYER M3 ;
      RECT 37.755 90.234 37.773 90.288 ;
    END
  END rw0_rd_out[149]
  PIN rw0_rd_out[150]
    DIRECTION OUTPUT ;
    USE SIGNAL ;
    SHAPE ABUTMENT ;
    PORT
      LAYER M3 ;
      RECT 38.007 90.234 38.025 90.288 ;
    END
  END rw0_rd_out[150]
  PIN rw0_rd_out[151]
    DIRECTION OUTPUT ;
    USE SIGNAL ;
    SHAPE ABUTMENT ;
    PORT
      LAYER M3 ;
      RECT 38.259 90.234 38.277 90.288 ;
    END
  END rw0_rd_out[151]
  PIN rw0_rd_out[152]
    DIRECTION OUTPUT ;
    USE SIGNAL ;
    SHAPE ABUTMENT ;
    PORT
      LAYER M3 ;
      RECT 38.511 90.234 38.529 90.288 ;
    END
  END rw0_rd_out[152]
  PIN rw0_rd_out[153]
    DIRECTION OUTPUT ;
    USE SIGNAL ;
    SHAPE ABUTMENT ;
    PORT
      LAYER M3 ;
      RECT 38.763 90.234 38.781 90.288 ;
    END
  END rw0_rd_out[153]
  PIN rw0_rd_out[154]
    DIRECTION OUTPUT ;
    USE SIGNAL ;
    SHAPE ABUTMENT ;
    PORT
      LAYER M3 ;
      RECT 39.015 90.234 39.033 90.288 ;
    END
  END rw0_rd_out[154]
  PIN rw0_rd_out[155]
    DIRECTION OUTPUT ;
    USE SIGNAL ;
    SHAPE ABUTMENT ;
    PORT
      LAYER M3 ;
      RECT 39.267 90.234 39.285 90.288 ;
    END
  END rw0_rd_out[155]
  PIN rw0_rd_out[156]
    DIRECTION OUTPUT ;
    USE SIGNAL ;
    SHAPE ABUTMENT ;
    PORT
      LAYER M3 ;
      RECT 39.519 90.234 39.537 90.288 ;
    END
  END rw0_rd_out[156]
  PIN rw0_rd_out[157]
    DIRECTION OUTPUT ;
    USE SIGNAL ;
    SHAPE ABUTMENT ;
    PORT
      LAYER M3 ;
      RECT 39.771 90.234 39.789 90.288 ;
    END
  END rw0_rd_out[157]
  PIN rw0_rd_out[158]
    DIRECTION OUTPUT ;
    USE SIGNAL ;
    SHAPE ABUTMENT ;
    PORT
      LAYER M3 ;
      RECT 40.023 90.234 40.041 90.288 ;
    END
  END rw0_rd_out[158]
  PIN rw0_rd_out[159]
    DIRECTION OUTPUT ;
    USE SIGNAL ;
    SHAPE ABUTMENT ;
    PORT
      LAYER M3 ;
      RECT 40.275 90.234 40.293 90.288 ;
    END
  END rw0_rd_out[159]
  PIN rw0_rd_out[160]
    DIRECTION OUTPUT ;
    USE SIGNAL ;
    SHAPE ABUTMENT ;
    PORT
      LAYER M3 ;
      RECT 40.527 90.234 40.545 90.288 ;
    END
  END rw0_rd_out[160]
  PIN rw0_rd_out[161]
    DIRECTION OUTPUT ;
    USE SIGNAL ;
    SHAPE ABUTMENT ;
    PORT
      LAYER M3 ;
      RECT 40.779 90.234 40.797 90.288 ;
    END
  END rw0_rd_out[161]
  PIN rw0_rd_out[162]
    DIRECTION OUTPUT ;
    USE SIGNAL ;
    SHAPE ABUTMENT ;
    PORT
      LAYER M3 ;
      RECT 41.031 90.234 41.049 90.288 ;
    END
  END rw0_rd_out[162]
  PIN rw0_rd_out[163]
    DIRECTION OUTPUT ;
    USE SIGNAL ;
    SHAPE ABUTMENT ;
    PORT
      LAYER M3 ;
      RECT 41.283 90.234 41.301 90.288 ;
    END
  END rw0_rd_out[163]
  PIN rw0_rd_out[164]
    DIRECTION OUTPUT ;
    USE SIGNAL ;
    SHAPE ABUTMENT ;
    PORT
      LAYER M3 ;
      RECT 41.535 90.234 41.553 90.288 ;
    END
  END rw0_rd_out[164]
  PIN rw0_rd_out[165]
    DIRECTION OUTPUT ;
    USE SIGNAL ;
    SHAPE ABUTMENT ;
    PORT
      LAYER M3 ;
      RECT 41.787 90.234 41.805 90.288 ;
    END
  END rw0_rd_out[165]
  PIN rw0_rd_out[166]
    DIRECTION OUTPUT ;
    USE SIGNAL ;
    SHAPE ABUTMENT ;
    PORT
      LAYER M3 ;
      RECT 42.039 90.234 42.057 90.288 ;
    END
  END rw0_rd_out[166]
  PIN rw0_rd_out[167]
    DIRECTION OUTPUT ;
    USE SIGNAL ;
    SHAPE ABUTMENT ;
    PORT
      LAYER M3 ;
      RECT 42.291 90.234 42.309 90.288 ;
    END
  END rw0_rd_out[167]
  PIN rw0_rd_out[168]
    DIRECTION OUTPUT ;
    USE SIGNAL ;
    SHAPE ABUTMENT ;
    PORT
      LAYER M3 ;
      RECT 42.543 90.234 42.561 90.288 ;
    END
  END rw0_rd_out[168]
  PIN rw0_rd_out[169]
    DIRECTION OUTPUT ;
    USE SIGNAL ;
    SHAPE ABUTMENT ;
    PORT
      LAYER M3 ;
      RECT 42.795 90.234 42.813 90.288 ;
    END
  END rw0_rd_out[169]
  PIN rw0_rd_out[170]
    DIRECTION OUTPUT ;
    USE SIGNAL ;
    SHAPE ABUTMENT ;
    PORT
      LAYER M3 ;
      RECT 43.047 90.234 43.065 90.288 ;
    END
  END rw0_rd_out[170]
  PIN rw0_rd_out[171]
    DIRECTION OUTPUT ;
    USE SIGNAL ;
    SHAPE ABUTMENT ;
    PORT
      LAYER M3 ;
      RECT 43.299 90.234 43.317 90.288 ;
    END
  END rw0_rd_out[171]
  PIN rw0_rd_out[172]
    DIRECTION OUTPUT ;
    USE SIGNAL ;
    SHAPE ABUTMENT ;
    PORT
      LAYER M3 ;
      RECT 43.551 90.234 43.569 90.288 ;
    END
  END rw0_rd_out[172]
  PIN rw0_rd_out[173]
    DIRECTION OUTPUT ;
    USE SIGNAL ;
    SHAPE ABUTMENT ;
    PORT
      LAYER M3 ;
      RECT 43.803 90.234 43.821 90.288 ;
    END
  END rw0_rd_out[173]
  PIN rw0_rd_out[174]
    DIRECTION OUTPUT ;
    USE SIGNAL ;
    SHAPE ABUTMENT ;
    PORT
      LAYER M3 ;
      RECT 44.055 90.234 44.073 90.288 ;
    END
  END rw0_rd_out[174]
  PIN rw0_rd_out[175]
    DIRECTION OUTPUT ;
    USE SIGNAL ;
    SHAPE ABUTMENT ;
    PORT
      LAYER M3 ;
      RECT 44.307 90.234 44.325 90.288 ;
    END
  END rw0_rd_out[175]
  PIN rw0_rd_out[176]
    DIRECTION OUTPUT ;
    USE SIGNAL ;
    SHAPE ABUTMENT ;
    PORT
      LAYER M3 ;
      RECT 44.559 90.234 44.577 90.288 ;
    END
  END rw0_rd_out[176]
  PIN rw0_rd_out[177]
    DIRECTION OUTPUT ;
    USE SIGNAL ;
    SHAPE ABUTMENT ;
    PORT
      LAYER M3 ;
      RECT 44.811 90.234 44.829 90.288 ;
    END
  END rw0_rd_out[177]
  PIN rw0_rd_out[178]
    DIRECTION OUTPUT ;
    USE SIGNAL ;
    SHAPE ABUTMENT ;
    PORT
      LAYER M3 ;
      RECT 45.063 90.234 45.081 90.288 ;
    END
  END rw0_rd_out[178]
  PIN rw0_rd_out[179]
    DIRECTION OUTPUT ;
    USE SIGNAL ;
    SHAPE ABUTMENT ;
    PORT
      LAYER M3 ;
      RECT 45.315 90.234 45.333 90.288 ;
    END
  END rw0_rd_out[179]
  PIN rw0_rd_out[180]
    DIRECTION OUTPUT ;
    USE SIGNAL ;
    SHAPE ABUTMENT ;
    PORT
      LAYER M3 ;
      RECT 45.567 90.234 45.585 90.288 ;
    END
  END rw0_rd_out[180]
  PIN rw0_rd_out[181]
    DIRECTION OUTPUT ;
    USE SIGNAL ;
    SHAPE ABUTMENT ;
    PORT
      LAYER M3 ;
      RECT 45.819 90.234 45.837 90.288 ;
    END
  END rw0_rd_out[181]
  PIN rw0_rd_out[182]
    DIRECTION OUTPUT ;
    USE SIGNAL ;
    SHAPE ABUTMENT ;
    PORT
      LAYER M3 ;
      RECT 46.071 90.234 46.089 90.288 ;
    END
  END rw0_rd_out[182]
  PIN rw0_rd_out[183]
    DIRECTION OUTPUT ;
    USE SIGNAL ;
    SHAPE ABUTMENT ;
    PORT
      LAYER M3 ;
      RECT 46.323 90.234 46.341 90.288 ;
    END
  END rw0_rd_out[183]
  PIN rw0_rd_out[184]
    DIRECTION OUTPUT ;
    USE SIGNAL ;
    SHAPE ABUTMENT ;
    PORT
      LAYER M3 ;
      RECT 46.575 90.234 46.593 90.288 ;
    END
  END rw0_rd_out[184]
  PIN rw0_rd_out[185]
    DIRECTION OUTPUT ;
    USE SIGNAL ;
    SHAPE ABUTMENT ;
    PORT
      LAYER M3 ;
      RECT 46.827 90.234 46.845 90.288 ;
    END
  END rw0_rd_out[185]
  PIN rw0_rd_out[186]
    DIRECTION OUTPUT ;
    USE SIGNAL ;
    SHAPE ABUTMENT ;
    PORT
      LAYER M3 ;
      RECT 47.079 90.234 47.097 90.288 ;
    END
  END rw0_rd_out[186]
  PIN rw0_rd_out[187]
    DIRECTION OUTPUT ;
    USE SIGNAL ;
    SHAPE ABUTMENT ;
    PORT
      LAYER M3 ;
      RECT 47.331 90.234 47.349 90.288 ;
    END
  END rw0_rd_out[187]
  PIN rw0_rd_out[188]
    DIRECTION OUTPUT ;
    USE SIGNAL ;
    SHAPE ABUTMENT ;
    PORT
      LAYER M3 ;
      RECT 47.583 90.234 47.601 90.288 ;
    END
  END rw0_rd_out[188]
  PIN rw0_rd_out[189]
    DIRECTION OUTPUT ;
    USE SIGNAL ;
    SHAPE ABUTMENT ;
    PORT
      LAYER M3 ;
      RECT 47.835 90.234 47.853 90.288 ;
    END
  END rw0_rd_out[189]
  PIN rw0_rd_out[190]
    DIRECTION OUTPUT ;
    USE SIGNAL ;
    SHAPE ABUTMENT ;
    PORT
      LAYER M3 ;
      RECT 48.087 90.234 48.105 90.288 ;
    END
  END rw0_rd_out[190]
  PIN rw0_rd_out[191]
    DIRECTION OUTPUT ;
    USE SIGNAL ;
    SHAPE ABUTMENT ;
    PORT
      LAYER M3 ;
      RECT 48.339 90.234 48.357 90.288 ;
    END
  END rw0_rd_out[191]
  PIN rw0_rd_out[192]
    DIRECTION OUTPUT ;
    USE SIGNAL ;
    SHAPE ABUTMENT ;
    PORT
      LAYER M3 ;
      RECT 48.591 90.234 48.609 90.288 ;
    END
  END rw0_rd_out[192]
  PIN rw0_rd_out[193]
    DIRECTION OUTPUT ;
    USE SIGNAL ;
    SHAPE ABUTMENT ;
    PORT
      LAYER M3 ;
      RECT 48.843 90.234 48.861 90.288 ;
    END
  END rw0_rd_out[193]
  PIN rw0_rd_out[194]
    DIRECTION OUTPUT ;
    USE SIGNAL ;
    SHAPE ABUTMENT ;
    PORT
      LAYER M3 ;
      RECT 49.095 90.234 49.113 90.288 ;
    END
  END rw0_rd_out[194]
  PIN rw0_rd_out[195]
    DIRECTION OUTPUT ;
    USE SIGNAL ;
    SHAPE ABUTMENT ;
    PORT
      LAYER M3 ;
      RECT 49.347 90.234 49.365 90.288 ;
    END
  END rw0_rd_out[195]
  PIN rw0_rd_out[196]
    DIRECTION OUTPUT ;
    USE SIGNAL ;
    SHAPE ABUTMENT ;
    PORT
      LAYER M3 ;
      RECT 49.599 90.234 49.617 90.288 ;
    END
  END rw0_rd_out[196]
  PIN rw0_rd_out[197]
    DIRECTION OUTPUT ;
    USE SIGNAL ;
    SHAPE ABUTMENT ;
    PORT
      LAYER M3 ;
      RECT 49.851 90.234 49.869 90.288 ;
    END
  END rw0_rd_out[197]
  PIN rw0_rd_out[198]
    DIRECTION OUTPUT ;
    USE SIGNAL ;
    SHAPE ABUTMENT ;
    PORT
      LAYER M3 ;
      RECT 50.103 90.234 50.121 90.288 ;
    END
  END rw0_rd_out[198]
  PIN rw0_rd_out[199]
    DIRECTION OUTPUT ;
    USE SIGNAL ;
    SHAPE ABUTMENT ;
    PORT
      LAYER M3 ;
      RECT 50.355 90.234 50.373 90.288 ;
    END
  END rw0_rd_out[199]
  PIN rw0_rd_out[200]
    DIRECTION OUTPUT ;
    USE SIGNAL ;
    SHAPE ABUTMENT ;
    PORT
      LAYER M3 ;
      RECT 50.607 90.234 50.625 90.288 ;
    END
  END rw0_rd_out[200]
  PIN rw0_rd_out[201]
    DIRECTION OUTPUT ;
    USE SIGNAL ;
    SHAPE ABUTMENT ;
    PORT
      LAYER M3 ;
      RECT 50.859 90.234 50.877 90.288 ;
    END
  END rw0_rd_out[201]
  PIN rw0_rd_out[202]
    DIRECTION OUTPUT ;
    USE SIGNAL ;
    SHAPE ABUTMENT ;
    PORT
      LAYER M3 ;
      RECT 51.111 90.234 51.129 90.288 ;
    END
  END rw0_rd_out[202]
  PIN rw0_rd_out[203]
    DIRECTION OUTPUT ;
    USE SIGNAL ;
    SHAPE ABUTMENT ;
    PORT
      LAYER M3 ;
      RECT 51.363 90.234 51.381 90.288 ;
    END
  END rw0_rd_out[203]
  PIN rw0_rd_out[204]
    DIRECTION OUTPUT ;
    USE SIGNAL ;
    SHAPE ABUTMENT ;
    PORT
      LAYER M3 ;
      RECT 51.615 90.234 51.633 90.288 ;
    END
  END rw0_rd_out[204]
  PIN rw0_rd_out[205]
    DIRECTION OUTPUT ;
    USE SIGNAL ;
    SHAPE ABUTMENT ;
    PORT
      LAYER M3 ;
      RECT 51.867 90.234 51.885 90.288 ;
    END
  END rw0_rd_out[205]
  PIN rw0_rd_out[206]
    DIRECTION OUTPUT ;
    USE SIGNAL ;
    SHAPE ABUTMENT ;
    PORT
      LAYER M3 ;
      RECT 52.119 90.234 52.137 90.288 ;
    END
  END rw0_rd_out[206]
  PIN rw0_rd_out[207]
    DIRECTION OUTPUT ;
    USE SIGNAL ;
    SHAPE ABUTMENT ;
    PORT
      LAYER M3 ;
      RECT 52.371 90.234 52.389 90.288 ;
    END
  END rw0_rd_out[207]
  PIN rw0_rd_out[208]
    DIRECTION OUTPUT ;
    USE SIGNAL ;
    SHAPE ABUTMENT ;
    PORT
      LAYER M3 ;
      RECT 52.623 90.234 52.641 90.288 ;
    END
  END rw0_rd_out[208]
  PIN rw0_rd_out[209]
    DIRECTION OUTPUT ;
    USE SIGNAL ;
    SHAPE ABUTMENT ;
    PORT
      LAYER M3 ;
      RECT 52.875 90.234 52.893 90.288 ;
    END
  END rw0_rd_out[209]
  PIN rw0_rd_out[210]
    DIRECTION OUTPUT ;
    USE SIGNAL ;
    SHAPE ABUTMENT ;
    PORT
      LAYER M3 ;
      RECT 53.127 90.234 53.145 90.288 ;
    END
  END rw0_rd_out[210]
  PIN rw0_rd_out[211]
    DIRECTION OUTPUT ;
    USE SIGNAL ;
    SHAPE ABUTMENT ;
    PORT
      LAYER M3 ;
      RECT 53.379 90.234 53.397 90.288 ;
    END
  END rw0_rd_out[211]
  PIN rw0_rd_out[212]
    DIRECTION OUTPUT ;
    USE SIGNAL ;
    SHAPE ABUTMENT ;
    PORT
      LAYER M3 ;
      RECT 53.631 90.234 53.649 90.288 ;
    END
  END rw0_rd_out[212]
  PIN rw0_rd_out[213]
    DIRECTION OUTPUT ;
    USE SIGNAL ;
    SHAPE ABUTMENT ;
    PORT
      LAYER M3 ;
      RECT 53.883 90.234 53.901 90.288 ;
    END
  END rw0_rd_out[213]
  PIN rw0_rd_out[214]
    DIRECTION OUTPUT ;
    USE SIGNAL ;
    SHAPE ABUTMENT ;
    PORT
      LAYER M3 ;
      RECT 54.135 90.234 54.153 90.288 ;
    END
  END rw0_rd_out[214]
  PIN rw0_rd_out[215]
    DIRECTION OUTPUT ;
    USE SIGNAL ;
    SHAPE ABUTMENT ;
    PORT
      LAYER M3 ;
      RECT 54.387 90.234 54.405 90.288 ;
    END
  END rw0_rd_out[215]
  PIN rw0_rd_out[216]
    DIRECTION OUTPUT ;
    USE SIGNAL ;
    SHAPE ABUTMENT ;
    PORT
      LAYER M3 ;
      RECT 54.639 90.234 54.657 90.288 ;
    END
  END rw0_rd_out[216]
  PIN rw0_rd_out[217]
    DIRECTION OUTPUT ;
    USE SIGNAL ;
    SHAPE ABUTMENT ;
    PORT
      LAYER M3 ;
      RECT 54.891 90.234 54.909 90.288 ;
    END
  END rw0_rd_out[217]
  PIN rw0_rd_out[218]
    DIRECTION OUTPUT ;
    USE SIGNAL ;
    SHAPE ABUTMENT ;
    PORT
      LAYER M3 ;
      RECT 55.143 90.234 55.161 90.288 ;
    END
  END rw0_rd_out[218]
  PIN rw0_rd_out[219]
    DIRECTION OUTPUT ;
    USE SIGNAL ;
    SHAPE ABUTMENT ;
    PORT
      LAYER M3 ;
      RECT 55.395 90.234 55.413 90.288 ;
    END
  END rw0_rd_out[219]
  PIN rw0_rd_out[220]
    DIRECTION OUTPUT ;
    USE SIGNAL ;
    SHAPE ABUTMENT ;
    PORT
      LAYER M3 ;
      RECT 55.647 90.234 55.665 90.288 ;
    END
  END rw0_rd_out[220]
  PIN rw0_rd_out[221]
    DIRECTION OUTPUT ;
    USE SIGNAL ;
    SHAPE ABUTMENT ;
    PORT
      LAYER M3 ;
      RECT 55.899 90.234 55.917 90.288 ;
    END
  END rw0_rd_out[221]
  PIN rw0_rd_out[222]
    DIRECTION OUTPUT ;
    USE SIGNAL ;
    SHAPE ABUTMENT ;
    PORT
      LAYER M3 ;
      RECT 56.151 90.234 56.169 90.288 ;
    END
  END rw0_rd_out[222]
  PIN rw0_rd_out[223]
    DIRECTION OUTPUT ;
    USE SIGNAL ;
    SHAPE ABUTMENT ;
    PORT
      LAYER M3 ;
      RECT 56.403 90.234 56.421 90.288 ;
    END
  END rw0_rd_out[223]
  PIN rw0_rd_out[224]
    DIRECTION OUTPUT ;
    USE SIGNAL ;
    SHAPE ABUTMENT ;
    PORT
      LAYER M3 ;
      RECT 56.655 90.234 56.673 90.288 ;
    END
  END rw0_rd_out[224]
  PIN rw0_rd_out[225]
    DIRECTION OUTPUT ;
    USE SIGNAL ;
    SHAPE ABUTMENT ;
    PORT
      LAYER M3 ;
      RECT 56.907 90.234 56.925 90.288 ;
    END
  END rw0_rd_out[225]
  PIN rw0_rd_out[226]
    DIRECTION OUTPUT ;
    USE SIGNAL ;
    SHAPE ABUTMENT ;
    PORT
      LAYER M3 ;
      RECT 57.159 90.234 57.177 90.288 ;
    END
  END rw0_rd_out[226]
  PIN rw0_rd_out[227]
    DIRECTION OUTPUT ;
    USE SIGNAL ;
    SHAPE ABUTMENT ;
    PORT
      LAYER M3 ;
      RECT 57.411 90.234 57.429 90.288 ;
    END
  END rw0_rd_out[227]
  PIN rw0_rd_out[228]
    DIRECTION OUTPUT ;
    USE SIGNAL ;
    SHAPE ABUTMENT ;
    PORT
      LAYER M3 ;
      RECT 57.663 90.234 57.681 90.288 ;
    END
  END rw0_rd_out[228]
  PIN rw0_rd_out[229]
    DIRECTION OUTPUT ;
    USE SIGNAL ;
    SHAPE ABUTMENT ;
    PORT
      LAYER M3 ;
      RECT 57.915 90.234 57.933 90.288 ;
    END
  END rw0_rd_out[229]
  PIN rw0_rd_out[230]
    DIRECTION OUTPUT ;
    USE SIGNAL ;
    SHAPE ABUTMENT ;
    PORT
      LAYER M3 ;
      RECT 58.167 90.234 58.185 90.288 ;
    END
  END rw0_rd_out[230]
  PIN rw0_rd_out[231]
    DIRECTION OUTPUT ;
    USE SIGNAL ;
    SHAPE ABUTMENT ;
    PORT
      LAYER M3 ;
      RECT 58.419 90.234 58.437 90.288 ;
    END
  END rw0_rd_out[231]
  PIN rw0_rd_out[232]
    DIRECTION OUTPUT ;
    USE SIGNAL ;
    SHAPE ABUTMENT ;
    PORT
      LAYER M3 ;
      RECT 58.671 90.234 58.689 90.288 ;
    END
  END rw0_rd_out[232]
  PIN rw0_rd_out[233]
    DIRECTION OUTPUT ;
    USE SIGNAL ;
    SHAPE ABUTMENT ;
    PORT
      LAYER M3 ;
      RECT 58.923 90.234 58.941 90.288 ;
    END
  END rw0_rd_out[233]
  PIN rw0_rd_out[234]
    DIRECTION OUTPUT ;
    USE SIGNAL ;
    SHAPE ABUTMENT ;
    PORT
      LAYER M3 ;
      RECT 59.175 90.234 59.193 90.288 ;
    END
  END rw0_rd_out[234]
  PIN rw0_rd_out[235]
    DIRECTION OUTPUT ;
    USE SIGNAL ;
    SHAPE ABUTMENT ;
    PORT
      LAYER M3 ;
      RECT 59.427 90.234 59.445 90.288 ;
    END
  END rw0_rd_out[235]
  PIN rw0_rd_out[236]
    DIRECTION OUTPUT ;
    USE SIGNAL ;
    SHAPE ABUTMENT ;
    PORT
      LAYER M3 ;
      RECT 59.679 90.234 59.697 90.288 ;
    END
  END rw0_rd_out[236]
  PIN rw0_rd_out[237]
    DIRECTION OUTPUT ;
    USE SIGNAL ;
    SHAPE ABUTMENT ;
    PORT
      LAYER M3 ;
      RECT 59.931 90.234 59.949 90.288 ;
    END
  END rw0_rd_out[237]
  PIN rw0_rd_out[238]
    DIRECTION OUTPUT ;
    USE SIGNAL ;
    SHAPE ABUTMENT ;
    PORT
      LAYER M3 ;
      RECT 60.183 90.234 60.201 90.288 ;
    END
  END rw0_rd_out[238]
  PIN rw0_rd_out[239]
    DIRECTION OUTPUT ;
    USE SIGNAL ;
    SHAPE ABUTMENT ;
    PORT
      LAYER M3 ;
      RECT 60.435 90.234 60.453 90.288 ;
    END
  END rw0_rd_out[239]
  PIN rw0_rd_out[240]
    DIRECTION OUTPUT ;
    USE SIGNAL ;
    SHAPE ABUTMENT ;
    PORT
      LAYER M3 ;
      RECT 60.687 90.234 60.705 90.288 ;
    END
  END rw0_rd_out[240]
  PIN rw0_rd_out[241]
    DIRECTION OUTPUT ;
    USE SIGNAL ;
    SHAPE ABUTMENT ;
    PORT
      LAYER M3 ;
      RECT 60.939 90.234 60.957 90.288 ;
    END
  END rw0_rd_out[241]
  PIN rw0_rd_out[242]
    DIRECTION OUTPUT ;
    USE SIGNAL ;
    SHAPE ABUTMENT ;
    PORT
      LAYER M3 ;
      RECT 61.191 90.234 61.209 90.288 ;
    END
  END rw0_rd_out[242]
  PIN rw0_rd_out[243]
    DIRECTION OUTPUT ;
    USE SIGNAL ;
    SHAPE ABUTMENT ;
    PORT
      LAYER M3 ;
      RECT 61.443 90.234 61.461 90.288 ;
    END
  END rw0_rd_out[243]
  PIN rw0_rd_out[244]
    DIRECTION OUTPUT ;
    USE SIGNAL ;
    SHAPE ABUTMENT ;
    PORT
      LAYER M3 ;
      RECT 61.695 90.234 61.713 90.288 ;
    END
  END rw0_rd_out[244]
  PIN rw0_rd_out[245]
    DIRECTION OUTPUT ;
    USE SIGNAL ;
    SHAPE ABUTMENT ;
    PORT
      LAYER M3 ;
      RECT 61.947 90.234 61.965 90.288 ;
    END
  END rw0_rd_out[245]
  PIN rw0_rd_out[246]
    DIRECTION OUTPUT ;
    USE SIGNAL ;
    SHAPE ABUTMENT ;
    PORT
      LAYER M3 ;
      RECT 62.199 90.234 62.217 90.288 ;
    END
  END rw0_rd_out[246]
  PIN rw0_rd_out[247]
    DIRECTION OUTPUT ;
    USE SIGNAL ;
    SHAPE ABUTMENT ;
    PORT
      LAYER M3 ;
      RECT 62.451 90.234 62.469 90.288 ;
    END
  END rw0_rd_out[247]
  PIN rw0_rd_out[248]
    DIRECTION OUTPUT ;
    USE SIGNAL ;
    SHAPE ABUTMENT ;
    PORT
      LAYER M3 ;
      RECT 62.703 90.234 62.721 90.288 ;
    END
  END rw0_rd_out[248]
  PIN rw0_rd_out[249]
    DIRECTION OUTPUT ;
    USE SIGNAL ;
    SHAPE ABUTMENT ;
    PORT
      LAYER M3 ;
      RECT 62.955 90.234 62.973 90.288 ;
    END
  END rw0_rd_out[249]
  PIN rw0_rd_out[250]
    DIRECTION OUTPUT ;
    USE SIGNAL ;
    SHAPE ABUTMENT ;
    PORT
      LAYER M3 ;
      RECT 63.207 90.234 63.225 90.288 ;
    END
  END rw0_rd_out[250]
  PIN rw0_rd_out[251]
    DIRECTION OUTPUT ;
    USE SIGNAL ;
    SHAPE ABUTMENT ;
    PORT
      LAYER M3 ;
      RECT 63.459 90.234 63.477 90.288 ;
    END
  END rw0_rd_out[251]
  PIN rw0_rd_out[252]
    DIRECTION OUTPUT ;
    USE SIGNAL ;
    SHAPE ABUTMENT ;
    PORT
      LAYER M3 ;
      RECT 63.711 90.234 63.729 90.288 ;
    END
  END rw0_rd_out[252]
  PIN rw0_rd_out[253]
    DIRECTION OUTPUT ;
    USE SIGNAL ;
    SHAPE ABUTMENT ;
    PORT
      LAYER M3 ;
      RECT 63.963 90.234 63.981 90.288 ;
    END
  END rw0_rd_out[253]
  PIN rw0_rd_out[254]
    DIRECTION OUTPUT ;
    USE SIGNAL ;
    SHAPE ABUTMENT ;
    PORT
      LAYER M3 ;
      RECT 64.215 90.234 64.233 90.288 ;
    END
  END rw0_rd_out[254]
  PIN rw0_rd_out[255]
    DIRECTION OUTPUT ;
    USE SIGNAL ;
    SHAPE ABUTMENT ;
    PORT
      LAYER M3 ;
      RECT 64.467 90.234 64.485 90.288 ;
    END
  END rw0_rd_out[255]
  PIN rw0_addr_in[0]
    DIRECTION INPUT ;
    USE SIGNAL ;
    SHAPE ABUTMENT ;
    PORT
      LAYER M4 ;
      RECT 0.000 86.292 0.072 86.316 ;
    END
  END rw0_addr_in[0]
  PIN rw0_addr_in[1]
    DIRECTION INPUT ;
    USE SIGNAL ;
    SHAPE ABUTMENT ;
    PORT
      LAYER M4 ;
      RECT 0.000 86.964 0.072 86.988 ;
    END
  END rw0_addr_in[1]
  PIN rw0_addr_in[2]
    DIRECTION INPUT ;
    USE SIGNAL ;
    SHAPE ABUTMENT ;
    PORT
      LAYER M4 ;
      RECT 0.000 87.636 0.072 87.660 ;
    END
  END rw0_addr_in[2]
  PIN rw0_addr_in[3]
    DIRECTION INPUT ;
    USE SIGNAL ;
    SHAPE ABUTMENT ;
    PORT
      LAYER M4 ;
      RECT 0.000 88.308 0.072 88.332 ;
    END
  END rw0_addr_in[3]
  PIN rw0_addr_in[4]
    DIRECTION INPUT ;
    USE SIGNAL ;
    SHAPE ABUTMENT ;
    PORT
      LAYER M4 ;
      RECT 72.159 86.292 72.231 86.316 ;
    END
  END rw0_addr_in[4]
  PIN rw0_addr_in[5]
    DIRECTION INPUT ;
    USE SIGNAL ;
    SHAPE ABUTMENT ;
    PORT
      LAYER M4 ;
      RECT 72.159 86.964 72.231 86.988 ;
    END
  END rw0_addr_in[5]
  PIN rw0_addr_in[6]
    DIRECTION INPUT ;
    USE SIGNAL ;
    SHAPE ABUTMENT ;
    PORT
      LAYER M4 ;
      RECT 72.159 87.636 72.231 87.660 ;
    END
  END rw0_addr_in[6]
  PIN rw0_we_in
    DIRECTION INPUT ;
    USE SIGNAL ;
    SHAPE ABUTMENT ;
    PORT
      LAYER M3 ;
      RECT 64.719 90.234 64.737 90.288 ;
    END
  END rw0_we_in
  PIN rw0_ce_in
    DIRECTION INPUT ;
    USE SIGNAL ;
    SHAPE ABUTMENT ;
    PORT
      LAYER M3 ;
      RECT 64.971 90.234 64.989 90.288 ;
    END
  END rw0_ce_in
  PIN rw0_clk
    DIRECTION INPUT ;
    USE SIGNAL ;
    SHAPE ABUTMENT ;
    PORT
      LAYER M3 ;
      RECT 65.223 90.234 65.241 90.288 ;
    END
  END rw0_clk
  PIN VSS
    DIRECTION INOUT ;
    USE GROUND ;
    PORT
      LAYER M4 ;
      RECT 0.216 0.240 72.015 0.336 ;
      RECT 0.216 1.008 72.015 1.104 ;
      RECT 0.216 1.776 72.015 1.872 ;
      RECT 0.216 2.544 72.015 2.640 ;
      RECT 0.216 3.312 72.015 3.408 ;
      RECT 0.216 4.080 72.015 4.176 ;
      RECT 0.216 4.848 72.015 4.944 ;
      RECT 0.216 5.616 72.015 5.712 ;
      RECT 0.216 6.384 72.015 6.480 ;
      RECT 0.216 7.152 72.015 7.248 ;
      RECT 0.216 7.920 72.015 8.016 ;
      RECT 0.216 8.688 72.015 8.784 ;
      RECT 0.216 9.456 72.015 9.552 ;
      RECT 0.216 10.224 72.015 10.320 ;
      RECT 0.216 10.992 72.015 11.088 ;
      RECT 0.216 11.760 72.015 11.856 ;
      RECT 0.216 12.528 72.015 12.624 ;
      RECT 0.216 13.296 72.015 13.392 ;
      RECT 0.216 14.064 72.015 14.160 ;
      RECT 0.216 14.832 72.015 14.928 ;
      RECT 0.216 15.600 72.015 15.696 ;
      RECT 0.216 16.368 72.015 16.464 ;
      RECT 0.216 17.136 72.015 17.232 ;
      RECT 0.216 17.904 72.015 18.000 ;
      RECT 0.216 18.672 72.015 18.768 ;
      RECT 0.216 19.440 72.015 19.536 ;
      RECT 0.216 20.208 72.015 20.304 ;
      RECT 0.216 20.976 72.015 21.072 ;
      RECT 0.216 21.744 72.015 21.840 ;
      RECT 0.216 22.512 72.015 22.608 ;
      RECT 0.216 23.280 72.015 23.376 ;
      RECT 0.216 24.048 72.015 24.144 ;
      RECT 0.216 24.816 72.015 24.912 ;
      RECT 0.216 25.584 72.015 25.680 ;
      RECT 0.216 26.352 72.015 26.448 ;
      RECT 0.216 27.120 72.015 27.216 ;
      RECT 0.216 27.888 72.015 27.984 ;
      RECT 0.216 28.656 72.015 28.752 ;
      RECT 0.216 29.424 72.015 29.520 ;
      RECT 0.216 30.192 72.015 30.288 ;
      RECT 0.216 30.960 72.015 31.056 ;
      RECT 0.216 31.728 72.015 31.824 ;
      RECT 0.216 32.496 72.015 32.592 ;
      RECT 0.216 33.264 72.015 33.360 ;
      RECT 0.216 34.032 72.015 34.128 ;
      RECT 0.216 34.800 72.015 34.896 ;
      RECT 0.216 35.568 72.015 35.664 ;
      RECT 0.216 36.336 72.015 36.432 ;
      RECT 0.216 37.104 72.015 37.200 ;
      RECT 0.216 37.872 72.015 37.968 ;
      RECT 0.216 38.640 72.015 38.736 ;
      RECT 0.216 39.408 72.015 39.504 ;
      RECT 0.216 40.176 72.015 40.272 ;
      RECT 0.216 40.944 72.015 41.040 ;
      RECT 0.216 41.712 72.015 41.808 ;
      RECT 0.216 42.480 72.015 42.576 ;
      RECT 0.216 43.248 72.015 43.344 ;
      RECT 0.216 44.016 72.015 44.112 ;
      RECT 0.216 44.784 72.015 44.880 ;
      RECT 0.216 45.552 72.015 45.648 ;
      RECT 0.216 46.320 72.015 46.416 ;
      RECT 0.216 47.088 72.015 47.184 ;
      RECT 0.216 47.856 72.015 47.952 ;
      RECT 0.216 48.624 72.015 48.720 ;
      RECT 0.216 49.392 72.015 49.488 ;
      RECT 0.216 50.160 72.015 50.256 ;
      RECT 0.216 50.928 72.015 51.024 ;
      RECT 0.216 51.696 72.015 51.792 ;
      RECT 0.216 52.464 72.015 52.560 ;
      RECT 0.216 53.232 72.015 53.328 ;
      RECT 0.216 54.000 72.015 54.096 ;
      RECT 0.216 54.768 72.015 54.864 ;
      RECT 0.216 55.536 72.015 55.632 ;
      RECT 0.216 56.304 72.015 56.400 ;
      RECT 0.216 57.072 72.015 57.168 ;
      RECT 0.216 57.840 72.015 57.936 ;
      RECT 0.216 58.608 72.015 58.704 ;
      RECT 0.216 59.376 72.015 59.472 ;
      RECT 0.216 60.144 72.015 60.240 ;
      RECT 0.216 60.912 72.015 61.008 ;
      RECT 0.216 61.680 72.015 61.776 ;
      RECT 0.216 62.448 72.015 62.544 ;
      RECT 0.216 63.216 72.015 63.312 ;
      RECT 0.216 63.984 72.015 64.080 ;
      RECT 0.216 64.752 72.015 64.848 ;
      RECT 0.216 65.520 72.015 65.616 ;
      RECT 0.216 66.288 72.015 66.384 ;
      RECT 0.216 67.056 72.015 67.152 ;
      RECT 0.216 67.824 72.015 67.920 ;
      RECT 0.216 68.592 72.015 68.688 ;
      RECT 0.216 69.360 72.015 69.456 ;
      RECT 0.216 70.128 72.015 70.224 ;
      RECT 0.216 70.896 72.015 70.992 ;
      RECT 0.216 71.664 72.015 71.760 ;
      RECT 0.216 72.432 72.015 72.528 ;
      RECT 0.216 73.200 72.015 73.296 ;
      RECT 0.216 73.968 72.015 74.064 ;
      RECT 0.216 74.736 72.015 74.832 ;
      RECT 0.216 75.504 72.015 75.600 ;
      RECT 0.216 76.272 72.015 76.368 ;
      RECT 0.216 77.040 72.015 77.136 ;
      RECT 0.216 77.808 72.015 77.904 ;
      RECT 0.216 78.576 72.015 78.672 ;
      RECT 0.216 79.344 72.015 79.440 ;
      RECT 0.216 80.112 72.015 80.208 ;
      RECT 0.216 80.880 72.015 80.976 ;
      RECT 0.216 81.648 72.015 81.744 ;
      RECT 0.216 82.416 72.015 82.512 ;
      RECT 0.216 83.184 72.015 83.280 ;
      RECT 0.216 83.952 72.015 84.048 ;
      RECT 0.216 84.720 72.015 84.816 ;
      RECT 0.216 85.488 72.015 85.584 ;
      RECT 0.216 86.256 72.015 86.352 ;
      RECT 0.216 87.024 72.015 87.120 ;
      RECT 0.216 87.792 72.015 87.888 ;
      RECT 0.216 88.560 72.015 88.656 ;
      RECT 0.216 89.328 72.015 89.424 ;
      RECT 0.216 90.096 72.015 90.192 ;
    END
  END VSS
  PIN VDD
    DIRECTION INOUT ;
    USE POWER ;
    PORT
      LAYER M4 ;
      RECT 0.216 0.624 72.015 0.720 ;
      RECT 0.216 1.392 72.015 1.488 ;
      RECT 0.216 2.160 72.015 2.256 ;
      RECT 0.216 2.928 72.015 3.024 ;
      RECT 0.216 3.696 72.015 3.792 ;
      RECT 0.216 4.464 72.015 4.560 ;
      RECT 0.216 5.232 72.015 5.328 ;
      RECT 0.216 6.000 72.015 6.096 ;
      RECT 0.216 6.768 72.015 6.864 ;
      RECT 0.216 7.536 72.015 7.632 ;
      RECT 0.216 8.304 72.015 8.400 ;
      RECT 0.216 9.072 72.015 9.168 ;
      RECT 0.216 9.840 72.015 9.936 ;
      RECT 0.216 10.608 72.015 10.704 ;
      RECT 0.216 11.376 72.015 11.472 ;
      RECT 0.216 12.144 72.015 12.240 ;
      RECT 0.216 12.912 72.015 13.008 ;
      RECT 0.216 13.680 72.015 13.776 ;
      RECT 0.216 14.448 72.015 14.544 ;
      RECT 0.216 15.216 72.015 15.312 ;
      RECT 0.216 15.984 72.015 16.080 ;
      RECT 0.216 16.752 72.015 16.848 ;
      RECT 0.216 17.520 72.015 17.616 ;
      RECT 0.216 18.288 72.015 18.384 ;
      RECT 0.216 19.056 72.015 19.152 ;
      RECT 0.216 19.824 72.015 19.920 ;
      RECT 0.216 20.592 72.015 20.688 ;
      RECT 0.216 21.360 72.015 21.456 ;
      RECT 0.216 22.128 72.015 22.224 ;
      RECT 0.216 22.896 72.015 22.992 ;
      RECT 0.216 23.664 72.015 23.760 ;
      RECT 0.216 24.432 72.015 24.528 ;
      RECT 0.216 25.200 72.015 25.296 ;
      RECT 0.216 25.968 72.015 26.064 ;
      RECT 0.216 26.736 72.015 26.832 ;
      RECT 0.216 27.504 72.015 27.600 ;
      RECT 0.216 28.272 72.015 28.368 ;
      RECT 0.216 29.040 72.015 29.136 ;
      RECT 0.216 29.808 72.015 29.904 ;
      RECT 0.216 30.576 72.015 30.672 ;
      RECT 0.216 31.344 72.015 31.440 ;
      RECT 0.216 32.112 72.015 32.208 ;
      RECT 0.216 32.880 72.015 32.976 ;
      RECT 0.216 33.648 72.015 33.744 ;
      RECT 0.216 34.416 72.015 34.512 ;
      RECT 0.216 35.184 72.015 35.280 ;
      RECT 0.216 35.952 72.015 36.048 ;
      RECT 0.216 36.720 72.015 36.816 ;
      RECT 0.216 37.488 72.015 37.584 ;
      RECT 0.216 38.256 72.015 38.352 ;
      RECT 0.216 39.024 72.015 39.120 ;
      RECT 0.216 39.792 72.015 39.888 ;
      RECT 0.216 40.560 72.015 40.656 ;
      RECT 0.216 41.328 72.015 41.424 ;
      RECT 0.216 42.096 72.015 42.192 ;
      RECT 0.216 42.864 72.015 42.960 ;
      RECT 0.216 43.632 72.015 43.728 ;
      RECT 0.216 44.400 72.015 44.496 ;
      RECT 0.216 45.168 72.015 45.264 ;
      RECT 0.216 45.936 72.015 46.032 ;
      RECT 0.216 46.704 72.015 46.800 ;
      RECT 0.216 47.472 72.015 47.568 ;
      RECT 0.216 48.240 72.015 48.336 ;
      RECT 0.216 49.008 72.015 49.104 ;
      RECT 0.216 49.776 72.015 49.872 ;
      RECT 0.216 50.544 72.015 50.640 ;
      RECT 0.216 51.312 72.015 51.408 ;
      RECT 0.216 52.080 72.015 52.176 ;
      RECT 0.216 52.848 72.015 52.944 ;
      RECT 0.216 53.616 72.015 53.712 ;
      RECT 0.216 54.384 72.015 54.480 ;
      RECT 0.216 55.152 72.015 55.248 ;
      RECT 0.216 55.920 72.015 56.016 ;
      RECT 0.216 56.688 72.015 56.784 ;
      RECT 0.216 57.456 72.015 57.552 ;
      RECT 0.216 58.224 72.015 58.320 ;
      RECT 0.216 58.992 72.015 59.088 ;
      RECT 0.216 59.760 72.015 59.856 ;
      RECT 0.216 60.528 72.015 60.624 ;
      RECT 0.216 61.296 72.015 61.392 ;
      RECT 0.216 62.064 72.015 62.160 ;
      RECT 0.216 62.832 72.015 62.928 ;
      RECT 0.216 63.600 72.015 63.696 ;
      RECT 0.216 64.368 72.015 64.464 ;
      RECT 0.216 65.136 72.015 65.232 ;
      RECT 0.216 65.904 72.015 66.000 ;
      RECT 0.216 66.672 72.015 66.768 ;
      RECT 0.216 67.440 72.015 67.536 ;
      RECT 0.216 68.208 72.015 68.304 ;
      RECT 0.216 68.976 72.015 69.072 ;
      RECT 0.216 69.744 72.015 69.840 ;
      RECT 0.216 70.512 72.015 70.608 ;
      RECT 0.216 71.280 72.015 71.376 ;
      RECT 0.216 72.048 72.015 72.144 ;
      RECT 0.216 72.816 72.015 72.912 ;
      RECT 0.216 73.584 72.015 73.680 ;
      RECT 0.216 74.352 72.015 74.448 ;
      RECT 0.216 75.120 72.015 75.216 ;
      RECT 0.216 75.888 72.015 75.984 ;
      RECT 0.216 76.656 72.015 76.752 ;
      RECT 0.216 77.424 72.015 77.520 ;
      RECT 0.216 78.192 72.015 78.288 ;
      RECT 0.216 78.960 72.015 79.056 ;
      RECT 0.216 79.728 72.015 79.824 ;
      RECT 0.216 80.496 72.015 80.592 ;
      RECT 0.216 81.264 72.015 81.360 ;
      RECT 0.216 82.032 72.015 82.128 ;
      RECT 0.216 82.800 72.015 82.896 ;
      RECT 0.216 83.568 72.015 83.664 ;
      RECT 0.216 84.336 72.015 84.432 ;
      RECT 0.216 85.104 72.015 85.200 ;
      RECT 0.216 85.872 72.015 85.968 ;
      RECT 0.216 86.640 72.015 86.736 ;
      RECT 0.216 87.408 72.015 87.504 ;
      RECT 0.216 88.176 72.015 88.272 ;
      RECT 0.216 88.944 72.015 89.040 ;
      RECT 0.216 89.712 72.015 89.808 ;
    END
  END VDD
  OBS
    LAYER M1 ;
    RECT 0 0 72.231 90.288 ;
    LAYER M2 ;
    RECT 0 0 72.231 90.288 ;
    LAYER M3 ;
    RECT 0 0 72.231 90.288 ;
    LAYER M4 ;
    RECT 0 0 72.231 90.288 ;
  END
END fakeram_128x256_1rw

END LIBRARY
